VERSION 5.8 ;
BUSBITCHARS "[]" ;
DIVIDERCHAR "/" ;
UNITS
    DATABASE MICRONS 1000 ;
END UNITS

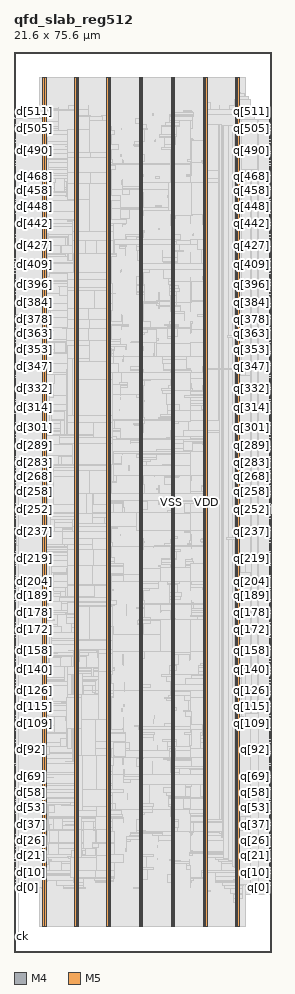
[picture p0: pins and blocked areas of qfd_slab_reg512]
MACRO qfd_slab_reg512
  FOREIGN qfd_slab_reg512 0 0 ;
  CLASS BLOCK ;
  SIZE 21.6 BY 75.6 ;
  PIN ck
    DIRECTION INPUT ;
    USE SIGNAL ;
    PORT
      LAYER M4 ;
        RECT  0.054 1.296 0.138 1.32 ;
    END
    PORT
      LAYER M4 ;
        RECT  0.108 1.296 0.371 1.32 ;
    END
  END ck
  PIN d[0]
    DIRECTION INPUT ;
    USE SIGNAL ;
    PORT
      LAYER M4 ;
        RECT  0.054 5.424 0.138 5.448 ;
    END
  END d[0]
  PIN d[100]
    DIRECTION INPUT ;
    USE SIGNAL ;
    PORT
      LAYER M4 ;
        RECT  0.054 18 0.138 18.024 ;
    END
  END d[100]
  PIN d[101]
    DIRECTION INPUT ;
    USE SIGNAL ;
    PORT
      LAYER M4 ;
        RECT  0.054 18.144 0.138 18.168 ;
    END
  END d[101]
  PIN d[102]
    DIRECTION INPUT ;
    USE SIGNAL ;
    PORT
      LAYER M4 ;
        RECT  0.054 18.288 0.138 18.312 ;
    END
  END d[102]
  PIN d[103]
    DIRECTION INPUT ;
    USE SIGNAL ;
    PORT
      LAYER M4 ;
        RECT  0.054 18.384 0.138 18.408 ;
    END
  END d[103]
  PIN d[104]
    DIRECTION INPUT ;
    USE SIGNAL ;
    PORT
      LAYER M4 ;
        RECT  0.054 18.528 0.138 18.552 ;
    END
  END d[104]
  PIN d[105]
    DIRECTION INPUT ;
    USE SIGNAL ;
    PORT
      LAYER M4 ;
        RECT  0.054 18.672 0.138 18.696 ;
    END
  END d[105]
  PIN d[106]
    DIRECTION INPUT ;
    USE SIGNAL ;
    PORT
      LAYER M4 ;
        RECT  0.054 18.768 0.138 18.792 ;
    END
  END d[106]
  PIN d[107]
    DIRECTION INPUT ;
    USE SIGNAL ;
    PORT
      LAYER M4 ;
        RECT  0.054 18.912 0.138 18.936 ;
    END
  END d[107]
  PIN d[108]
    DIRECTION INPUT ;
    USE SIGNAL ;
    PORT
      LAYER M4 ;
        RECT  0.054 19.008 0.138 19.032 ;
    END
  END d[108]
  PIN d[109]
    DIRECTION INPUT ;
    USE SIGNAL ;
    PORT
      LAYER M4 ;
        RECT  0.054 19.152 0.138 19.176 ;
    END
  END d[109]
  PIN d[10]
    DIRECTION INPUT ;
    USE SIGNAL ;
    PORT
      LAYER M4 ;
        RECT  0.054 6.672 0.138 6.696 ;
    END
  END d[10]
  PIN d[110]
    DIRECTION INPUT ;
    USE SIGNAL ;
    PORT
      LAYER M4 ;
        RECT  0.054 19.296 0.138 19.32 ;
    END
  END d[110]
  PIN d[111]
    DIRECTION INPUT ;
    USE SIGNAL ;
    PORT
      LAYER M4 ;
        RECT  0.054 19.392 0.138 19.416 ;
    END
  END d[111]
  PIN d[112]
    DIRECTION INPUT ;
    USE SIGNAL ;
    PORT
      LAYER M4 ;
        RECT  0.054 19.536 0.138 19.56 ;
    END
  END d[112]
  PIN d[113]
    DIRECTION INPUT ;
    USE SIGNAL ;
    PORT
      LAYER M4 ;
        RECT  0.054 19.68 0.138 19.704 ;
    END
  END d[113]
  PIN d[114]
    DIRECTION INPUT ;
    USE SIGNAL ;
    PORT
      LAYER M4 ;
        RECT  0.054 19.776 0.138 19.8 ;
    END
  END d[114]
  PIN d[115]
    DIRECTION INPUT ;
    USE SIGNAL ;
    PORT
      LAYER M4 ;
        RECT  0.054 19.92 0.138 19.944 ;
    END
  END d[115]
  PIN d[116]
    DIRECTION INPUT ;
    USE SIGNAL ;
    PORT
      LAYER M4 ;
        RECT  0.054 20.064 0.138 20.088 ;
    END
  END d[116]
  PIN d[117]
    DIRECTION INPUT ;
    USE SIGNAL ;
    PORT
      LAYER M4 ;
        RECT  0.054 20.16 0.138 20.184 ;
    END
  END d[117]
  PIN d[118]
    DIRECTION INPUT ;
    USE SIGNAL ;
    PORT
      LAYER M4 ;
        RECT  0.054 20.304 0.138 20.328 ;
    END
  END d[118]
  PIN d[119]
    DIRECTION INPUT ;
    USE SIGNAL ;
    PORT
      LAYER M4 ;
        RECT  0.054 20.4 0.138 20.424 ;
    END
  END d[119]
  PIN d[11]
    DIRECTION INPUT ;
    USE SIGNAL ;
    PORT
      LAYER M4 ;
        RECT  0.054 6.768 0.138 6.792 ;
    END
  END d[11]
  PIN d[120]
    DIRECTION INPUT ;
    USE SIGNAL ;
    PORT
      LAYER M4 ;
        RECT  0.054 20.544 0.138 20.568 ;
    END
  END d[120]
  PIN d[121]
    DIRECTION INPUT ;
    USE SIGNAL ;
    PORT
      LAYER M4 ;
        RECT  0.054 20.688 0.138 20.712 ;
    END
  END d[121]
  PIN d[122]
    DIRECTION INPUT ;
    USE SIGNAL ;
    PORT
      LAYER M4 ;
        RECT  0.054 20.784 0.138 20.808 ;
    END
  END d[122]
  PIN d[123]
    DIRECTION INPUT ;
    USE SIGNAL ;
    PORT
      LAYER M4 ;
        RECT  0.054 20.928 0.138 20.952 ;
    END
  END d[123]
  PIN d[124]
    DIRECTION INPUT ;
    USE SIGNAL ;
    PORT
      LAYER M4 ;
        RECT  0.054 21.072 0.138 21.096 ;
    END
  END d[124]
  PIN d[125]
    DIRECTION INPUT ;
    USE SIGNAL ;
    PORT
      LAYER M4 ;
        RECT  0.054 21.168 0.138 21.192 ;
    END
  END d[125]
  PIN d[126]
    DIRECTION INPUT ;
    USE SIGNAL ;
    PORT
      LAYER M4 ;
        RECT  0.054 21.312 0.138 21.336 ;
    END
  END d[126]
  PIN d[127]
    DIRECTION INPUT ;
    USE SIGNAL ;
    PORT
      LAYER M4 ;
        RECT  0.054 21.408 0.138 21.432 ;
    END
  END d[127]
  PIN d[128]
    DIRECTION INPUT ;
    USE SIGNAL ;
    PORT
      LAYER M4 ;
        RECT  0.054 21.552 0.138 21.576 ;
    END
  END d[128]
  PIN d[129]
    DIRECTION INPUT ;
    USE SIGNAL ;
    PORT
      LAYER M4 ;
        RECT  0.054 21.696 0.138 21.72 ;
    END
  END d[129]
  PIN d[12]
    DIRECTION INPUT ;
    USE SIGNAL ;
    PORT
      LAYER M4 ;
        RECT  0.054 6.912 0.138 6.936 ;
    END
  END d[12]
  PIN d[130]
    DIRECTION INPUT ;
    USE SIGNAL ;
    PORT
      LAYER M4 ;
        RECT  0.054 21.792 0.138 21.816 ;
    END
  END d[130]
  PIN d[131]
    DIRECTION INPUT ;
    USE SIGNAL ;
    PORT
      LAYER M4 ;
        RECT  0.054 21.936 0.138 21.96 ;
    END
  END d[131]
  PIN d[132]
    DIRECTION INPUT ;
    USE SIGNAL ;
    PORT
      LAYER M4 ;
        RECT  0.054 22.08 0.138 22.104 ;
    END
  END d[132]
  PIN d[133]
    DIRECTION INPUT ;
    USE SIGNAL ;
    PORT
      LAYER M4 ;
        RECT  0.054 22.176 0.138 22.2 ;
    END
  END d[133]
  PIN d[134]
    DIRECTION INPUT ;
    USE SIGNAL ;
    PORT
      LAYER M4 ;
        RECT  0.054 22.32 0.138 22.344 ;
    END
  END d[134]
  PIN d[135]
    DIRECTION INPUT ;
    USE SIGNAL ;
    PORT
      LAYER M4 ;
        RECT  0.054 22.464 0.138 22.488 ;
    END
  END d[135]
  PIN d[136]
    DIRECTION INPUT ;
    USE SIGNAL ;
    PORT
      LAYER M4 ;
        RECT  0.054 22.56 0.138 22.584 ;
    END
  END d[136]
  PIN d[137]
    DIRECTION INPUT ;
    USE SIGNAL ;
    PORT
      LAYER M4 ;
        RECT  0.054 22.704 0.138 22.728 ;
    END
  END d[137]
  PIN d[138]
    DIRECTION INPUT ;
    USE SIGNAL ;
    PORT
      LAYER M4 ;
        RECT  0.054 22.8 0.138 22.824 ;
    END
  END d[138]
  PIN d[139]
    DIRECTION INPUT ;
    USE SIGNAL ;
    PORT
      LAYER M4 ;
        RECT  0.054 22.944 0.138 22.968 ;
    END
  END d[139]
  PIN d[13]
    DIRECTION INPUT ;
    USE SIGNAL ;
    PORT
      LAYER M4 ;
        RECT  0.054 7.008 0.138 7.032 ;
    END
  END d[13]
  PIN d[140]
    DIRECTION INPUT ;
    USE SIGNAL ;
    PORT
      LAYER M4 ;
        RECT  0.054 23.088 0.138 23.112 ;
    END
  END d[140]
  PIN d[141]
    DIRECTION INPUT ;
    USE SIGNAL ;
    PORT
      LAYER M4 ;
        RECT  0.054 23.184 0.138 23.208 ;
    END
  END d[141]
  PIN d[142]
    DIRECTION INPUT ;
    USE SIGNAL ;
    PORT
      LAYER M4 ;
        RECT  0.054 23.328 0.138 23.352 ;
    END
  END d[142]
  PIN d[143]
    DIRECTION INPUT ;
    USE SIGNAL ;
    PORT
      LAYER M4 ;
        RECT  0.054 23.472 0.138 23.496 ;
    END
  END d[143]
  PIN d[144]
    DIRECTION INPUT ;
    USE SIGNAL ;
    PORT
      LAYER M4 ;
        RECT  0.054 23.568 0.138 23.592 ;
    END
  END d[144]
  PIN d[145]
    DIRECTION INPUT ;
    USE SIGNAL ;
    PORT
      LAYER M4 ;
        RECT  0.054 23.712 0.138 23.736 ;
    END
  END d[145]
  PIN d[146]
    DIRECTION INPUT ;
    USE SIGNAL ;
    PORT
      LAYER M4 ;
        RECT  0.054 23.808 0.138 23.832 ;
    END
  END d[146]
  PIN d[147]
    DIRECTION INPUT ;
    USE SIGNAL ;
    PORT
      LAYER M4 ;
        RECT  0.054 23.952 0.138 23.976 ;
    END
  END d[147]
  PIN d[148]
    DIRECTION INPUT ;
    USE SIGNAL ;
    PORT
      LAYER M4 ;
        RECT  0.054 24.096 0.138 24.12 ;
    END
  END d[148]
  PIN d[149]
    DIRECTION INPUT ;
    USE SIGNAL ;
    PORT
      LAYER M4 ;
        RECT  0.054 24.192 0.138 24.216 ;
    END
  END d[149]
  PIN d[14]
    DIRECTION INPUT ;
    USE SIGNAL ;
    PORT
      LAYER M4 ;
        RECT  0.054 7.152 0.138 7.176 ;
    END
  END d[14]
  PIN d[150]
    DIRECTION INPUT ;
    USE SIGNAL ;
    PORT
      LAYER M4 ;
        RECT  0.054 24.336 0.138 24.36 ;
    END
  END d[150]
  PIN d[151]
    DIRECTION INPUT ;
    USE SIGNAL ;
    PORT
      LAYER M4 ;
        RECT  0.054 24.48 0.138 24.504 ;
    END
  END d[151]
  PIN d[152]
    DIRECTION INPUT ;
    USE SIGNAL ;
    PORT
      LAYER M4 ;
        RECT  0.054 24.576 0.138 24.6 ;
    END
  END d[152]
  PIN d[153]
    DIRECTION INPUT ;
    USE SIGNAL ;
    PORT
      LAYER M4 ;
        RECT  0.054 24.72 0.138 24.744 ;
    END
  END d[153]
  PIN d[154]
    DIRECTION INPUT ;
    USE SIGNAL ;
    PORT
      LAYER M4 ;
        RECT  0.054 24.864 0.138 24.888 ;
    END
  END d[154]
  PIN d[155]
    DIRECTION INPUT ;
    USE SIGNAL ;
    PORT
      LAYER M4 ;
        RECT  0.054 24.96 0.138 24.984 ;
    END
  END d[155]
  PIN d[156]
    DIRECTION INPUT ;
    USE SIGNAL ;
    PORT
      LAYER M4 ;
        RECT  0.054 25.104 0.138 25.128 ;
    END
  END d[156]
  PIN d[157]
    DIRECTION INPUT ;
    USE SIGNAL ;
    PORT
      LAYER M4 ;
        RECT  0.054 25.2 0.138 25.224 ;
    END
  END d[157]
  PIN d[158]
    DIRECTION INPUT ;
    USE SIGNAL ;
    PORT
      LAYER M4 ;
        RECT  0.054 25.344 0.138 25.368 ;
    END
  END d[158]
  PIN d[159]
    DIRECTION INPUT ;
    USE SIGNAL ;
    PORT
      LAYER M4 ;
        RECT  0.054 25.488 0.138 25.512 ;
    END
  END d[159]
  PIN d[15]
    DIRECTION INPUT ;
    USE SIGNAL ;
    PORT
      LAYER M4 ;
        RECT  0.054 7.296 0.138 7.32 ;
    END
  END d[15]
  PIN d[160]
    DIRECTION INPUT ;
    USE SIGNAL ;
    PORT
      LAYER M4 ;
        RECT  0.054 25.584 0.138 25.608 ;
    END
  END d[160]
  PIN d[161]
    DIRECTION INPUT ;
    USE SIGNAL ;
    PORT
      LAYER M4 ;
        RECT  0.054 25.728 0.138 25.752 ;
    END
  END d[161]
  PIN d[162]
    DIRECTION INPUT ;
    USE SIGNAL ;
    PORT
      LAYER M4 ;
        RECT  0.054 25.872 0.138 25.896 ;
    END
  END d[162]
  PIN d[163]
    DIRECTION INPUT ;
    USE SIGNAL ;
    PORT
      LAYER M4 ;
        RECT  0.054 25.968 0.138 25.992 ;
    END
  END d[163]
  PIN d[164]
    DIRECTION INPUT ;
    USE SIGNAL ;
    PORT
      LAYER M4 ;
        RECT  0.054 26.112 0.138 26.136 ;
    END
  END d[164]
  PIN d[165]
    DIRECTION INPUT ;
    USE SIGNAL ;
    PORT
      LAYER M4 ;
        RECT  0.054 26.208 0.138 26.232 ;
    END
  END d[165]
  PIN d[166]
    DIRECTION INPUT ;
    USE SIGNAL ;
    PORT
      LAYER M4 ;
        RECT  0.054 26.352 0.138 26.376 ;
    END
  END d[166]
  PIN d[167]
    DIRECTION INPUT ;
    USE SIGNAL ;
    PORT
      LAYER M4 ;
        RECT  0.054 26.496 0.138 26.52 ;
    END
  END d[167]
  PIN d[168]
    DIRECTION INPUT ;
    USE SIGNAL ;
    PORT
      LAYER M4 ;
        RECT  0.054 26.592 0.138 26.616 ;
    END
    PORT
      LAYER M4 ;
        RECT  0.025 26.592 0.108 26.616 ;
    END
  END d[168]
  PIN d[169]
    DIRECTION INPUT ;
    USE SIGNAL ;
    PORT
      LAYER M4 ;
        RECT  0.054 26.736 0.138 26.76 ;
    END
  END d[169]
  PIN d[16]
    DIRECTION INPUT ;
    USE SIGNAL ;
    PORT
      LAYER M4 ;
        RECT  0.054 7.392 0.138 7.416 ;
    END
  END d[16]
  PIN d[170]
    DIRECTION INPUT ;
    USE SIGNAL ;
    PORT
      LAYER M4 ;
        RECT  0.054 26.88 0.138 26.904 ;
    END
  END d[170]
  PIN d[171]
    DIRECTION INPUT ;
    USE SIGNAL ;
    PORT
      LAYER M4 ;
        RECT  0.054 26.976 0.138 27 ;
    END
  END d[171]
  PIN d[172]
    DIRECTION INPUT ;
    USE SIGNAL ;
    PORT
      LAYER M4 ;
        RECT  0.054 27.12 0.138 27.144 ;
    END
  END d[172]
  PIN d[173]
    DIRECTION INPUT ;
    USE SIGNAL ;
    PORT
      LAYER M4 ;
        RECT  0.054 27.264 0.138 27.288 ;
    END
  END d[173]
  PIN d[174]
    DIRECTION INPUT ;
    USE SIGNAL ;
    PORT
      LAYER M4 ;
        RECT  0.054 27.36 0.138 27.384 ;
    END
  END d[174]
  PIN d[175]
    DIRECTION INPUT ;
    USE SIGNAL ;
    PORT
      LAYER M4 ;
        RECT  0.054 27.504 0.138 27.528 ;
    END
  END d[175]
  PIN d[176]
    DIRECTION INPUT ;
    USE SIGNAL ;
    PORT
      LAYER M4 ;
        RECT  0.054 27.6 0.138 27.624 ;
    END
  END d[176]
  PIN d[177]
    DIRECTION INPUT ;
    USE SIGNAL ;
    PORT
      LAYER M4 ;
        RECT  0.054 27.744 0.138 27.768 ;
    END
  END d[177]
  PIN d[178]
    DIRECTION INPUT ;
    USE SIGNAL ;
    PORT
      LAYER M4 ;
        RECT  0.054 27.888 0.138 27.912 ;
    END
  END d[178]
  PIN d[179]
    DIRECTION INPUT ;
    USE SIGNAL ;
    PORT
      LAYER M4 ;
        RECT  0.054 27.984 0.138 28.008 ;
    END
  END d[179]
  PIN d[17]
    DIRECTION INPUT ;
    USE SIGNAL ;
    PORT
      LAYER M4 ;
        RECT  0.054 7.536 0.138 7.56 ;
    END
  END d[17]
  PIN d[180]
    DIRECTION INPUT ;
    USE SIGNAL ;
    PORT
      LAYER M4 ;
        RECT  0.054 28.128 0.138 28.152 ;
    END
  END d[180]
  PIN d[181]
    DIRECTION INPUT ;
    USE SIGNAL ;
    PORT
      LAYER M4 ;
        RECT  0.054 28.272 0.138 28.296 ;
    END
  END d[181]
  PIN d[182]
    DIRECTION INPUT ;
    USE SIGNAL ;
    PORT
      LAYER M4 ;
        RECT  0.054 28.368 0.138 28.392 ;
    END
  END d[182]
  PIN d[183]
    DIRECTION INPUT ;
    USE SIGNAL ;
    PORT
      LAYER M4 ;
        RECT  0.054 28.512 0.138 28.536 ;
    END
  END d[183]
  PIN d[184]
    DIRECTION INPUT ;
    USE SIGNAL ;
    PORT
      LAYER M4 ;
        RECT  0.054 28.608 0.138 28.632 ;
    END
  END d[184]
  PIN d[185]
    DIRECTION INPUT ;
    USE SIGNAL ;
    PORT
      LAYER M4 ;
        RECT  0.054 28.752 0.138 28.776 ;
    END
  END d[185]
  PIN d[186]
    DIRECTION INPUT ;
    USE SIGNAL ;
    PORT
      LAYER M4 ;
        RECT  0.054 28.896 0.138 28.92 ;
    END
  END d[186]
  PIN d[187]
    DIRECTION INPUT ;
    USE SIGNAL ;
    PORT
      LAYER M4 ;
        RECT  0.054 28.992 0.138 29.016 ;
    END
  END d[187]
  PIN d[188]
    DIRECTION INPUT ;
    USE SIGNAL ;
    PORT
      LAYER M4 ;
        RECT  0.054 29.136 0.138 29.16 ;
    END
  END d[188]
  PIN d[189]
    DIRECTION INPUT ;
    USE SIGNAL ;
    PORT
      LAYER M4 ;
        RECT  0.054 29.28 0.138 29.304 ;
    END
  END d[189]
  PIN d[18]
    DIRECTION INPUT ;
    USE SIGNAL ;
    PORT
      LAYER M4 ;
        RECT  0.054 7.68 0.138 7.704 ;
    END
  END d[18]
  PIN d[190]
    DIRECTION INPUT ;
    USE SIGNAL ;
    PORT
      LAYER M4 ;
        RECT  0.054 29.376 0.138 29.4 ;
    END
  END d[190]
  PIN d[191]
    DIRECTION INPUT ;
    USE SIGNAL ;
    PORT
      LAYER M4 ;
        RECT  0.054 29.52 0.138 29.544 ;
    END
  END d[191]
  PIN d[192]
    DIRECTION INPUT ;
    USE SIGNAL ;
    PORT
      LAYER M4 ;
        RECT  0.054 29.664 0.138 29.688 ;
    END
  END d[192]
  PIN d[193]
    DIRECTION INPUT ;
    USE SIGNAL ;
    PORT
      LAYER M4 ;
        RECT  0.054 29.76 0.138 29.784 ;
    END
  END d[193]
  PIN d[194]
    DIRECTION INPUT ;
    USE SIGNAL ;
    PORT
      LAYER M4 ;
        RECT  0.054 29.904 0.138 29.928 ;
    END
  END d[194]
  PIN d[195]
    DIRECTION INPUT ;
    USE SIGNAL ;
    PORT
      LAYER M4 ;
        RECT  0.054 30 0.138 30.024 ;
    END
  END d[195]
  PIN d[196]
    DIRECTION INPUT ;
    USE SIGNAL ;
    PORT
      LAYER M4 ;
        RECT  0.054 30.144 0.138 30.168 ;
    END
  END d[196]
  PIN d[197]
    DIRECTION INPUT ;
    USE SIGNAL ;
    PORT
      LAYER M4 ;
        RECT  0.054 30.288 0.138 30.312 ;
    END
  END d[197]
  PIN d[198]
    DIRECTION INPUT ;
    USE SIGNAL ;
    PORT
      LAYER M4 ;
        RECT  0.054 30.384 0.138 30.408 ;
    END
  END d[198]
  PIN d[199]
    DIRECTION INPUT ;
    USE SIGNAL ;
    PORT
      LAYER M4 ;
        RECT  0.054 30.528 0.138 30.552 ;
    END
  END d[199]
  PIN d[19]
    DIRECTION INPUT ;
    USE SIGNAL ;
    PORT
      LAYER M4 ;
        RECT  0.054 7.776 0.138 7.8 ;
    END
  END d[19]
  PIN d[1]
    DIRECTION INPUT ;
    USE SIGNAL ;
    PORT
      LAYER M4 ;
        RECT  0.054 5.52 0.138 5.544 ;
    END
  END d[1]
  PIN d[200]
    DIRECTION INPUT ;
    USE SIGNAL ;
    PORT
      LAYER M4 ;
        RECT  0.054 30.672 0.138 30.696 ;
    END
  END d[200]
  PIN d[201]
    DIRECTION INPUT ;
    USE SIGNAL ;
    PORT
      LAYER M4 ;
        RECT  0.054 30.768 0.138 30.792 ;
    END
  END d[201]
  PIN d[202]
    DIRECTION INPUT ;
    USE SIGNAL ;
    PORT
      LAYER M4 ;
        RECT  0.054 30.912 0.138 30.936 ;
    END
  END d[202]
  PIN d[203]
    DIRECTION INPUT ;
    USE SIGNAL ;
    PORT
      LAYER M4 ;
        RECT  0.054 31.008 0.138 31.032 ;
    END
  END d[203]
  PIN d[204]
    DIRECTION INPUT ;
    USE SIGNAL ;
    PORT
      LAYER M4 ;
        RECT  0.054 31.152 0.138 31.176 ;
    END
  END d[204]
  PIN d[205]
    DIRECTION INPUT ;
    USE SIGNAL ;
    PORT
      LAYER M4 ;
        RECT  0.054 31.296 0.138 31.32 ;
    END
  END d[205]
  PIN d[206]
    DIRECTION INPUT ;
    USE SIGNAL ;
    PORT
      LAYER M4 ;
        RECT  0.054 31.392 0.138 31.416 ;
    END
  END d[206]
  PIN d[207]
    DIRECTION INPUT ;
    USE SIGNAL ;
    PORT
      LAYER M4 ;
        RECT  0.054 31.536 0.138 31.56 ;
    END
  END d[207]
  PIN d[208]
    DIRECTION INPUT ;
    USE SIGNAL ;
    PORT
      LAYER M4 ;
        RECT  0.054 31.68 0.138 31.704 ;
    END
  END d[208]
  PIN d[209]
    DIRECTION INPUT ;
    USE SIGNAL ;
    PORT
      LAYER M4 ;
        RECT  0.054 31.776 0.138 31.8 ;
    END
  END d[209]
  PIN d[20]
    DIRECTION INPUT ;
    USE SIGNAL ;
    PORT
      LAYER M4 ;
        RECT  0.054 7.92 0.138 7.944 ;
    END
  END d[20]
  PIN d[210]
    DIRECTION INPUT ;
    USE SIGNAL ;
    PORT
      LAYER M4 ;
        RECT  0.054 31.92 0.138 31.944 ;
    END
  END d[210]
  PIN d[211]
    DIRECTION INPUT ;
    USE SIGNAL ;
    PORT
      LAYER M4 ;
        RECT  0.054 32.064 0.138 32.088 ;
    END
  END d[211]
  PIN d[212]
    DIRECTION INPUT ;
    USE SIGNAL ;
    PORT
      LAYER M4 ;
        RECT  0.054 32.16 0.138 32.184 ;
    END
  END d[212]
  PIN d[213]
    DIRECTION INPUT ;
    USE SIGNAL ;
    PORT
      LAYER M4 ;
        RECT  0.054 32.304 0.138 32.328 ;
    END
  END d[213]
  PIN d[214]
    DIRECTION INPUT ;
    USE SIGNAL ;
    PORT
      LAYER M4 ;
        RECT  0.054 32.4 0.138 32.424 ;
    END
  END d[214]
  PIN d[215]
    DIRECTION INPUT ;
    USE SIGNAL ;
    PORT
      LAYER M4 ;
        RECT  0.054 32.544 0.138 32.568 ;
    END
  END d[215]
  PIN d[216]
    DIRECTION INPUT ;
    USE SIGNAL ;
    PORT
      LAYER M4 ;
        RECT  0.054 32.688 0.138 32.712 ;
    END
  END d[216]
  PIN d[217]
    DIRECTION INPUT ;
    USE SIGNAL ;
    PORT
      LAYER M4 ;
        RECT  0.054 32.784 0.138 32.808 ;
    END
  END d[217]
  PIN d[218]
    DIRECTION INPUT ;
    USE SIGNAL ;
    PORT
      LAYER M4 ;
        RECT  0.054 32.928 0.138 32.952 ;
    END
  END d[218]
  PIN d[219]
    DIRECTION INPUT ;
    USE SIGNAL ;
    PORT
      LAYER M4 ;
        RECT  0.054 33.072 0.138 33.096 ;
    END
  END d[219]
  PIN d[21]
    DIRECTION INPUT ;
    USE SIGNAL ;
    PORT
      LAYER M4 ;
        RECT  0.054 8.064 0.138 8.088 ;
    END
  END d[21]
  PIN d[220]
    DIRECTION INPUT ;
    USE SIGNAL ;
    PORT
      LAYER M4 ;
        RECT  0.054 33.168 0.138 33.192 ;
    END
  END d[220]
  PIN d[221]
    DIRECTION INPUT ;
    USE SIGNAL ;
    PORT
      LAYER M4 ;
        RECT  0.054 33.312 0.138 33.336 ;
    END
  END d[221]
  PIN d[222]
    DIRECTION INPUT ;
    USE SIGNAL ;
    PORT
      LAYER M4 ;
        RECT  0.054 33.408 0.138 33.432 ;
    END
  END d[222]
  PIN d[223]
    DIRECTION INPUT ;
    USE SIGNAL ;
    PORT
      LAYER M4 ;
        RECT  0.054 33.552 0.138 33.576 ;
    END
  END d[223]
  PIN d[224]
    DIRECTION INPUT ;
    USE SIGNAL ;
    PORT
      LAYER M4 ;
        RECT  0.054 33.696 0.138 33.72 ;
    END
  END d[224]
  PIN d[225]
    DIRECTION INPUT ;
    USE SIGNAL ;
    PORT
      LAYER M4 ;
        RECT  0.054 33.792 0.138 33.816 ;
    END
  END d[225]
  PIN d[226]
    DIRECTION INPUT ;
    USE SIGNAL ;
    PORT
      LAYER M4 ;
        RECT  0.054 33.936 0.138 33.96 ;
    END
  END d[226]
  PIN d[227]
    DIRECTION INPUT ;
    USE SIGNAL ;
    PORT
      LAYER M4 ;
        RECT  0.054 34.08 0.138 34.104 ;
    END
  END d[227]
  PIN d[228]
    DIRECTION INPUT ;
    USE SIGNAL ;
    PORT
      LAYER M4 ;
        RECT  0.054 34.176 0.138 34.2 ;
    END
  END d[228]
  PIN d[229]
    DIRECTION INPUT ;
    USE SIGNAL ;
    PORT
      LAYER M4 ;
        RECT  0.054 34.32 0.138 34.344 ;
    END
  END d[229]
  PIN d[22]
    DIRECTION INPUT ;
    USE SIGNAL ;
    PORT
      LAYER M4 ;
        RECT  0.054 8.16 0.138 8.184 ;
    END
  END d[22]
  PIN d[230]
    DIRECTION INPUT ;
    USE SIGNAL ;
    PORT
      LAYER M4 ;
        RECT  0.054 34.464 0.138 34.488 ;
    END
  END d[230]
  PIN d[231]
    DIRECTION INPUT ;
    USE SIGNAL ;
    PORT
      LAYER M4 ;
        RECT  0.054 34.56 0.138 34.584 ;
    END
  END d[231]
  PIN d[232]
    DIRECTION INPUT ;
    USE SIGNAL ;
    PORT
      LAYER M4 ;
        RECT  0.054 34.704 0.138 34.728 ;
    END
  END d[232]
  PIN d[233]
    DIRECTION INPUT ;
    USE SIGNAL ;
    PORT
      LAYER M4 ;
        RECT  0.054 34.8 0.138 34.824 ;
    END
  END d[233]
  PIN d[234]
    DIRECTION INPUT ;
    USE SIGNAL ;
    PORT
      LAYER M4 ;
        RECT  0.054 34.944 0.138 34.968 ;
    END
  END d[234]
  PIN d[235]
    DIRECTION INPUT ;
    USE SIGNAL ;
    PORT
      LAYER M4 ;
        RECT  0.054 35.088 0.138 35.112 ;
    END
  END d[235]
  PIN d[236]
    DIRECTION INPUT ;
    USE SIGNAL ;
    PORT
      LAYER M4 ;
        RECT  0.054 35.184 0.138 35.208 ;
    END
  END d[236]
  PIN d[237]
    DIRECTION INPUT ;
    USE SIGNAL ;
    PORT
      LAYER M4 ;
        RECT  0.054 35.328 0.138 35.352 ;
    END
  END d[237]
  PIN d[238]
    DIRECTION INPUT ;
    USE SIGNAL ;
    PORT
      LAYER M4 ;
        RECT  0.054 35.472 0.138 35.496 ;
    END
  END d[238]
  PIN d[239]
    DIRECTION INPUT ;
    USE SIGNAL ;
    PORT
      LAYER M4 ;
        RECT  0.054 35.568 0.138 35.592 ;
    END
  END d[239]
  PIN d[23]
    DIRECTION INPUT ;
    USE SIGNAL ;
    PORT
      LAYER M4 ;
        RECT  0.054 8.304 0.138 8.328 ;
    END
  END d[23]
  PIN d[240]
    DIRECTION INPUT ;
    USE SIGNAL ;
    PORT
      LAYER M4 ;
        RECT  0.054 35.712 0.138 35.736 ;
    END
  END d[240]
  PIN d[241]
    DIRECTION INPUT ;
    USE SIGNAL ;
    PORT
      LAYER M4 ;
        RECT  0.054 35.808 0.138 35.832 ;
    END
    PORT
      LAYER M4 ;
        RECT  0.025 35.808 0.108 35.832 ;
    END
  END d[241]
  PIN d[242]
    DIRECTION INPUT ;
    USE SIGNAL ;
    PORT
      LAYER M4 ;
        RECT  0.054 35.952 0.138 35.976 ;
    END
  END d[242]
  PIN d[243]
    DIRECTION INPUT ;
    USE SIGNAL ;
    PORT
      LAYER M4 ;
        RECT  0.054 36.096 0.138 36.12 ;
    END
  END d[243]
  PIN d[244]
    DIRECTION INPUT ;
    USE SIGNAL ;
    PORT
      LAYER M4 ;
        RECT  0.054 36.192 0.138 36.216 ;
    END
  END d[244]
  PIN d[245]
    DIRECTION INPUT ;
    USE SIGNAL ;
    PORT
      LAYER M4 ;
        RECT  0.054 36.336 0.138 36.36 ;
    END
  END d[245]
  PIN d[246]
    DIRECTION INPUT ;
    USE SIGNAL ;
    PORT
      LAYER M4 ;
        RECT  0.054 36.48 0.138 36.504 ;
    END
  END d[246]
  PIN d[247]
    DIRECTION INPUT ;
    USE SIGNAL ;
    PORT
      LAYER M4 ;
        RECT  0.054 36.576 0.138 36.6 ;
    END
  END d[247]
  PIN d[248]
    DIRECTION INPUT ;
    USE SIGNAL ;
    PORT
      LAYER M4 ;
        RECT  0.054 36.72 0.138 36.744 ;
    END
  END d[248]
  PIN d[249]
    DIRECTION INPUT ;
    USE SIGNAL ;
    PORT
      LAYER M4 ;
        RECT  0.054 36.864 0.138 36.888 ;
    END
  END d[249]
  PIN d[24]
    DIRECTION INPUT ;
    USE SIGNAL ;
    PORT
      LAYER M4 ;
        RECT  0.054 8.4 0.138 8.424 ;
    END
  END d[24]
  PIN d[250]
    DIRECTION INPUT ;
    USE SIGNAL ;
    PORT
      LAYER M4 ;
        RECT  0.054 36.96 0.138 36.984 ;
    END
  END d[250]
  PIN d[251]
    DIRECTION INPUT ;
    USE SIGNAL ;
    PORT
      LAYER M4 ;
        RECT  0.054 37.104 0.138 37.128 ;
    END
  END d[251]
  PIN d[252]
    DIRECTION INPUT ;
    USE SIGNAL ;
    PORT
      LAYER M4 ;
        RECT  0.054 37.2 0.138 37.224 ;
    END
  END d[252]
  PIN d[253]
    DIRECTION INPUT ;
    USE SIGNAL ;
    PORT
      LAYER M4 ;
        RECT  0.054 37.344 0.138 37.368 ;
    END
  END d[253]
  PIN d[254]
    DIRECTION INPUT ;
    USE SIGNAL ;
    PORT
      LAYER M4 ;
        RECT  0.054 37.488 0.138 37.512 ;
    END
  END d[254]
  PIN d[255]
    DIRECTION INPUT ;
    USE SIGNAL ;
    PORT
      LAYER M4 ;
        RECT  0.054 37.584 0.138 37.608 ;
    END
  END d[255]
  PIN d[256]
    DIRECTION INPUT ;
    USE SIGNAL ;
    PORT
      LAYER M4 ;
        RECT  0.054 37.728 0.138 37.752 ;
    END
  END d[256]
  PIN d[257]
    DIRECTION INPUT ;
    USE SIGNAL ;
    PORT
      LAYER M4 ;
        RECT  0.054 37.872 0.138 37.896 ;
    END
  END d[257]
  PIN d[258]
    DIRECTION INPUT ;
    USE SIGNAL ;
    PORT
      LAYER M4 ;
        RECT  0.054 37.968 0.138 37.992 ;
    END
  END d[258]
  PIN d[259]
    DIRECTION INPUT ;
    USE SIGNAL ;
    PORT
      LAYER M4 ;
        RECT  0.054 38.112 0.138 38.136 ;
    END
  END d[259]
  PIN d[25]
    DIRECTION INPUT ;
    USE SIGNAL ;
    PORT
      LAYER M4 ;
        RECT  0.054 8.544 0.138 8.568 ;
    END
  END d[25]
  PIN d[260]
    DIRECTION INPUT ;
    USE SIGNAL ;
    PORT
      LAYER M4 ;
        RECT  0.054 38.208 0.138 38.232 ;
    END
  END d[260]
  PIN d[261]
    DIRECTION INPUT ;
    USE SIGNAL ;
    PORT
      LAYER M4 ;
        RECT  0.054 38.352 0.138 38.376 ;
    END
  END d[261]
  PIN d[262]
    DIRECTION INPUT ;
    USE SIGNAL ;
    PORT
      LAYER M4 ;
        RECT  0.054 38.496 0.138 38.52 ;
    END
  END d[262]
  PIN d[263]
    DIRECTION INPUT ;
    USE SIGNAL ;
    PORT
      LAYER M4 ;
        RECT  0.054 38.592 0.138 38.616 ;
    END
  END d[263]
  PIN d[264]
    DIRECTION INPUT ;
    USE SIGNAL ;
    PORT
      LAYER M4 ;
        RECT  0.054 38.736 0.138 38.76 ;
    END
  END d[264]
  PIN d[265]
    DIRECTION INPUT ;
    USE SIGNAL ;
    PORT
      LAYER M4 ;
        RECT  0.054 38.88 0.138 38.904 ;
    END
    PORT
      LAYER M4 ;
        RECT  0.025 38.88 0.108 38.904 ;
    END
  END d[265]
  PIN d[266]
    DIRECTION INPUT ;
    USE SIGNAL ;
    PORT
      LAYER M4 ;
        RECT  0.054 38.976 0.138 39 ;
    END
  END d[266]
  PIN d[267]
    DIRECTION INPUT ;
    USE SIGNAL ;
    PORT
      LAYER M4 ;
        RECT  0.054 39.12 0.138 39.144 ;
    END
  END d[267]
  PIN d[268]
    DIRECTION INPUT ;
    USE SIGNAL ;
    PORT
      LAYER M4 ;
        RECT  0.054 39.264 0.138 39.288 ;
    END
  END d[268]
  PIN d[269]
    DIRECTION INPUT ;
    USE SIGNAL ;
    PORT
      LAYER M4 ;
        RECT  0.054 39.36 0.138 39.384 ;
    END
  END d[269]
  PIN d[26]
    DIRECTION INPUT ;
    USE SIGNAL ;
    PORT
      LAYER M4 ;
        RECT  0.054 8.688 0.138 8.712 ;
    END
  END d[26]
  PIN d[270]
    DIRECTION INPUT ;
    USE SIGNAL ;
    PORT
      LAYER M4 ;
        RECT  0.054 39.504 0.138 39.528 ;
    END
  END d[270]
  PIN d[271]
    DIRECTION INPUT ;
    USE SIGNAL ;
    PORT
      LAYER M4 ;
        RECT  0.054 39.6 0.138 39.624 ;
    END
  END d[271]
  PIN d[272]
    DIRECTION INPUT ;
    USE SIGNAL ;
    PORT
      LAYER M4 ;
        RECT  0.054 39.744 0.138 39.768 ;
    END
  END d[272]
  PIN d[273]
    DIRECTION INPUT ;
    USE SIGNAL ;
    PORT
      LAYER M4 ;
        RECT  0.054 39.888 0.138 39.912 ;
    END
  END d[273]
  PIN d[274]
    DIRECTION INPUT ;
    USE SIGNAL ;
    PORT
      LAYER M4 ;
        RECT  0.054 39.984 0.138 40.008 ;
    END
  END d[274]
  PIN d[275]
    DIRECTION INPUT ;
    USE SIGNAL ;
    PORT
      LAYER M4 ;
        RECT  0.054 40.128 0.138 40.152 ;
    END
  END d[275]
  PIN d[276]
    DIRECTION INPUT ;
    USE SIGNAL ;
    PORT
      LAYER M4 ;
        RECT  0.054 40.272 0.138 40.296 ;
    END
  END d[276]
  PIN d[277]
    DIRECTION INPUT ;
    USE SIGNAL ;
    PORT
      LAYER M4 ;
        RECT  0.054 40.368 0.138 40.392 ;
    END
  END d[277]
  PIN d[278]
    DIRECTION INPUT ;
    USE SIGNAL ;
    PORT
      LAYER M4 ;
        RECT  0.054 40.512 0.138 40.536 ;
    END
  END d[278]
  PIN d[279]
    DIRECTION INPUT ;
    USE SIGNAL ;
    PORT
      LAYER M4 ;
        RECT  0.054 40.608 0.138 40.632 ;
    END
  END d[279]
  PIN d[27]
    DIRECTION INPUT ;
    USE SIGNAL ;
    PORT
      LAYER M4 ;
        RECT  0.054 8.784 0.138 8.808 ;
    END
  END d[27]
  PIN d[280]
    DIRECTION INPUT ;
    USE SIGNAL ;
    PORT
      LAYER M4 ;
        RECT  0.054 40.752 0.138 40.776 ;
    END
  END d[280]
  PIN d[281]
    DIRECTION INPUT ;
    USE SIGNAL ;
    PORT
      LAYER M4 ;
        RECT  0.054 40.896 0.138 40.92 ;
    END
  END d[281]
  PIN d[282]
    DIRECTION INPUT ;
    USE SIGNAL ;
    PORT
      LAYER M4 ;
        RECT  0.054 40.992 0.138 41.016 ;
    END
  END d[282]
  PIN d[283]
    DIRECTION INPUT ;
    USE SIGNAL ;
    PORT
      LAYER M4 ;
        RECT  0.054 41.136 0.138 41.16 ;
    END
  END d[283]
  PIN d[284]
    DIRECTION INPUT ;
    USE SIGNAL ;
    PORT
      LAYER M4 ;
        RECT  0.054 41.28 0.138 41.304 ;
    END
  END d[284]
  PIN d[285]
    DIRECTION INPUT ;
    USE SIGNAL ;
    PORT
      LAYER M4 ;
        RECT  0.054 41.376 0.138 41.4 ;
    END
  END d[285]
  PIN d[286]
    DIRECTION INPUT ;
    USE SIGNAL ;
    PORT
      LAYER M4 ;
        RECT  0.054 41.52 0.138 41.544 ;
    END
  END d[286]
  PIN d[287]
    DIRECTION INPUT ;
    USE SIGNAL ;
    PORT
      LAYER M4 ;
        RECT  0.054 41.664 0.138 41.688 ;
    END
  END d[287]
  PIN d[288]
    DIRECTION INPUT ;
    USE SIGNAL ;
    PORT
      LAYER M4 ;
        RECT  0.054 41.76 0.138 41.784 ;
    END
  END d[288]
  PIN d[289]
    DIRECTION INPUT ;
    USE SIGNAL ;
    PORT
      LAYER M4 ;
        RECT  0.054 41.904 0.138 41.928 ;
    END
  END d[289]
  PIN d[28]
    DIRECTION INPUT ;
    USE SIGNAL ;
    PORT
      LAYER M4 ;
        RECT  0.054 8.928 0.138 8.952 ;
    END
  END d[28]
  PIN d[290]
    DIRECTION INPUT ;
    USE SIGNAL ;
    PORT
      LAYER M4 ;
        RECT  0.054 42 0.138 42.024 ;
    END
  END d[290]
  PIN d[291]
    DIRECTION INPUT ;
    USE SIGNAL ;
    PORT
      LAYER M4 ;
        RECT  0.054 42.144 0.138 42.168 ;
    END
  END d[291]
  PIN d[292]
    DIRECTION INPUT ;
    USE SIGNAL ;
    PORT
      LAYER M4 ;
        RECT  0.054 42.288 0.138 42.312 ;
    END
  END d[292]
  PIN d[293]
    DIRECTION INPUT ;
    USE SIGNAL ;
    PORT
      LAYER M4 ;
        RECT  0.054 42.384 0.138 42.408 ;
    END
  END d[293]
  PIN d[294]
    DIRECTION INPUT ;
    USE SIGNAL ;
    PORT
      LAYER M4 ;
        RECT  0.054 42.528 0.138 42.552 ;
    END
  END d[294]
  PIN d[295]
    DIRECTION INPUT ;
    USE SIGNAL ;
    PORT
      LAYER M4 ;
        RECT  0.054 42.672 0.138 42.696 ;
    END
  END d[295]
  PIN d[296]
    DIRECTION INPUT ;
    USE SIGNAL ;
    PORT
      LAYER M4 ;
        RECT  0.054 42.768 0.138 42.792 ;
    END
  END d[296]
  PIN d[297]
    DIRECTION INPUT ;
    USE SIGNAL ;
    PORT
      LAYER M4 ;
        RECT  0.054 42.912 0.138 42.936 ;
    END
  END d[297]
  PIN d[298]
    DIRECTION INPUT ;
    USE SIGNAL ;
    PORT
      LAYER M4 ;
        RECT  0.054 43.008 0.138 43.032 ;
    END
  END d[298]
  PIN d[299]
    DIRECTION INPUT ;
    USE SIGNAL ;
    PORT
      LAYER M4 ;
        RECT  0.054 43.152 0.138 43.176 ;
    END
  END d[299]
  PIN d[29]
    DIRECTION INPUT ;
    USE SIGNAL ;
    PORT
      LAYER M4 ;
        RECT  0.054 9.072 0.138 9.096 ;
    END
  END d[29]
  PIN d[2]
    DIRECTION INPUT ;
    USE SIGNAL ;
    PORT
      LAYER M4 ;
        RECT  0.054 5.664 0.138 5.688 ;
    END
  END d[2]
  PIN d[300]
    DIRECTION INPUT ;
    USE SIGNAL ;
    PORT
      LAYER M4 ;
        RECT  0.054 43.296 0.138 43.32 ;
    END
  END d[300]
  PIN d[301]
    DIRECTION INPUT ;
    USE SIGNAL ;
    PORT
      LAYER M4 ;
        RECT  0.054 43.392 0.138 43.416 ;
    END
  END d[301]
  PIN d[302]
    DIRECTION INPUT ;
    USE SIGNAL ;
    PORT
      LAYER M4 ;
        RECT  0.054 43.536 0.138 43.56 ;
    END
  END d[302]
  PIN d[303]
    DIRECTION INPUT ;
    USE SIGNAL ;
    PORT
      LAYER M4 ;
        RECT  0.054 43.68 0.138 43.704 ;
    END
  END d[303]
  PIN d[304]
    DIRECTION INPUT ;
    USE SIGNAL ;
    PORT
      LAYER M4 ;
        RECT  0.054 43.776 0.138 43.8 ;
    END
  END d[304]
  PIN d[305]
    DIRECTION INPUT ;
    USE SIGNAL ;
    PORT
      LAYER M4 ;
        RECT  0.054 43.92 0.138 43.944 ;
    END
  END d[305]
  PIN d[306]
    DIRECTION INPUT ;
    USE SIGNAL ;
    PORT
      LAYER M4 ;
        RECT  0.054 44.064 0.138 44.088 ;
    END
  END d[306]
  PIN d[307]
    DIRECTION INPUT ;
    USE SIGNAL ;
    PORT
      LAYER M4 ;
        RECT  0.054 44.16 0.138 44.184 ;
    END
  END d[307]
  PIN d[308]
    DIRECTION INPUT ;
    USE SIGNAL ;
    PORT
      LAYER M4 ;
        RECT  0.054 44.304 0.138 44.328 ;
    END
  END d[308]
  PIN d[309]
    DIRECTION INPUT ;
    USE SIGNAL ;
    PORT
      LAYER M4 ;
        RECT  0.054 44.4 0.138 44.424 ;
    END
  END d[309]
  PIN d[30]
    DIRECTION INPUT ;
    USE SIGNAL ;
    PORT
      LAYER M4 ;
        RECT  0.054 9.168 0.138 9.192 ;
    END
  END d[30]
  PIN d[310]
    DIRECTION INPUT ;
    USE SIGNAL ;
    PORT
      LAYER M4 ;
        RECT  0.054 44.544 0.138 44.568 ;
    END
  END d[310]
  PIN d[311]
    DIRECTION INPUT ;
    USE SIGNAL ;
    PORT
      LAYER M4 ;
        RECT  0.054 44.688 0.138 44.712 ;
    END
  END d[311]
  PIN d[312]
    DIRECTION INPUT ;
    USE SIGNAL ;
    PORT
      LAYER M4 ;
        RECT  0.054 44.784 0.138 44.808 ;
    END
  END d[312]
  PIN d[313]
    DIRECTION INPUT ;
    USE SIGNAL ;
    PORT
      LAYER M4 ;
        RECT  0.054 44.928 0.138 44.952 ;
    END
  END d[313]
  PIN d[314]
    DIRECTION INPUT ;
    USE SIGNAL ;
    PORT
      LAYER M4 ;
        RECT  0.054 45.072 0.138 45.096 ;
    END
  END d[314]
  PIN d[315]
    DIRECTION INPUT ;
    USE SIGNAL ;
    PORT
      LAYER M4 ;
        RECT  0.054 45.168 0.138 45.192 ;
    END
    PORT
      LAYER M4 ;
        RECT  0.025 45.168 0.108 45.192 ;
    END
  END d[315]
  PIN d[316]
    DIRECTION INPUT ;
    USE SIGNAL ;
    PORT
      LAYER M4 ;
        RECT  0.054 45.312 0.138 45.336 ;
    END
  END d[316]
  PIN d[317]
    DIRECTION INPUT ;
    USE SIGNAL ;
    PORT
      LAYER M4 ;
        RECT  0.054 45.408 0.138 45.432 ;
    END
  END d[317]
  PIN d[318]
    DIRECTION INPUT ;
    USE SIGNAL ;
    PORT
      LAYER M4 ;
        RECT  0.054 45.552 0.138 45.576 ;
    END
  END d[318]
  PIN d[319]
    DIRECTION INPUT ;
    USE SIGNAL ;
    PORT
      LAYER M4 ;
        RECT  0.054 45.696 0.138 45.72 ;
    END
  END d[319]
  PIN d[31]
    DIRECTION INPUT ;
    USE SIGNAL ;
    PORT
      LAYER M4 ;
        RECT  0.054 9.312 0.138 9.336 ;
    END
  END d[31]
  PIN d[320]
    DIRECTION INPUT ;
    USE SIGNAL ;
    PORT
      LAYER M4 ;
        RECT  0.054 45.792 0.138 45.816 ;
    END
  END d[320]
  PIN d[321]
    DIRECTION INPUT ;
    USE SIGNAL ;
    PORT
      LAYER M4 ;
        RECT  0.054 45.936 0.138 45.96 ;
    END
  END d[321]
  PIN d[322]
    DIRECTION INPUT ;
    USE SIGNAL ;
    PORT
      LAYER M4 ;
        RECT  0.054 46.08 0.138 46.104 ;
    END
  END d[322]
  PIN d[323]
    DIRECTION INPUT ;
    USE SIGNAL ;
    PORT
      LAYER M4 ;
        RECT  0.054 46.176 0.138 46.2 ;
    END
  END d[323]
  PIN d[324]
    DIRECTION INPUT ;
    USE SIGNAL ;
    PORT
      LAYER M4 ;
        RECT  0.054 46.32 0.138 46.344 ;
    END
  END d[324]
  PIN d[325]
    DIRECTION INPUT ;
    USE SIGNAL ;
    PORT
      LAYER M4 ;
        RECT  0.054 46.464 0.138 46.488 ;
    END
  END d[325]
  PIN d[326]
    DIRECTION INPUT ;
    USE SIGNAL ;
    PORT
      LAYER M4 ;
        RECT  0.054 46.56 0.138 46.584 ;
    END
    PORT
      LAYER M4 ;
        RECT  0.025 46.56 0.108 46.584 ;
    END
  END d[326]
  PIN d[327]
    DIRECTION INPUT ;
    USE SIGNAL ;
    PORT
      LAYER M4 ;
        RECT  0.054 46.704 0.138 46.728 ;
    END
  END d[327]
  PIN d[328]
    DIRECTION INPUT ;
    USE SIGNAL ;
    PORT
      LAYER M4 ;
        RECT  0.054 46.8 0.138 46.824 ;
    END
  END d[328]
  PIN d[329]
    DIRECTION INPUT ;
    USE SIGNAL ;
    PORT
      LAYER M4 ;
        RECT  0.054 46.944 0.138 46.968 ;
    END
  END d[329]
  PIN d[32]
    DIRECTION INPUT ;
    USE SIGNAL ;
    PORT
      LAYER M4 ;
        RECT  0.054 9.408 0.138 9.432 ;
    END
  END d[32]
  PIN d[330]
    DIRECTION INPUT ;
    USE SIGNAL ;
    PORT
      LAYER M4 ;
        RECT  0.054 47.088 0.138 47.112 ;
    END
  END d[330]
  PIN d[331]
    DIRECTION INPUT ;
    USE SIGNAL ;
    PORT
      LAYER M4 ;
        RECT  0.054 47.184 0.138 47.208 ;
    END
  END d[331]
  PIN d[332]
    DIRECTION INPUT ;
    USE SIGNAL ;
    PORT
      LAYER M4 ;
        RECT  0.054 47.328 0.138 47.352 ;
    END
  END d[332]
  PIN d[333]
    DIRECTION INPUT ;
    USE SIGNAL ;
    PORT
      LAYER M4 ;
        RECT  0.054 47.472 0.138 47.496 ;
    END
  END d[333]
  PIN d[334]
    DIRECTION INPUT ;
    USE SIGNAL ;
    PORT
      LAYER M4 ;
        RECT  0.054 47.568 0.138 47.592 ;
    END
  END d[334]
  PIN d[335]
    DIRECTION INPUT ;
    USE SIGNAL ;
    PORT
      LAYER M4 ;
        RECT  0.054 47.712 0.138 47.736 ;
    END
  END d[335]
  PIN d[336]
    DIRECTION INPUT ;
    USE SIGNAL ;
    PORT
      LAYER M4 ;
        RECT  0.054 47.808 0.138 47.832 ;
    END
  END d[336]
  PIN d[337]
    DIRECTION INPUT ;
    USE SIGNAL ;
    PORT
      LAYER M4 ;
        RECT  0.054 47.952 0.138 47.976 ;
    END
  END d[337]
  PIN d[338]
    DIRECTION INPUT ;
    USE SIGNAL ;
    PORT
      LAYER M4 ;
        RECT  0.054 48.096 0.138 48.12 ;
    END
  END d[338]
  PIN d[339]
    DIRECTION INPUT ;
    USE SIGNAL ;
    PORT
      LAYER M4 ;
        RECT  0.054 48.192 0.138 48.216 ;
    END
  END d[339]
  PIN d[33]
    DIRECTION INPUT ;
    USE SIGNAL ;
    PORT
      LAYER M4 ;
        RECT  0.054 9.552 0.138 9.576 ;
    END
  END d[33]
  PIN d[340]
    DIRECTION INPUT ;
    USE SIGNAL ;
    PORT
      LAYER M4 ;
        RECT  0.054 48.336 0.138 48.36 ;
    END
  END d[340]
  PIN d[341]
    DIRECTION INPUT ;
    USE SIGNAL ;
    PORT
      LAYER M4 ;
        RECT  0.054 48.48 0.138 48.504 ;
    END
  END d[341]
  PIN d[342]
    DIRECTION INPUT ;
    USE SIGNAL ;
    PORT
      LAYER M4 ;
        RECT  0.054 48.576 0.138 48.6 ;
    END
  END d[342]
  PIN d[343]
    DIRECTION INPUT ;
    USE SIGNAL ;
    PORT
      LAYER M4 ;
        RECT  0.054 48.72 0.138 48.744 ;
    END
  END d[343]
  PIN d[344]
    DIRECTION INPUT ;
    USE SIGNAL ;
    PORT
      LAYER M4 ;
        RECT  0.054 48.864 0.138 48.888 ;
    END
  END d[344]
  PIN d[345]
    DIRECTION INPUT ;
    USE SIGNAL ;
    PORT
      LAYER M4 ;
        RECT  0.054 48.96 0.138 48.984 ;
    END
  END d[345]
  PIN d[346]
    DIRECTION INPUT ;
    USE SIGNAL ;
    PORT
      LAYER M4 ;
        RECT  0.054 49.104 0.138 49.128 ;
    END
  END d[346]
  PIN d[347]
    DIRECTION INPUT ;
    USE SIGNAL ;
    PORT
      LAYER M4 ;
        RECT  0.054 49.2 0.138 49.224 ;
    END
  END d[347]
  PIN d[348]
    DIRECTION INPUT ;
    USE SIGNAL ;
    PORT
      LAYER M4 ;
        RECT  0.054 49.344 0.138 49.368 ;
    END
  END d[348]
  PIN d[349]
    DIRECTION INPUT ;
    USE SIGNAL ;
    PORT
      LAYER M4 ;
        RECT  0.054 49.488 0.138 49.512 ;
    END
  END d[349]
  PIN d[34]
    DIRECTION INPUT ;
    USE SIGNAL ;
    PORT
      LAYER M4 ;
        RECT  0.054 9.696 0.138 9.72 ;
    END
  END d[34]
  PIN d[350]
    DIRECTION INPUT ;
    USE SIGNAL ;
    PORT
      LAYER M4 ;
        RECT  0.054 49.584 0.138 49.608 ;
    END
  END d[350]
  PIN d[351]
    DIRECTION INPUT ;
    USE SIGNAL ;
    PORT
      LAYER M4 ;
        RECT  0.054 49.728 0.138 49.752 ;
    END
  END d[351]
  PIN d[352]
    DIRECTION INPUT ;
    USE SIGNAL ;
    PORT
      LAYER M4 ;
        RECT  0.054 49.872 0.138 49.896 ;
    END
  END d[352]
  PIN d[353]
    DIRECTION INPUT ;
    USE SIGNAL ;
    PORT
      LAYER M4 ;
        RECT  0.054 49.968 0.138 49.992 ;
    END
  END d[353]
  PIN d[354]
    DIRECTION INPUT ;
    USE SIGNAL ;
    PORT
      LAYER M4 ;
        RECT  0.054 50.112 0.138 50.136 ;
    END
  END d[354]
  PIN d[355]
    DIRECTION INPUT ;
    USE SIGNAL ;
    PORT
      LAYER M4 ;
        RECT  0.054 50.208 0.138 50.232 ;
    END
  END d[355]
  PIN d[356]
    DIRECTION INPUT ;
    USE SIGNAL ;
    PORT
      LAYER M4 ;
        RECT  0.054 50.352 0.138 50.376 ;
    END
  END d[356]
  PIN d[357]
    DIRECTION INPUT ;
    USE SIGNAL ;
    PORT
      LAYER M4 ;
        RECT  0.054 50.496 0.138 50.52 ;
    END
  END d[357]
  PIN d[358]
    DIRECTION INPUT ;
    USE SIGNAL ;
    PORT
      LAYER M4 ;
        RECT  0.054 50.592 0.138 50.616 ;
    END
  END d[358]
  PIN d[359]
    DIRECTION INPUT ;
    USE SIGNAL ;
    PORT
      LAYER M4 ;
        RECT  0.054 50.736 0.138 50.76 ;
    END
  END d[359]
  PIN d[35]
    DIRECTION INPUT ;
    USE SIGNAL ;
    PORT
      LAYER M4 ;
        RECT  0.054 9.792 0.138 9.816 ;
    END
  END d[35]
  PIN d[360]
    DIRECTION INPUT ;
    USE SIGNAL ;
    PORT
      LAYER M4 ;
        RECT  0.054 50.88 0.138 50.904 ;
    END
  END d[360]
  PIN d[361]
    DIRECTION INPUT ;
    USE SIGNAL ;
    PORT
      LAYER M4 ;
        RECT  0.054 50.976 0.138 51 ;
    END
  END d[361]
  PIN d[362]
    DIRECTION INPUT ;
    USE SIGNAL ;
    PORT
      LAYER M4 ;
        RECT  0.054 51.12 0.138 51.144 ;
    END
  END d[362]
  PIN d[363]
    DIRECTION INPUT ;
    USE SIGNAL ;
    PORT
      LAYER M4 ;
        RECT  0.054 51.264 0.138 51.288 ;
    END
  END d[363]
  PIN d[364]
    DIRECTION INPUT ;
    USE SIGNAL ;
    PORT
      LAYER M4 ;
        RECT  0.054 51.36 0.138 51.384 ;
    END
  END d[364]
  PIN d[365]
    DIRECTION INPUT ;
    USE SIGNAL ;
    PORT
      LAYER M4 ;
        RECT  0.054 51.504 0.138 51.528 ;
    END
  END d[365]
  PIN d[366]
    DIRECTION INPUT ;
    USE SIGNAL ;
    PORT
      LAYER M4 ;
        RECT  0.054 51.6 0.138 51.624 ;
    END
  END d[366]
  PIN d[367]
    DIRECTION INPUT ;
    USE SIGNAL ;
    PORT
      LAYER M4 ;
        RECT  0.054 51.744 0.138 51.768 ;
    END
  END d[367]
  PIN d[368]
    DIRECTION INPUT ;
    USE SIGNAL ;
    PORT
      LAYER M4 ;
        RECT  0.054 51.888 0.138 51.912 ;
    END
  END d[368]
  PIN d[369]
    DIRECTION INPUT ;
    USE SIGNAL ;
    PORT
      LAYER M4 ;
        RECT  0.054 51.984 0.138 52.008 ;
    END
    PORT
      LAYER M4 ;
        RECT  0.025 51.984 0.108 52.008 ;
    END
  END d[369]
  PIN d[36]
    DIRECTION INPUT ;
    USE SIGNAL ;
    PORT
      LAYER M4 ;
        RECT  0.054 9.936 0.138 9.96 ;
    END
  END d[36]
  PIN d[370]
    DIRECTION INPUT ;
    USE SIGNAL ;
    PORT
      LAYER M4 ;
        RECT  0.054 52.128 0.138 52.152 ;
    END
  END d[370]
  PIN d[371]
    DIRECTION INPUT ;
    USE SIGNAL ;
    PORT
      LAYER M4 ;
        RECT  0.054 52.272 0.138 52.296 ;
    END
  END d[371]
  PIN d[372]
    DIRECTION INPUT ;
    USE SIGNAL ;
    PORT
      LAYER M4 ;
        RECT  0.054 52.368 0.138 52.392 ;
    END
  END d[372]
  PIN d[373]
    DIRECTION INPUT ;
    USE SIGNAL ;
    PORT
      LAYER M4 ;
        RECT  0.054 52.512 0.138 52.536 ;
    END
  END d[373]
  PIN d[374]
    DIRECTION INPUT ;
    USE SIGNAL ;
    PORT
      LAYER M4 ;
        RECT  0.054 52.608 0.138 52.632 ;
    END
  END d[374]
  PIN d[375]
    DIRECTION INPUT ;
    USE SIGNAL ;
    PORT
      LAYER M4 ;
        RECT  0.054 52.752 0.138 52.776 ;
    END
  END d[375]
  PIN d[376]
    DIRECTION INPUT ;
    USE SIGNAL ;
    PORT
      LAYER M4 ;
        RECT  0.054 52.896 0.138 52.92 ;
    END
  END d[376]
  PIN d[377]
    DIRECTION INPUT ;
    USE SIGNAL ;
    PORT
      LAYER M4 ;
        RECT  0.054 52.992 0.138 53.016 ;
    END
  END d[377]
  PIN d[378]
    DIRECTION INPUT ;
    USE SIGNAL ;
    PORT
      LAYER M4 ;
        RECT  0.054 53.136 0.138 53.16 ;
    END
  END d[378]
  PIN d[379]
    DIRECTION INPUT ;
    USE SIGNAL ;
    PORT
      LAYER M4 ;
        RECT  0.054 53.28 0.138 53.304 ;
    END
    PORT
      LAYER M4 ;
        RECT  0.025 53.28 0.108 53.304 ;
    END
  END d[379]
  PIN d[37]
    DIRECTION INPUT ;
    USE SIGNAL ;
    PORT
      LAYER M4 ;
        RECT  0.054 10.08 0.138 10.104 ;
    END
  END d[37]
  PIN d[380]
    DIRECTION INPUT ;
    USE SIGNAL ;
    PORT
      LAYER M4 ;
        RECT  0.054 53.376 0.138 53.4 ;
    END
  END d[380]
  PIN d[381]
    DIRECTION INPUT ;
    USE SIGNAL ;
    PORT
      LAYER M4 ;
        RECT  0.054 53.52 0.138 53.544 ;
    END
  END d[381]
  PIN d[382]
    DIRECTION INPUT ;
    USE SIGNAL ;
    PORT
      LAYER M4 ;
        RECT  0.054 53.664 0.138 53.688 ;
    END
  END d[382]
  PIN d[383]
    DIRECTION INPUT ;
    USE SIGNAL ;
    PORT
      LAYER M4 ;
        RECT  0.054 53.76 0.138 53.784 ;
    END
  END d[383]
  PIN d[384]
    DIRECTION INPUT ;
    USE SIGNAL ;
    PORT
      LAYER M4 ;
        RECT  0.054 53.904 0.138 53.928 ;
    END
  END d[384]
  PIN d[385]
    DIRECTION INPUT ;
    USE SIGNAL ;
    PORT
      LAYER M4 ;
        RECT  0.054 54 0.138 54.024 ;
    END
  END d[385]
  PIN d[386]
    DIRECTION INPUT ;
    USE SIGNAL ;
    PORT
      LAYER M4 ;
        RECT  0.054 54.144 0.138 54.168 ;
    END
  END d[386]
  PIN d[387]
    DIRECTION INPUT ;
    USE SIGNAL ;
    PORT
      LAYER M4 ;
        RECT  0.054 54.288 0.138 54.312 ;
    END
  END d[387]
  PIN d[388]
    DIRECTION INPUT ;
    USE SIGNAL ;
    PORT
      LAYER M4 ;
        RECT  0.054 54.384 0.138 54.408 ;
    END
  END d[388]
  PIN d[389]
    DIRECTION INPUT ;
    USE SIGNAL ;
    PORT
      LAYER M4 ;
        RECT  0.054 54.528 0.138 54.552 ;
    END
  END d[389]
  PIN d[38]
    DIRECTION INPUT ;
    USE SIGNAL ;
    PORT
      LAYER M4 ;
        RECT  0.054 10.176 0.138 10.2 ;
    END
  END d[38]
  PIN d[390]
    DIRECTION INPUT ;
    USE SIGNAL ;
    PORT
      LAYER M4 ;
        RECT  0.054 54.672 0.138 54.696 ;
    END
  END d[390]
  PIN d[391]
    DIRECTION INPUT ;
    USE SIGNAL ;
    PORT
      LAYER M4 ;
        RECT  0.054 54.768 0.138 54.792 ;
    END
  END d[391]
  PIN d[392]
    DIRECTION INPUT ;
    USE SIGNAL ;
    PORT
      LAYER M4 ;
        RECT  0.054 54.912 0.138 54.936 ;
    END
  END d[392]
  PIN d[393]
    DIRECTION INPUT ;
    USE SIGNAL ;
    PORT
      LAYER M4 ;
        RECT  0.054 55.008 0.138 55.032 ;
    END
  END d[393]
  PIN d[394]
    DIRECTION INPUT ;
    USE SIGNAL ;
    PORT
      LAYER M4 ;
        RECT  0.054 55.152 0.138 55.176 ;
    END
  END d[394]
  PIN d[395]
    DIRECTION INPUT ;
    USE SIGNAL ;
    PORT
      LAYER M4 ;
        RECT  0.054 55.296 0.138 55.32 ;
    END
  END d[395]
  PIN d[396]
    DIRECTION INPUT ;
    USE SIGNAL ;
    PORT
      LAYER M4 ;
        RECT  0.054 55.392 0.138 55.416 ;
    END
  END d[396]
  PIN d[397]
    DIRECTION INPUT ;
    USE SIGNAL ;
    PORT
      LAYER M4 ;
        RECT  0.054 55.536 0.138 55.56 ;
    END
  END d[397]
  PIN d[398]
    DIRECTION INPUT ;
    USE SIGNAL ;
    PORT
      LAYER M4 ;
        RECT  0.054 55.68 0.138 55.704 ;
    END
  END d[398]
  PIN d[399]
    DIRECTION INPUT ;
    USE SIGNAL ;
    PORT
      LAYER M4 ;
        RECT  0.054 55.776 0.138 55.8 ;
    END
  END d[399]
  PIN d[39]
    DIRECTION INPUT ;
    USE SIGNAL ;
    PORT
      LAYER M4 ;
        RECT  0.054 10.32 0.138 10.344 ;
    END
  END d[39]
  PIN d[3]
    DIRECTION INPUT ;
    USE SIGNAL ;
    PORT
      LAYER M4 ;
        RECT  0.054 5.76 0.138 5.784 ;
    END
  END d[3]
  PIN d[400]
    DIRECTION INPUT ;
    USE SIGNAL ;
    PORT
      LAYER M4 ;
        RECT  0.054 55.92 0.138 55.944 ;
    END
  END d[400]
  PIN d[401]
    DIRECTION INPUT ;
    USE SIGNAL ;
    PORT
      LAYER M4 ;
        RECT  0.054 56.064 0.138 56.088 ;
    END
  END d[401]
  PIN d[402]
    DIRECTION INPUT ;
    USE SIGNAL ;
    PORT
      LAYER M4 ;
        RECT  0.054 56.16 0.138 56.184 ;
    END
  END d[402]
  PIN d[403]
    DIRECTION INPUT ;
    USE SIGNAL ;
    PORT
      LAYER M4 ;
        RECT  0.054 56.304 0.138 56.328 ;
    END
  END d[403]
  PIN d[404]
    DIRECTION INPUT ;
    USE SIGNAL ;
    PORT
      LAYER M4 ;
        RECT  0.054 56.4 0.138 56.424 ;
    END
  END d[404]
  PIN d[405]
    DIRECTION INPUT ;
    USE SIGNAL ;
    PORT
      LAYER M4 ;
        RECT  0.054 56.544 0.138 56.568 ;
    END
  END d[405]
  PIN d[406]
    DIRECTION INPUT ;
    USE SIGNAL ;
    PORT
      LAYER M4 ;
        RECT  0.054 56.688 0.138 56.712 ;
    END
  END d[406]
  PIN d[407]
    DIRECTION INPUT ;
    USE SIGNAL ;
    PORT
      LAYER M4 ;
        RECT  0.054 56.784 0.138 56.808 ;
    END
  END d[407]
  PIN d[408]
    DIRECTION INPUT ;
    USE SIGNAL ;
    PORT
      LAYER M4 ;
        RECT  0.054 56.928 0.138 56.952 ;
    END
  END d[408]
  PIN d[409]
    DIRECTION INPUT ;
    USE SIGNAL ;
    PORT
      LAYER M4 ;
        RECT  0.054 57.072 0.138 57.096 ;
    END
  END d[409]
  PIN d[40]
    DIRECTION INPUT ;
    USE SIGNAL ;
    PORT
      LAYER M4 ;
        RECT  0.054 10.464 0.138 10.488 ;
    END
  END d[40]
  PIN d[410]
    DIRECTION INPUT ;
    USE SIGNAL ;
    PORT
      LAYER M4 ;
        RECT  0.054 57.168 0.138 57.192 ;
    END
  END d[410]
  PIN d[411]
    DIRECTION INPUT ;
    USE SIGNAL ;
    PORT
      LAYER M4 ;
        RECT  0.054 57.312 0.138 57.336 ;
    END
  END d[411]
  PIN d[412]
    DIRECTION INPUT ;
    USE SIGNAL ;
    PORT
      LAYER M4 ;
        RECT  0.054 57.408 0.138 57.432 ;
    END
  END d[412]
  PIN d[413]
    DIRECTION INPUT ;
    USE SIGNAL ;
    PORT
      LAYER M4 ;
        RECT  0.054 57.552 0.138 57.576 ;
    END
  END d[413]
  PIN d[414]
    DIRECTION INPUT ;
    USE SIGNAL ;
    PORT
      LAYER M4 ;
        RECT  0.054 57.696 0.138 57.72 ;
    END
  END d[414]
  PIN d[415]
    DIRECTION INPUT ;
    USE SIGNAL ;
    PORT
      LAYER M4 ;
        RECT  0.054 57.792 0.138 57.816 ;
    END
  END d[415]
  PIN d[416]
    DIRECTION INPUT ;
    USE SIGNAL ;
    PORT
      LAYER M4 ;
        RECT  0.054 57.936 0.138 57.96 ;
    END
  END d[416]
  PIN d[417]
    DIRECTION INPUT ;
    USE SIGNAL ;
    PORT
      LAYER M4 ;
        RECT  0.054 58.08 0.138 58.104 ;
    END
  END d[417]
  PIN d[418]
    DIRECTION INPUT ;
    USE SIGNAL ;
    PORT
      LAYER M4 ;
        RECT  0.054 58.176 0.138 58.2 ;
    END
  END d[418]
  PIN d[419]
    DIRECTION INPUT ;
    USE SIGNAL ;
    PORT
      LAYER M4 ;
        RECT  0.054 58.32 0.138 58.344 ;
    END
  END d[419]
  PIN d[41]
    DIRECTION INPUT ;
    USE SIGNAL ;
    PORT
      LAYER M4 ;
        RECT  0.054 10.56 0.138 10.584 ;
    END
  END d[41]
  PIN d[420]
    DIRECTION INPUT ;
    USE SIGNAL ;
    PORT
      LAYER M4 ;
        RECT  0.054 58.464 0.138 58.488 ;
    END
  END d[420]
  PIN d[421]
    DIRECTION INPUT ;
    USE SIGNAL ;
    PORT
      LAYER M4 ;
        RECT  0.054 58.56 0.138 58.584 ;
    END
  END d[421]
  PIN d[422]
    DIRECTION INPUT ;
    USE SIGNAL ;
    PORT
      LAYER M4 ;
        RECT  0.054 58.704 0.138 58.728 ;
    END
  END d[422]
  PIN d[423]
    DIRECTION INPUT ;
    USE SIGNAL ;
    PORT
      LAYER M4 ;
        RECT  0.054 58.8 0.138 58.824 ;
    END
  END d[423]
  PIN d[424]
    DIRECTION INPUT ;
    USE SIGNAL ;
    PORT
      LAYER M4 ;
        RECT  0.054 58.944 0.138 58.968 ;
    END
  END d[424]
  PIN d[425]
    DIRECTION INPUT ;
    USE SIGNAL ;
    PORT
      LAYER M4 ;
        RECT  0.054 59.088 0.138 59.112 ;
    END
  END d[425]
  PIN d[426]
    DIRECTION INPUT ;
    USE SIGNAL ;
    PORT
      LAYER M4 ;
        RECT  0.054 59.184 0.138 59.208 ;
    END
  END d[426]
  PIN d[427]
    DIRECTION INPUT ;
    USE SIGNAL ;
    PORT
      LAYER M4 ;
        RECT  0.054 59.328 0.138 59.352 ;
    END
  END d[427]
  PIN d[428]
    DIRECTION INPUT ;
    USE SIGNAL ;
    PORT
      LAYER M4 ;
        RECT  0.054 59.472 0.138 59.496 ;
    END
  END d[428]
  PIN d[429]
    DIRECTION INPUT ;
    USE SIGNAL ;
    PORT
      LAYER M4 ;
        RECT  0.054 59.568 0.138 59.592 ;
    END
  END d[429]
  PIN d[42]
    DIRECTION INPUT ;
    USE SIGNAL ;
    PORT
      LAYER M4 ;
        RECT  0.054 10.704 0.138 10.728 ;
    END
  END d[42]
  PIN d[430]
    DIRECTION INPUT ;
    USE SIGNAL ;
    PORT
      LAYER M4 ;
        RECT  0.054 59.712 0.138 59.736 ;
    END
  END d[430]
  PIN d[431]
    DIRECTION INPUT ;
    USE SIGNAL ;
    PORT
      LAYER M4 ;
        RECT  0.054 59.808 0.138 59.832 ;
    END
  END d[431]
  PIN d[432]
    DIRECTION INPUT ;
    USE SIGNAL ;
    PORT
      LAYER M4 ;
        RECT  0.054 59.952 0.138 59.976 ;
    END
  END d[432]
  PIN d[433]
    DIRECTION INPUT ;
    USE SIGNAL ;
    PORT
      LAYER M4 ;
        RECT  0.054 60.096 0.138 60.12 ;
    END
  END d[433]
  PIN d[434]
    DIRECTION INPUT ;
    USE SIGNAL ;
    PORT
      LAYER M4 ;
        RECT  0.054 60.192 0.138 60.216 ;
    END
  END d[434]
  PIN d[435]
    DIRECTION INPUT ;
    USE SIGNAL ;
    PORT
      LAYER M4 ;
        RECT  0.054 60.336 0.138 60.36 ;
    END
  END d[435]
  PIN d[436]
    DIRECTION INPUT ;
    USE SIGNAL ;
    PORT
      LAYER M4 ;
        RECT  0.054 60.48 0.138 60.504 ;
    END
  END d[436]
  PIN d[437]
    DIRECTION INPUT ;
    USE SIGNAL ;
    PORT
      LAYER M4 ;
        RECT  0.054 60.576 0.138 60.6 ;
    END
  END d[437]
  PIN d[438]
    DIRECTION INPUT ;
    USE SIGNAL ;
    PORT
      LAYER M4 ;
        RECT  0.054 60.72 0.138 60.744 ;
    END
  END d[438]
  PIN d[439]
    DIRECTION INPUT ;
    USE SIGNAL ;
    PORT
      LAYER M4 ;
        RECT  0.054 60.864 0.138 60.888 ;
    END
  END d[439]
  PIN d[43]
    DIRECTION INPUT ;
    USE SIGNAL ;
    PORT
      LAYER M4 ;
        RECT  0.054 10.8 0.138 10.824 ;
    END
  END d[43]
  PIN d[440]
    DIRECTION INPUT ;
    USE SIGNAL ;
    PORT
      LAYER M4 ;
        RECT  0.054 60.96 0.138 60.984 ;
    END
  END d[440]
  PIN d[441]
    DIRECTION INPUT ;
    USE SIGNAL ;
    PORT
      LAYER M4 ;
        RECT  0.054 61.104 0.138 61.128 ;
    END
  END d[441]
  PIN d[442]
    DIRECTION INPUT ;
    USE SIGNAL ;
    PORT
      LAYER M4 ;
        RECT  0.054 61.2 0.138 61.224 ;
    END
  END d[442]
  PIN d[443]
    DIRECTION INPUT ;
    USE SIGNAL ;
    PORT
      LAYER M4 ;
        RECT  0.054 61.344 0.138 61.368 ;
    END
  END d[443]
  PIN d[444]
    DIRECTION INPUT ;
    USE SIGNAL ;
    PORT
      LAYER M4 ;
        RECT  0.054 61.488 0.138 61.512 ;
    END
  END d[444]
  PIN d[445]
    DIRECTION INPUT ;
    USE SIGNAL ;
    PORT
      LAYER M4 ;
        RECT  0.054 61.584 0.138 61.608 ;
    END
  END d[445]
  PIN d[446]
    DIRECTION INPUT ;
    USE SIGNAL ;
    PORT
      LAYER M4 ;
        RECT  0.054 61.728 0.138 61.752 ;
    END
  END d[446]
  PIN d[447]
    DIRECTION INPUT ;
    USE SIGNAL ;
    PORT
      LAYER M4 ;
        RECT  0.054 61.872 0.138 61.896 ;
    END
  END d[447]
  PIN d[448]
    DIRECTION INPUT ;
    USE SIGNAL ;
    PORT
      LAYER M4 ;
        RECT  0.054 61.968 0.138 61.992 ;
    END
  END d[448]
  PIN d[449]
    DIRECTION INPUT ;
    USE SIGNAL ;
    PORT
      LAYER M4 ;
        RECT  0.054 62.112 0.138 62.136 ;
    END
  END d[449]
  PIN d[44]
    DIRECTION INPUT ;
    USE SIGNAL ;
    PORT
      LAYER M4 ;
        RECT  0.054 10.944 0.138 10.968 ;
    END
  END d[44]
  PIN d[450]
    DIRECTION INPUT ;
    USE SIGNAL ;
    PORT
      LAYER M4 ;
        RECT  0.054 62.208 0.138 62.232 ;
    END
  END d[450]
  PIN d[451]
    DIRECTION INPUT ;
    USE SIGNAL ;
    PORT
      LAYER M4 ;
        RECT  0.054 62.352 0.138 62.376 ;
    END
  END d[451]
  PIN d[452]
    DIRECTION INPUT ;
    USE SIGNAL ;
    PORT
      LAYER M4 ;
        RECT  0.054 62.496 0.138 62.52 ;
    END
  END d[452]
  PIN d[453]
    DIRECTION INPUT ;
    USE SIGNAL ;
    PORT
      LAYER M4 ;
        RECT  0.054 62.592 0.138 62.616 ;
    END
  END d[453]
  PIN d[454]
    DIRECTION INPUT ;
    USE SIGNAL ;
    PORT
      LAYER M4 ;
        RECT  0.054 62.736 0.138 62.76 ;
    END
  END d[454]
  PIN d[455]
    DIRECTION INPUT ;
    USE SIGNAL ;
    PORT
      LAYER M4 ;
        RECT  0.054 62.88 0.138 62.904 ;
    END
  END d[455]
  PIN d[456]
    DIRECTION INPUT ;
    USE SIGNAL ;
    PORT
      LAYER M4 ;
        RECT  0.054 62.976 0.138 63 ;
    END
  END d[456]
  PIN d[457]
    DIRECTION INPUT ;
    USE SIGNAL ;
    PORT
      LAYER M4 ;
        RECT  0.054 63.12 0.138 63.144 ;
    END
  END d[457]
  PIN d[458]
    DIRECTION INPUT ;
    USE SIGNAL ;
    PORT
      LAYER M4 ;
        RECT  0.054 63.264 0.138 63.288 ;
    END
  END d[458]
  PIN d[459]
    DIRECTION INPUT ;
    USE SIGNAL ;
    PORT
      LAYER M4 ;
        RECT  0.054 63.36 0.138 63.384 ;
    END
  END d[459]
  PIN d[45]
    DIRECTION INPUT ;
    USE SIGNAL ;
    PORT
      LAYER M4 ;
        RECT  0.054 11.088 0.138 11.112 ;
    END
  END d[45]
  PIN d[460]
    DIRECTION INPUT ;
    USE SIGNAL ;
    PORT
      LAYER M4 ;
        RECT  0.054 63.504 0.138 63.528 ;
    END
  END d[460]
  PIN d[461]
    DIRECTION INPUT ;
    USE SIGNAL ;
    PORT
      LAYER M4 ;
        RECT  0.054 63.6 0.138 63.624 ;
    END
  END d[461]
  PIN d[462]
    DIRECTION INPUT ;
    USE SIGNAL ;
    PORT
      LAYER M4 ;
        RECT  0.054 63.744 0.138 63.768 ;
    END
  END d[462]
  PIN d[463]
    DIRECTION INPUT ;
    USE SIGNAL ;
    PORT
      LAYER M4 ;
        RECT  0.054 63.888 0.138 63.912 ;
    END
  END d[463]
  PIN d[464]
    DIRECTION INPUT ;
    USE SIGNAL ;
    PORT
      LAYER M4 ;
        RECT  0.054 63.984 0.138 64.008 ;
    END
  END d[464]
  PIN d[465]
    DIRECTION INPUT ;
    USE SIGNAL ;
    PORT
      LAYER M4 ;
        RECT  0.054 64.128 0.138 64.152 ;
    END
  END d[465]
  PIN d[466]
    DIRECTION INPUT ;
    USE SIGNAL ;
    PORT
      LAYER M4 ;
        RECT  0.054 64.272 0.138 64.296 ;
    END
  END d[466]
  PIN d[467]
    DIRECTION INPUT ;
    USE SIGNAL ;
    PORT
      LAYER M4 ;
        RECT  0.054 64.368 0.138 64.392 ;
    END
  END d[467]
  PIN d[468]
    DIRECTION INPUT ;
    USE SIGNAL ;
    PORT
      LAYER M4 ;
        RECT  0.054 64.512 0.138 64.536 ;
    END
  END d[468]
  PIN d[469]
    DIRECTION INPUT ;
    USE SIGNAL ;
    PORT
      LAYER M4 ;
        RECT  0.054 64.608 0.138 64.632 ;
    END
  END d[469]
  PIN d[46]
    DIRECTION INPUT ;
    USE SIGNAL ;
    PORT
      LAYER M4 ;
        RECT  0.054 11.184 0.138 11.208 ;
    END
  END d[46]
  PIN d[470]
    DIRECTION INPUT ;
    USE SIGNAL ;
    PORT
      LAYER M4 ;
        RECT  0.054 64.752 0.138 64.776 ;
    END
  END d[470]
  PIN d[471]
    DIRECTION INPUT ;
    USE SIGNAL ;
    PORT
      LAYER M4 ;
        RECT  0.054 64.896 0.138 64.92 ;
    END
  END d[471]
  PIN d[472]
    DIRECTION INPUT ;
    USE SIGNAL ;
    PORT
      LAYER M4 ;
        RECT  0.054 64.992 0.138 65.016 ;
    END
  END d[472]
  PIN d[473]
    DIRECTION INPUT ;
    USE SIGNAL ;
    PORT
      LAYER M4 ;
        RECT  0.054 65.136 0.138 65.16 ;
    END
  END d[473]
  PIN d[474]
    DIRECTION INPUT ;
    USE SIGNAL ;
    PORT
      LAYER M4 ;
        RECT  0.054 65.28 0.138 65.304 ;
    END
  END d[474]
  PIN d[475]
    DIRECTION INPUT ;
    USE SIGNAL ;
    PORT
      LAYER M4 ;
        RECT  0.054 65.376 0.138 65.4 ;
    END
  END d[475]
  PIN d[476]
    DIRECTION INPUT ;
    USE SIGNAL ;
    PORT
      LAYER M4 ;
        RECT  0.054 65.52 0.138 65.544 ;
    END
  END d[476]
  PIN d[477]
    DIRECTION INPUT ;
    USE SIGNAL ;
    PORT
      LAYER M4 ;
        RECT  0.054 65.664 0.138 65.688 ;
    END
  END d[477]
  PIN d[478]
    DIRECTION INPUT ;
    USE SIGNAL ;
    PORT
      LAYER M4 ;
        RECT  0.054 65.76 0.138 65.784 ;
    END
  END d[478]
  PIN d[479]
    DIRECTION INPUT ;
    USE SIGNAL ;
    PORT
      LAYER M4 ;
        RECT  0.054 65.904 0.138 65.928 ;
    END
  END d[479]
  PIN d[47]
    DIRECTION INPUT ;
    USE SIGNAL ;
    PORT
      LAYER M4 ;
        RECT  0.054 11.328 0.138 11.352 ;
    END
  END d[47]
  PIN d[480]
    DIRECTION INPUT ;
    USE SIGNAL ;
    PORT
      LAYER M4 ;
        RECT  0.054 66 0.138 66.024 ;
    END
  END d[480]
  PIN d[481]
    DIRECTION INPUT ;
    USE SIGNAL ;
    PORT
      LAYER M4 ;
        RECT  0.054 66.144 0.138 66.168 ;
    END
  END d[481]
  PIN d[482]
    DIRECTION INPUT ;
    USE SIGNAL ;
    PORT
      LAYER M4 ;
        RECT  0.054 66.288 0.138 66.312 ;
    END
  END d[482]
  PIN d[483]
    DIRECTION INPUT ;
    USE SIGNAL ;
    PORT
      LAYER M4 ;
        RECT  0.054 66.384 0.138 66.408 ;
    END
  END d[483]
  PIN d[484]
    DIRECTION INPUT ;
    USE SIGNAL ;
    PORT
      LAYER M4 ;
        RECT  0.054 66.528 0.138 66.552 ;
    END
  END d[484]
  PIN d[485]
    DIRECTION INPUT ;
    USE SIGNAL ;
    PORT
      LAYER M4 ;
        RECT  0.054 66.672 0.138 66.696 ;
    END
  END d[485]
  PIN d[486]
    DIRECTION INPUT ;
    USE SIGNAL ;
    PORT
      LAYER M4 ;
        RECT  0.054 66.768 0.138 66.792 ;
    END
  END d[486]
  PIN d[487]
    DIRECTION INPUT ;
    USE SIGNAL ;
    PORT
      LAYER M4 ;
        RECT  0.054 66.912 0.138 66.936 ;
    END
  END d[487]
  PIN d[488]
    DIRECTION INPUT ;
    USE SIGNAL ;
    PORT
      LAYER M4 ;
        RECT  0.054 67.008 0.138 67.032 ;
    END
  END d[488]
  PIN d[489]
    DIRECTION INPUT ;
    USE SIGNAL ;
    PORT
      LAYER M4 ;
        RECT  0.054 67.152 0.138 67.176 ;
    END
  END d[489]
  PIN d[48]
    DIRECTION INPUT ;
    USE SIGNAL ;
    PORT
      LAYER M4 ;
        RECT  0.054 11.472 0.138 11.496 ;
    END
  END d[48]
  PIN d[490]
    DIRECTION INPUT ;
    USE SIGNAL ;
    PORT
      LAYER M4 ;
        RECT  0.054 67.296 0.138 67.32 ;
    END
  END d[490]
  PIN d[491]
    DIRECTION INPUT ;
    USE SIGNAL ;
    PORT
      LAYER M4 ;
        RECT  0.054 67.392 0.138 67.416 ;
    END
  END d[491]
  PIN d[492]
    DIRECTION INPUT ;
    USE SIGNAL ;
    PORT
      LAYER M4 ;
        RECT  0.054 67.536 0.138 67.56 ;
    END
  END d[492]
  PIN d[493]
    DIRECTION INPUT ;
    USE SIGNAL ;
    PORT
      LAYER M4 ;
        RECT  0.054 67.68 0.138 67.704 ;
    END
  END d[493]
  PIN d[494]
    DIRECTION INPUT ;
    USE SIGNAL ;
    PORT
      LAYER M4 ;
        RECT  0.054 67.776 0.138 67.8 ;
    END
  END d[494]
  PIN d[495]
    DIRECTION INPUT ;
    USE SIGNAL ;
    PORT
      LAYER M4 ;
        RECT  0.054 67.92 0.138 67.944 ;
    END
  END d[495]
  PIN d[496]
    DIRECTION INPUT ;
    USE SIGNAL ;
    PORT
      LAYER M4 ;
        RECT  0.054 68.064 0.138 68.088 ;
    END
  END d[496]
  PIN d[497]
    DIRECTION INPUT ;
    USE SIGNAL ;
    PORT
      LAYER M4 ;
        RECT  0.054 68.16 0.138 68.184 ;
    END
  END d[497]
  PIN d[498]
    DIRECTION INPUT ;
    USE SIGNAL ;
    PORT
      LAYER M4 ;
        RECT  0.054 68.304 0.138 68.328 ;
    END
  END d[498]
  PIN d[499]
    DIRECTION INPUT ;
    USE SIGNAL ;
    PORT
      LAYER M4 ;
        RECT  0.054 68.4 0.138 68.424 ;
    END
  END d[499]
  PIN d[49]
    DIRECTION INPUT ;
    USE SIGNAL ;
    PORT
      LAYER M4 ;
        RECT  0.054 11.568 0.138 11.592 ;
    END
  END d[49]
  PIN d[4]
    DIRECTION INPUT ;
    USE SIGNAL ;
    PORT
      LAYER M4 ;
        RECT  0.054 5.904 0.138 5.928 ;
    END
  END d[4]
  PIN d[500]
    DIRECTION INPUT ;
    USE SIGNAL ;
    PORT
      LAYER M4 ;
        RECT  0.054 68.544 0.138 68.568 ;
    END
  END d[500]
  PIN d[501]
    DIRECTION INPUT ;
    USE SIGNAL ;
    PORT
      LAYER M4 ;
        RECT  0.054 68.688 0.138 68.712 ;
    END
  END d[501]
  PIN d[502]
    DIRECTION INPUT ;
    USE SIGNAL ;
    PORT
      LAYER M4 ;
        RECT  0.054 68.784 0.138 68.808 ;
    END
  END d[502]
  PIN d[503]
    DIRECTION INPUT ;
    USE SIGNAL ;
    PORT
      LAYER M4 ;
        RECT  0.054 68.928 0.138 68.952 ;
    END
  END d[503]
  PIN d[504]
    DIRECTION INPUT ;
    USE SIGNAL ;
    PORT
      LAYER M4 ;
        RECT  0.054 69.072 0.138 69.096 ;
    END
  END d[504]
  PIN d[505]
    DIRECTION INPUT ;
    USE SIGNAL ;
    PORT
      LAYER M4 ;
        RECT  0.054 69.168 0.138 69.192 ;
    END
  END d[505]
  PIN d[506]
    DIRECTION INPUT ;
    USE SIGNAL ;
    PORT
      LAYER M4 ;
        RECT  0.054 69.312 0.138 69.336 ;
    END
  END d[506]
  PIN d[507]
    DIRECTION INPUT ;
    USE SIGNAL ;
    PORT
      LAYER M4 ;
        RECT  0.054 69.408 0.138 69.432 ;
    END
  END d[507]
  PIN d[508]
    DIRECTION INPUT ;
    USE SIGNAL ;
    PORT
      LAYER M4 ;
        RECT  0.054 69.552 0.138 69.576 ;
    END
  END d[508]
  PIN d[509]
    DIRECTION INPUT ;
    USE SIGNAL ;
    PORT
      LAYER M4 ;
        RECT  0.054 69.696 0.138 69.72 ;
    END
  END d[509]
  PIN d[50]
    DIRECTION INPUT ;
    USE SIGNAL ;
    PORT
      LAYER M4 ;
        RECT  0.054 11.712 0.138 11.736 ;
    END
  END d[50]
  PIN d[510]
    DIRECTION INPUT ;
    USE SIGNAL ;
    PORT
      LAYER M4 ;
        RECT  0.054 69.792 0.138 69.816 ;
    END
  END d[510]
  PIN d[511]
    DIRECTION INPUT ;
    USE SIGNAL ;
    PORT
      LAYER M4 ;
        RECT  0.054 69.936 0.138 69.96 ;
    END
  END d[511]
  PIN d[51]
    DIRECTION INPUT ;
    USE SIGNAL ;
    PORT
      LAYER M4 ;
        RECT  0.054 11.808 0.138 11.832 ;
    END
  END d[51]
  PIN d[52]
    DIRECTION INPUT ;
    USE SIGNAL ;
    PORT
      LAYER M4 ;
        RECT  0.054 11.952 0.138 11.976 ;
    END
  END d[52]
  PIN d[53]
    DIRECTION INPUT ;
    USE SIGNAL ;
    PORT
      LAYER M4 ;
        RECT  0.054 12.096 0.138 12.12 ;
    END
  END d[53]
  PIN d[54]
    DIRECTION INPUT ;
    USE SIGNAL ;
    PORT
      LAYER M4 ;
        RECT  0.054 12.192 0.138 12.216 ;
    END
  END d[54]
  PIN d[55]
    DIRECTION INPUT ;
    USE SIGNAL ;
    PORT
      LAYER M4 ;
        RECT  0.054 12.336 0.138 12.36 ;
    END
  END d[55]
  PIN d[56]
    DIRECTION INPUT ;
    USE SIGNAL ;
    PORT
      LAYER M4 ;
        RECT  0.054 12.48 0.138 12.504 ;
    END
  END d[56]
  PIN d[57]
    DIRECTION INPUT ;
    USE SIGNAL ;
    PORT
      LAYER M4 ;
        RECT  0.054 12.576 0.138 12.6 ;
    END
  END d[57]
  PIN d[58]
    DIRECTION INPUT ;
    USE SIGNAL ;
    PORT
      LAYER M4 ;
        RECT  0.054 12.72 0.138 12.744 ;
    END
  END d[58]
  PIN d[59]
    DIRECTION INPUT ;
    USE SIGNAL ;
    PORT
      LAYER M4 ;
        RECT  0.054 12.864 0.138 12.888 ;
    END
  END d[59]
  PIN d[5]
    DIRECTION INPUT ;
    USE SIGNAL ;
    PORT
      LAYER M4 ;
        RECT  0.054 6 0.138 6.024 ;
    END
  END d[5]
  PIN d[60]
    DIRECTION INPUT ;
    USE SIGNAL ;
    PORT
      LAYER M4 ;
        RECT  0.054 12.96 0.138 12.984 ;
    END
  END d[60]
  PIN d[61]
    DIRECTION INPUT ;
    USE SIGNAL ;
    PORT
      LAYER M4 ;
        RECT  0.054 13.104 0.138 13.128 ;
    END
  END d[61]
  PIN d[62]
    DIRECTION INPUT ;
    USE SIGNAL ;
    PORT
      LAYER M4 ;
        RECT  0.054 13.2 0.138 13.224 ;
    END
  END d[62]
  PIN d[63]
    DIRECTION INPUT ;
    USE SIGNAL ;
    PORT
      LAYER M4 ;
        RECT  0.054 13.344 0.138 13.368 ;
    END
  END d[63]
  PIN d[64]
    DIRECTION INPUT ;
    USE SIGNAL ;
    PORT
      LAYER M4 ;
        RECT  0.054 13.488 0.138 13.512 ;
    END
  END d[64]
  PIN d[65]
    DIRECTION INPUT ;
    USE SIGNAL ;
    PORT
      LAYER M4 ;
        RECT  0.054 13.584 0.138 13.608 ;
    END
  END d[65]
  PIN d[66]
    DIRECTION INPUT ;
    USE SIGNAL ;
    PORT
      LAYER M4 ;
        RECT  0.054 13.728 0.138 13.752 ;
    END
  END d[66]
  PIN d[67]
    DIRECTION INPUT ;
    USE SIGNAL ;
    PORT
      LAYER M4 ;
        RECT  0.054 13.872 0.138 13.896 ;
    END
  END d[67]
  PIN d[68]
    DIRECTION INPUT ;
    USE SIGNAL ;
    PORT
      LAYER M4 ;
        RECT  0.054 13.968 0.138 13.992 ;
    END
  END d[68]
  PIN d[69]
    DIRECTION INPUT ;
    USE SIGNAL ;
    PORT
      LAYER M4 ;
        RECT  0.054 14.112 0.138 14.136 ;
    END
  END d[69]
  PIN d[6]
    DIRECTION INPUT ;
    USE SIGNAL ;
    PORT
      LAYER M4 ;
        RECT  0.054 6.144 0.138 6.168 ;
    END
  END d[6]
  PIN d[70]
    DIRECTION INPUT ;
    USE SIGNAL ;
    PORT
      LAYER M4 ;
        RECT  0.054 14.208 0.138 14.232 ;
    END
  END d[70]
  PIN d[71]
    DIRECTION INPUT ;
    USE SIGNAL ;
    PORT
      LAYER M4 ;
        RECT  0.054 14.352 0.138 14.376 ;
    END
  END d[71]
  PIN d[72]
    DIRECTION INPUT ;
    USE SIGNAL ;
    PORT
      LAYER M4 ;
        RECT  0.054 14.496 0.138 14.52 ;
    END
  END d[72]
  PIN d[73]
    DIRECTION INPUT ;
    USE SIGNAL ;
    PORT
      LAYER M4 ;
        RECT  0.054 14.592 0.138 14.616 ;
    END
  END d[73]
  PIN d[74]
    DIRECTION INPUT ;
    USE SIGNAL ;
    PORT
      LAYER M4 ;
        RECT  0.054 14.736 0.138 14.76 ;
    END
    PORT
      LAYER M4 ;
        RECT  0.025 14.736 0.108 14.76 ;
    END
  END d[74]
  PIN d[75]
    DIRECTION INPUT ;
    USE SIGNAL ;
    PORT
      LAYER M4 ;
        RECT  0.054 14.88 0.138 14.904 ;
    END
  END d[75]
  PIN d[76]
    DIRECTION INPUT ;
    USE SIGNAL ;
    PORT
      LAYER M4 ;
        RECT  0.054 14.976 0.138 15 ;
    END
  END d[76]
  PIN d[77]
    DIRECTION INPUT ;
    USE SIGNAL ;
    PORT
      LAYER M4 ;
        RECT  0.054 15.12 0.138 15.144 ;
    END
  END d[77]
  PIN d[78]
    DIRECTION INPUT ;
    USE SIGNAL ;
    PORT
      LAYER M4 ;
        RECT  0.054 15.264 0.138 15.288 ;
    END
  END d[78]
  PIN d[79]
    DIRECTION INPUT ;
    USE SIGNAL ;
    PORT
      LAYER M4 ;
        RECT  0.054 15.36 0.138 15.384 ;
    END
  END d[79]
  PIN d[7]
    DIRECTION INPUT ;
    USE SIGNAL ;
    PORT
      LAYER M4 ;
        RECT  0.054 6.288 0.138 6.312 ;
    END
  END d[7]
  PIN d[80]
    DIRECTION INPUT ;
    USE SIGNAL ;
    PORT
      LAYER M4 ;
        RECT  0.054 15.504 0.138 15.528 ;
    END
  END d[80]
  PIN d[81]
    DIRECTION INPUT ;
    USE SIGNAL ;
    PORT
      LAYER M4 ;
        RECT  0.054 15.6 0.138 15.624 ;
    END
  END d[81]
  PIN d[82]
    DIRECTION INPUT ;
    USE SIGNAL ;
    PORT
      LAYER M4 ;
        RECT  0.054 15.744 0.138 15.768 ;
    END
    PORT
      LAYER M4 ;
        RECT  0.025 15.744 0.108 15.768 ;
    END
  END d[82]
  PIN d[83]
    DIRECTION INPUT ;
    USE SIGNAL ;
    PORT
      LAYER M4 ;
        RECT  0.054 15.888 0.138 15.912 ;
    END
  END d[83]
  PIN d[84]
    DIRECTION INPUT ;
    USE SIGNAL ;
    PORT
      LAYER M4 ;
        RECT  0.054 15.984 0.138 16.008 ;
    END
  END d[84]
  PIN d[85]
    DIRECTION INPUT ;
    USE SIGNAL ;
    PORT
      LAYER M4 ;
        RECT  0.054 16.128 0.138 16.152 ;
    END
  END d[85]
  PIN d[86]
    DIRECTION INPUT ;
    USE SIGNAL ;
    PORT
      LAYER M4 ;
        RECT  0.054 16.272 0.138 16.296 ;
    END
  END d[86]
  PIN d[87]
    DIRECTION INPUT ;
    USE SIGNAL ;
    PORT
      LAYER M4 ;
        RECT  0.054 16.368 0.138 16.392 ;
    END
  END d[87]
  PIN d[88]
    DIRECTION INPUT ;
    USE SIGNAL ;
    PORT
      LAYER M4 ;
        RECT  0.054 16.512 0.138 16.536 ;
    END
  END d[88]
  PIN d[89]
    DIRECTION INPUT ;
    USE SIGNAL ;
    PORT
      LAYER M4 ;
        RECT  0.054 16.608 0.138 16.632 ;
    END
  END d[89]
  PIN d[8]
    DIRECTION INPUT ;
    USE SIGNAL ;
    PORT
      LAYER M4 ;
        RECT  0.054 6.384 0.138 6.408 ;
    END
  END d[8]
  PIN d[90]
    DIRECTION INPUT ;
    USE SIGNAL ;
    PORT
      LAYER M4 ;
        RECT  0.054 16.752 0.138 16.776 ;
    END
  END d[90]
  PIN d[91]
    DIRECTION INPUT ;
    USE SIGNAL ;
    PORT
      LAYER M4 ;
        RECT  0.054 16.896 0.138 16.92 ;
    END
  END d[91]
  PIN d[92]
    DIRECTION INPUT ;
    USE SIGNAL ;
    PORT
      LAYER M4 ;
        RECT  0.054 16.992 0.138 17.016 ;
    END
  END d[92]
  PIN d[93]
    DIRECTION INPUT ;
    USE SIGNAL ;
    PORT
      LAYER M4 ;
        RECT  0.054 17.136 0.138 17.16 ;
    END
  END d[93]
  PIN d[94]
    DIRECTION INPUT ;
    USE SIGNAL ;
    PORT
      LAYER M4 ;
        RECT  0.054 17.28 0.138 17.304 ;
    END
  END d[94]
  PIN d[95]
    DIRECTION INPUT ;
    USE SIGNAL ;
    PORT
      LAYER M4 ;
        RECT  0.054 17.376 0.138 17.4 ;
    END
  END d[95]
  PIN d[96]
    DIRECTION INPUT ;
    USE SIGNAL ;
    PORT
      LAYER M4 ;
        RECT  0.054 17.52 0.138 17.544 ;
    END
  END d[96]
  PIN d[97]
    DIRECTION INPUT ;
    USE SIGNAL ;
    PORT
      LAYER M4 ;
        RECT  0.054 17.664 0.138 17.688 ;
    END
  END d[97]
  PIN d[98]
    DIRECTION INPUT ;
    USE SIGNAL ;
    PORT
      LAYER M4 ;
        RECT  0.054 17.76 0.138 17.784 ;
    END
  END d[98]
  PIN d[99]
    DIRECTION INPUT ;
    USE SIGNAL ;
    PORT
      LAYER M4 ;
        RECT  0.054 17.904 0.138 17.928 ;
    END
  END d[99]
  PIN d[9]
    DIRECTION INPUT ;
    USE SIGNAL ;
    PORT
      LAYER M4 ;
        RECT  0.054 6.528 0.138 6.552 ;
    END
  END d[9]
  PIN q[0]
    DIRECTION OUTPUT ;
    USE SIGNAL ;
    PORT
      LAYER M4 ;
        RECT  21.462 5.424 21.546 5.448 ;
    END
  END q[0]
  PIN q[100]
    DIRECTION OUTPUT ;
    USE SIGNAL ;
    PORT
      LAYER M4 ;
        RECT  21.462 18 21.546 18.024 ;
    END
  END q[100]
  PIN q[101]
    DIRECTION OUTPUT ;
    USE SIGNAL ;
    PORT
      LAYER M4 ;
        RECT  21.462 18.144 21.546 18.168 ;
    END
  END q[101]
  PIN q[102]
    DIRECTION OUTPUT ;
    USE SIGNAL ;
    PORT
      LAYER M4 ;
        RECT  21.462 18.288 21.546 18.312 ;
    END
  END q[102]
  PIN q[103]
    DIRECTION OUTPUT ;
    USE SIGNAL ;
    PORT
      LAYER M4 ;
        RECT  21.462 18.384 21.546 18.408 ;
    END
  END q[103]
  PIN q[104]
    DIRECTION OUTPUT ;
    USE SIGNAL ;
    PORT
      LAYER M4 ;
        RECT  21.462 18.528 21.546 18.552 ;
    END
    PORT
      LAYER M4 ;
        RECT  21.516 18.528 21.593 18.552 ;
    END
  END q[104]
  PIN q[105]
    DIRECTION OUTPUT ;
    USE SIGNAL ;
    PORT
      LAYER M4 ;
        RECT  21.462 18.672 21.546 18.696 ;
    END
  END q[105]
  PIN q[106]
    DIRECTION OUTPUT ;
    USE SIGNAL ;
    PORT
      LAYER M4 ;
        RECT  21.462 18.768 21.546 18.792 ;
    END
  END q[106]
  PIN q[107]
    DIRECTION OUTPUT ;
    USE SIGNAL ;
    PORT
      LAYER M4 ;
        RECT  21.462 18.912 21.546 18.936 ;
    END
  END q[107]
  PIN q[108]
    DIRECTION OUTPUT ;
    USE SIGNAL ;
    PORT
      LAYER M4 ;
        RECT  21.462 19.008 21.546 19.032 ;
    END
  END q[108]
  PIN q[109]
    DIRECTION OUTPUT ;
    USE SIGNAL ;
    PORT
      LAYER M4 ;
        RECT  21.462 19.152 21.546 19.176 ;
    END
  END q[109]
  PIN q[10]
    DIRECTION OUTPUT ;
    USE SIGNAL ;
    PORT
      LAYER M4 ;
        RECT  21.462 6.672 21.546 6.696 ;
    END
  END q[10]
  PIN q[110]
    DIRECTION OUTPUT ;
    USE SIGNAL ;
    PORT
      LAYER M4 ;
        RECT  21.462 19.296 21.546 19.32 ;
    END
  END q[110]
  PIN q[111]
    DIRECTION OUTPUT ;
    USE SIGNAL ;
    PORT
      LAYER M4 ;
        RECT  21.462 19.392 21.546 19.416 ;
    END
  END q[111]
  PIN q[112]
    DIRECTION OUTPUT ;
    USE SIGNAL ;
    PORT
      LAYER M4 ;
        RECT  21.462 19.536 21.546 19.56 ;
    END
  END q[112]
  PIN q[113]
    DIRECTION OUTPUT ;
    USE SIGNAL ;
    PORT
      LAYER M4 ;
        RECT  21.462 19.68 21.546 19.704 ;
    END
  END q[113]
  PIN q[114]
    DIRECTION OUTPUT ;
    USE SIGNAL ;
    PORT
      LAYER M4 ;
        RECT  21.462 19.776 21.546 19.8 ;
    END
  END q[114]
  PIN q[115]
    DIRECTION OUTPUT ;
    USE SIGNAL ;
    PORT
      LAYER M4 ;
        RECT  21.462 19.92 21.546 19.944 ;
    END
  END q[115]
  PIN q[116]
    DIRECTION OUTPUT ;
    USE SIGNAL ;
    PORT
      LAYER M4 ;
        RECT  21.462 20.064 21.546 20.088 ;
    END
  END q[116]
  PIN q[117]
    DIRECTION OUTPUT ;
    USE SIGNAL ;
    PORT
      LAYER M4 ;
        RECT  21.462 20.16 21.546 20.184 ;
    END
  END q[117]
  PIN q[118]
    DIRECTION OUTPUT ;
    USE SIGNAL ;
    PORT
      LAYER M4 ;
        RECT  21.462 20.304 21.546 20.328 ;
    END
  END q[118]
  PIN q[119]
    DIRECTION OUTPUT ;
    USE SIGNAL ;
    PORT
      LAYER M4 ;
        RECT  21.462 20.4 21.546 20.424 ;
    END
  END q[119]
  PIN q[11]
    DIRECTION OUTPUT ;
    USE SIGNAL ;
    PORT
      LAYER M4 ;
        RECT  21.462 6.768 21.546 6.792 ;
    END
  END q[11]
  PIN q[120]
    DIRECTION OUTPUT ;
    USE SIGNAL ;
    PORT
      LAYER M4 ;
        RECT  21.462 20.544 21.546 20.568 ;
    END
  END q[120]
  PIN q[121]
    DIRECTION OUTPUT ;
    USE SIGNAL ;
    PORT
      LAYER M4 ;
        RECT  21.462 20.688 21.546 20.712 ;
    END
  END q[121]
  PIN q[122]
    DIRECTION OUTPUT ;
    USE SIGNAL ;
    PORT
      LAYER M4 ;
        RECT  21.462 20.784 21.546 20.808 ;
    END
  END q[122]
  PIN q[123]
    DIRECTION OUTPUT ;
    USE SIGNAL ;
    PORT
      LAYER M4 ;
        RECT  21.462 20.928 21.546 20.952 ;
    END
  END q[123]
  PIN q[124]
    DIRECTION OUTPUT ;
    USE SIGNAL ;
    PORT
      LAYER M4 ;
        RECT  21.462 21.072 21.546 21.096 ;
    END
  END q[124]
  PIN q[125]
    DIRECTION OUTPUT ;
    USE SIGNAL ;
    PORT
      LAYER M4 ;
        RECT  21.462 21.168 21.546 21.192 ;
    END
  END q[125]
  PIN q[126]
    DIRECTION OUTPUT ;
    USE SIGNAL ;
    PORT
      LAYER M4 ;
        RECT  21.462 21.312 21.546 21.336 ;
    END
  END q[126]
  PIN q[127]
    DIRECTION OUTPUT ;
    USE SIGNAL ;
    PORT
      LAYER M4 ;
        RECT  21.462 21.408 21.546 21.432 ;
    END
  END q[127]
  PIN q[128]
    DIRECTION OUTPUT ;
    USE SIGNAL ;
    PORT
      LAYER M4 ;
        RECT  21.462 21.552 21.546 21.576 ;
    END
  END q[128]
  PIN q[129]
    DIRECTION OUTPUT ;
    USE SIGNAL ;
    PORT
      LAYER M4 ;
        RECT  21.462 21.696 21.546 21.72 ;
    END
  END q[129]
  PIN q[12]
    DIRECTION OUTPUT ;
    USE SIGNAL ;
    PORT
      LAYER M4 ;
        RECT  21.462 6.912 21.546 6.936 ;
    END
  END q[12]
  PIN q[130]
    DIRECTION OUTPUT ;
    USE SIGNAL ;
    PORT
      LAYER M4 ;
        RECT  21.462 21.792 21.546 21.816 ;
    END
  END q[130]
  PIN q[131]
    DIRECTION OUTPUT ;
    USE SIGNAL ;
    PORT
      LAYER M4 ;
        RECT  21.462 21.936 21.546 21.96 ;
    END
  END q[131]
  PIN q[132]
    DIRECTION OUTPUT ;
    USE SIGNAL ;
    PORT
      LAYER M4 ;
        RECT  21.462 22.08 21.546 22.104 ;
    END
  END q[132]
  PIN q[133]
    DIRECTION OUTPUT ;
    USE SIGNAL ;
    PORT
      LAYER M4 ;
        RECT  21.462 22.176 21.546 22.2 ;
    END
  END q[133]
  PIN q[134]
    DIRECTION OUTPUT ;
    USE SIGNAL ;
    PORT
      LAYER M4 ;
        RECT  21.462 22.32 21.546 22.344 ;
    END
  END q[134]
  PIN q[135]
    DIRECTION OUTPUT ;
    USE SIGNAL ;
    PORT
      LAYER M4 ;
        RECT  21.462 22.464 21.546 22.488 ;
    END
  END q[135]
  PIN q[136]
    DIRECTION OUTPUT ;
    USE SIGNAL ;
    PORT
      LAYER M4 ;
        RECT  21.462 22.56 21.546 22.584 ;
    END
  END q[136]
  PIN q[137]
    DIRECTION OUTPUT ;
    USE SIGNAL ;
    PORT
      LAYER M4 ;
        RECT  21.462 22.704 21.546 22.728 ;
    END
  END q[137]
  PIN q[138]
    DIRECTION OUTPUT ;
    USE SIGNAL ;
    PORT
      LAYER M4 ;
        RECT  21.462 22.8 21.546 22.824 ;
    END
  END q[138]
  PIN q[139]
    DIRECTION OUTPUT ;
    USE SIGNAL ;
    PORT
      LAYER M4 ;
        RECT  21.462 22.944 21.546 22.968 ;
    END
  END q[139]
  PIN q[13]
    DIRECTION OUTPUT ;
    USE SIGNAL ;
    PORT
      LAYER M4 ;
        RECT  21.462 7.008 21.546 7.032 ;
    END
  END q[13]
  PIN q[140]
    DIRECTION OUTPUT ;
    USE SIGNAL ;
    PORT
      LAYER M4 ;
        RECT  21.462 23.088 21.546 23.112 ;
    END
  END q[140]
  PIN q[141]
    DIRECTION OUTPUT ;
    USE SIGNAL ;
    PORT
      LAYER M4 ;
        RECT  21.462 23.184 21.546 23.208 ;
    END
  END q[141]
  PIN q[142]
    DIRECTION OUTPUT ;
    USE SIGNAL ;
    PORT
      LAYER M4 ;
        RECT  21.462 23.328 21.546 23.352 ;
    END
  END q[142]
  PIN q[143]
    DIRECTION OUTPUT ;
    USE SIGNAL ;
    PORT
      LAYER M4 ;
        RECT  21.462 23.472 21.546 23.496 ;
    END
  END q[143]
  PIN q[144]
    DIRECTION OUTPUT ;
    USE SIGNAL ;
    PORT
      LAYER M4 ;
        RECT  21.462 23.568 21.546 23.592 ;
    END
  END q[144]
  PIN q[145]
    DIRECTION OUTPUT ;
    USE SIGNAL ;
    PORT
      LAYER M4 ;
        RECT  21.462 23.712 21.546 23.736 ;
    END
  END q[145]
  PIN q[146]
    DIRECTION OUTPUT ;
    USE SIGNAL ;
    PORT
      LAYER M4 ;
        RECT  21.462 23.808 21.546 23.832 ;
    END
  END q[146]
  PIN q[147]
    DIRECTION OUTPUT ;
    USE SIGNAL ;
    PORT
      LAYER M4 ;
        RECT  21.462 23.952 21.546 23.976 ;
    END
  END q[147]
  PIN q[148]
    DIRECTION OUTPUT ;
    USE SIGNAL ;
    PORT
      LAYER M4 ;
        RECT  21.462 24.096 21.546 24.12 ;
    END
  END q[148]
  PIN q[149]
    DIRECTION OUTPUT ;
    USE SIGNAL ;
    PORT
      LAYER M4 ;
        RECT  21.462 24.192 21.546 24.216 ;
    END
  END q[149]
  PIN q[14]
    DIRECTION OUTPUT ;
    USE SIGNAL ;
    PORT
      LAYER M4 ;
        RECT  21.462 7.152 21.546 7.176 ;
    END
  END q[14]
  PIN q[150]
    DIRECTION OUTPUT ;
    USE SIGNAL ;
    PORT
      LAYER M4 ;
        RECT  21.462 24.336 21.546 24.36 ;
    END
  END q[150]
  PIN q[151]
    DIRECTION OUTPUT ;
    USE SIGNAL ;
    PORT
      LAYER M4 ;
        RECT  21.462 24.48 21.546 24.504 ;
    END
  END q[151]
  PIN q[152]
    DIRECTION OUTPUT ;
    USE SIGNAL ;
    PORT
      LAYER M4 ;
        RECT  21.462 24.576 21.546 24.6 ;
    END
  END q[152]
  PIN q[153]
    DIRECTION OUTPUT ;
    USE SIGNAL ;
    PORT
      LAYER M4 ;
        RECT  21.462 24.72 21.546 24.744 ;
    END
  END q[153]
  PIN q[154]
    DIRECTION OUTPUT ;
    USE SIGNAL ;
    PORT
      LAYER M4 ;
        RECT  21.462 24.864 21.546 24.888 ;
    END
  END q[154]
  PIN q[155]
    DIRECTION OUTPUT ;
    USE SIGNAL ;
    PORT
      LAYER M4 ;
        RECT  21.462 24.96 21.546 24.984 ;
    END
  END q[155]
  PIN q[156]
    DIRECTION OUTPUT ;
    USE SIGNAL ;
    PORT
      LAYER M4 ;
        RECT  21.462 25.104 21.546 25.128 ;
    END
  END q[156]
  PIN q[157]
    DIRECTION OUTPUT ;
    USE SIGNAL ;
    PORT
      LAYER M4 ;
        RECT  21.462 25.2 21.546 25.224 ;
    END
  END q[157]
  PIN q[158]
    DIRECTION OUTPUT ;
    USE SIGNAL ;
    PORT
      LAYER M4 ;
        RECT  21.462 25.344 21.546 25.368 ;
    END
  END q[158]
  PIN q[159]
    DIRECTION OUTPUT ;
    USE SIGNAL ;
    PORT
      LAYER M4 ;
        RECT  21.462 25.488 21.546 25.512 ;
    END
  END q[159]
  PIN q[15]
    DIRECTION OUTPUT ;
    USE SIGNAL ;
    PORT
      LAYER M4 ;
        RECT  21.462 7.296 21.546 7.32 ;
    END
  END q[15]
  PIN q[160]
    DIRECTION OUTPUT ;
    USE SIGNAL ;
    PORT
      LAYER M4 ;
        RECT  21.462 25.584 21.546 25.608 ;
    END
  END q[160]
  PIN q[161]
    DIRECTION OUTPUT ;
    USE SIGNAL ;
    PORT
      LAYER M4 ;
        RECT  21.462 25.728 21.546 25.752 ;
    END
  END q[161]
  PIN q[162]
    DIRECTION OUTPUT ;
    USE SIGNAL ;
    PORT
      LAYER M4 ;
        RECT  21.462 25.872 21.546 25.896 ;
    END
  END q[162]
  PIN q[163]
    DIRECTION OUTPUT ;
    USE SIGNAL ;
    PORT
      LAYER M4 ;
        RECT  21.462 25.968 21.546 25.992 ;
    END
  END q[163]
  PIN q[164]
    DIRECTION OUTPUT ;
    USE SIGNAL ;
    PORT
      LAYER M4 ;
        RECT  21.462 26.112 21.546 26.136 ;
    END
  END q[164]
  PIN q[165]
    DIRECTION OUTPUT ;
    USE SIGNAL ;
    PORT
      LAYER M4 ;
        RECT  21.462 26.208 21.546 26.232 ;
    END
  END q[165]
  PIN q[166]
    DIRECTION OUTPUT ;
    USE SIGNAL ;
    PORT
      LAYER M4 ;
        RECT  21.462 26.352 21.546 26.376 ;
    END
  END q[166]
  PIN q[167]
    DIRECTION OUTPUT ;
    USE SIGNAL ;
    PORT
      LAYER M4 ;
        RECT  21.462 26.496 21.546 26.52 ;
    END
    PORT
      LAYER M4 ;
        RECT  21.516 26.496 21.593 26.52 ;
    END
  END q[167]
  PIN q[168]
    DIRECTION OUTPUT ;
    USE SIGNAL ;
    PORT
      LAYER M4 ;
        RECT  21.462 26.592 21.546 26.616 ;
    END
  END q[168]
  PIN q[169]
    DIRECTION OUTPUT ;
    USE SIGNAL ;
    PORT
      LAYER M4 ;
        RECT  21.462 26.736 21.546 26.76 ;
    END
  END q[169]
  PIN q[16]
    DIRECTION OUTPUT ;
    USE SIGNAL ;
    PORT
      LAYER M4 ;
        RECT  21.462 7.392 21.546 7.416 ;
    END
  END q[16]
  PIN q[170]
    DIRECTION OUTPUT ;
    USE SIGNAL ;
    PORT
      LAYER M4 ;
        RECT  21.462 26.88 21.546 26.904 ;
    END
  END q[170]
  PIN q[171]
    DIRECTION OUTPUT ;
    USE SIGNAL ;
    PORT
      LAYER M4 ;
        RECT  21.462 26.976 21.546 27 ;
    END
  END q[171]
  PIN q[172]
    DIRECTION OUTPUT ;
    USE SIGNAL ;
    PORT
      LAYER M4 ;
        RECT  21.462 27.12 21.546 27.144 ;
    END
  END q[172]
  PIN q[173]
    DIRECTION OUTPUT ;
    USE SIGNAL ;
    PORT
      LAYER M4 ;
        RECT  21.462 27.264 21.546 27.288 ;
    END
  END q[173]
  PIN q[174]
    DIRECTION OUTPUT ;
    USE SIGNAL ;
    PORT
      LAYER M4 ;
        RECT  21.462 27.36 21.546 27.384 ;
    END
  END q[174]
  PIN q[175]
    DIRECTION OUTPUT ;
    USE SIGNAL ;
    PORT
      LAYER M4 ;
        RECT  21.462 27.504 21.546 27.528 ;
    END
  END q[175]
  PIN q[176]
    DIRECTION OUTPUT ;
    USE SIGNAL ;
    PORT
      LAYER M4 ;
        RECT  21.462 27.6 21.546 27.624 ;
    END
  END q[176]
  PIN q[177]
    DIRECTION OUTPUT ;
    USE SIGNAL ;
    PORT
      LAYER M4 ;
        RECT  21.462 27.744 21.546 27.768 ;
    END
  END q[177]
  PIN q[178]
    DIRECTION OUTPUT ;
    USE SIGNAL ;
    PORT
      LAYER M4 ;
        RECT  21.462 27.888 21.546 27.912 ;
    END
  END q[178]
  PIN q[179]
    DIRECTION OUTPUT ;
    USE SIGNAL ;
    PORT
      LAYER M4 ;
        RECT  21.462 27.984 21.546 28.008 ;
    END
  END q[179]
  PIN q[17]
    DIRECTION OUTPUT ;
    USE SIGNAL ;
    PORT
      LAYER M4 ;
        RECT  21.462 7.536 21.546 7.56 ;
    END
  END q[17]
  PIN q[180]
    DIRECTION OUTPUT ;
    USE SIGNAL ;
    PORT
      LAYER M4 ;
        RECT  21.462 28.128 21.546 28.152 ;
    END
  END q[180]
  PIN q[181]
    DIRECTION OUTPUT ;
    USE SIGNAL ;
    PORT
      LAYER M4 ;
        RECT  21.462 28.272 21.546 28.296 ;
    END
  END q[181]
  PIN q[182]
    DIRECTION OUTPUT ;
    USE SIGNAL ;
    PORT
      LAYER M4 ;
        RECT  21.462 28.368 21.546 28.392 ;
    END
  END q[182]
  PIN q[183]
    DIRECTION OUTPUT ;
    USE SIGNAL ;
    PORT
      LAYER M4 ;
        RECT  21.462 28.512 21.546 28.536 ;
    END
  END q[183]
  PIN q[184]
    DIRECTION OUTPUT ;
    USE SIGNAL ;
    PORT
      LAYER M4 ;
        RECT  21.462 28.608 21.546 28.632 ;
    END
  END q[184]
  PIN q[185]
    DIRECTION OUTPUT ;
    USE SIGNAL ;
    PORT
      LAYER M4 ;
        RECT  21.462 28.752 21.546 28.776 ;
    END
  END q[185]
  PIN q[186]
    DIRECTION OUTPUT ;
    USE SIGNAL ;
    PORT
      LAYER M4 ;
        RECT  21.462 28.896 21.546 28.92 ;
    END
  END q[186]
  PIN q[187]
    DIRECTION OUTPUT ;
    USE SIGNAL ;
    PORT
      LAYER M4 ;
        RECT  21.462 28.992 21.546 29.016 ;
    END
  END q[187]
  PIN q[188]
    DIRECTION OUTPUT ;
    USE SIGNAL ;
    PORT
      LAYER M4 ;
        RECT  21.462 29.136 21.546 29.16 ;
    END
  END q[188]
  PIN q[189]
    DIRECTION OUTPUT ;
    USE SIGNAL ;
    PORT
      LAYER M4 ;
        RECT  21.462 29.28 21.546 29.304 ;
    END
  END q[189]
  PIN q[18]
    DIRECTION OUTPUT ;
    USE SIGNAL ;
    PORT
      LAYER M4 ;
        RECT  21.462 7.68 21.546 7.704 ;
    END
  END q[18]
  PIN q[190]
    DIRECTION OUTPUT ;
    USE SIGNAL ;
    PORT
      LAYER M4 ;
        RECT  21.462 29.376 21.546 29.4 ;
    END
  END q[190]
  PIN q[191]
    DIRECTION OUTPUT ;
    USE SIGNAL ;
    PORT
      LAYER M4 ;
        RECT  21.462 29.52 21.546 29.544 ;
    END
  END q[191]
  PIN q[192]
    DIRECTION OUTPUT ;
    USE SIGNAL ;
    PORT
      LAYER M4 ;
        RECT  21.462 29.664 21.546 29.688 ;
    END
  END q[192]
  PIN q[193]
    DIRECTION OUTPUT ;
    USE SIGNAL ;
    PORT
      LAYER M4 ;
        RECT  21.462 29.76 21.546 29.784 ;
    END
  END q[193]
  PIN q[194]
    DIRECTION OUTPUT ;
    USE SIGNAL ;
    PORT
      LAYER M4 ;
        RECT  21.462 29.904 21.546 29.928 ;
    END
  END q[194]
  PIN q[195]
    DIRECTION OUTPUT ;
    USE SIGNAL ;
    PORT
      LAYER M4 ;
        RECT  21.462 30 21.546 30.024 ;
    END
  END q[195]
  PIN q[196]
    DIRECTION OUTPUT ;
    USE SIGNAL ;
    PORT
      LAYER M4 ;
        RECT  21.462 30.144 21.546 30.168 ;
    END
  END q[196]
  PIN q[197]
    DIRECTION OUTPUT ;
    USE SIGNAL ;
    PORT
      LAYER M4 ;
        RECT  21.462 30.288 21.546 30.312 ;
    END
  END q[197]
  PIN q[198]
    DIRECTION OUTPUT ;
    USE SIGNAL ;
    PORT
      LAYER M4 ;
        RECT  21.462 30.384 21.546 30.408 ;
    END
  END q[198]
  PIN q[199]
    DIRECTION OUTPUT ;
    USE SIGNAL ;
    PORT
      LAYER M4 ;
        RECT  21.462 30.528 21.546 30.552 ;
    END
  END q[199]
  PIN q[19]
    DIRECTION OUTPUT ;
    USE SIGNAL ;
    PORT
      LAYER M4 ;
        RECT  21.462 7.776 21.546 7.8 ;
    END
  END q[19]
  PIN q[1]
    DIRECTION OUTPUT ;
    USE SIGNAL ;
    PORT
      LAYER M4 ;
        RECT  21.462 5.52 21.546 5.544 ;
    END
  END q[1]
  PIN q[200]
    DIRECTION OUTPUT ;
    USE SIGNAL ;
    PORT
      LAYER M4 ;
        RECT  21.462 30.672 21.546 30.696 ;
    END
  END q[200]
  PIN q[201]
    DIRECTION OUTPUT ;
    USE SIGNAL ;
    PORT
      LAYER M4 ;
        RECT  21.462 30.768 21.546 30.792 ;
    END
  END q[201]
  PIN q[202]
    DIRECTION OUTPUT ;
    USE SIGNAL ;
    PORT
      LAYER M4 ;
        RECT  21.462 30.912 21.546 30.936 ;
    END
  END q[202]
  PIN q[203]
    DIRECTION OUTPUT ;
    USE SIGNAL ;
    PORT
      LAYER M4 ;
        RECT  21.462 31.008 21.546 31.032 ;
    END
  END q[203]
  PIN q[204]
    DIRECTION OUTPUT ;
    USE SIGNAL ;
    PORT
      LAYER M4 ;
        RECT  21.462 31.152 21.546 31.176 ;
    END
  END q[204]
  PIN q[205]
    DIRECTION OUTPUT ;
    USE SIGNAL ;
    PORT
      LAYER M4 ;
        RECT  21.462 31.296 21.546 31.32 ;
    END
  END q[205]
  PIN q[206]
    DIRECTION OUTPUT ;
    USE SIGNAL ;
    PORT
      LAYER M4 ;
        RECT  21.462 31.392 21.546 31.416 ;
    END
  END q[206]
  PIN q[207]
    DIRECTION OUTPUT ;
    USE SIGNAL ;
    PORT
      LAYER M4 ;
        RECT  21.462 31.536 21.546 31.56 ;
    END
  END q[207]
  PIN q[208]
    DIRECTION OUTPUT ;
    USE SIGNAL ;
    PORT
      LAYER M4 ;
        RECT  21.462 31.68 21.546 31.704 ;
    END
  END q[208]
  PIN q[209]
    DIRECTION OUTPUT ;
    USE SIGNAL ;
    PORT
      LAYER M4 ;
        RECT  21.462 31.776 21.546 31.8 ;
    END
  END q[209]
  PIN q[20]
    DIRECTION OUTPUT ;
    USE SIGNAL ;
    PORT
      LAYER M4 ;
        RECT  21.462 7.92 21.546 7.944 ;
    END
  END q[20]
  PIN q[210]
    DIRECTION OUTPUT ;
    USE SIGNAL ;
    PORT
      LAYER M4 ;
        RECT  21.462 31.92 21.546 31.944 ;
    END
  END q[210]
  PIN q[211]
    DIRECTION OUTPUT ;
    USE SIGNAL ;
    PORT
      LAYER M4 ;
        RECT  21.462 32.064 21.546 32.088 ;
    END
  END q[211]
  PIN q[212]
    DIRECTION OUTPUT ;
    USE SIGNAL ;
    PORT
      LAYER M4 ;
        RECT  21.462 32.16 21.546 32.184 ;
    END
  END q[212]
  PIN q[213]
    DIRECTION OUTPUT ;
    USE SIGNAL ;
    PORT
      LAYER M4 ;
        RECT  21.462 32.304 21.546 32.328 ;
    END
  END q[213]
  PIN q[214]
    DIRECTION OUTPUT ;
    USE SIGNAL ;
    PORT
      LAYER M4 ;
        RECT  21.462 32.4 21.546 32.424 ;
    END
  END q[214]
  PIN q[215]
    DIRECTION OUTPUT ;
    USE SIGNAL ;
    PORT
      LAYER M4 ;
        RECT  21.462 32.544 21.546 32.568 ;
    END
  END q[215]
  PIN q[216]
    DIRECTION OUTPUT ;
    USE SIGNAL ;
    PORT
      LAYER M4 ;
        RECT  21.462 32.688 21.546 32.712 ;
    END
  END q[216]
  PIN q[217]
    DIRECTION OUTPUT ;
    USE SIGNAL ;
    PORT
      LAYER M4 ;
        RECT  21.462 32.784 21.546 32.808 ;
    END
  END q[217]
  PIN q[218]
    DIRECTION OUTPUT ;
    USE SIGNAL ;
    PORT
      LAYER M4 ;
        RECT  21.462 32.928 21.546 32.952 ;
    END
  END q[218]
  PIN q[219]
    DIRECTION OUTPUT ;
    USE SIGNAL ;
    PORT
      LAYER M4 ;
        RECT  21.462 33.072 21.546 33.096 ;
    END
  END q[219]
  PIN q[21]
    DIRECTION OUTPUT ;
    USE SIGNAL ;
    PORT
      LAYER M4 ;
        RECT  21.462 8.064 21.546 8.088 ;
    END
  END q[21]
  PIN q[220]
    DIRECTION OUTPUT ;
    USE SIGNAL ;
    PORT
      LAYER M4 ;
        RECT  21.462 33.168 21.546 33.192 ;
    END
  END q[220]
  PIN q[221]
    DIRECTION OUTPUT ;
    USE SIGNAL ;
    PORT
      LAYER M4 ;
        RECT  21.462 33.312 21.546 33.336 ;
    END
  END q[221]
  PIN q[222]
    DIRECTION OUTPUT ;
    USE SIGNAL ;
    PORT
      LAYER M4 ;
        RECT  21.462 33.408 21.546 33.432 ;
    END
  END q[222]
  PIN q[223]
    DIRECTION OUTPUT ;
    USE SIGNAL ;
    PORT
      LAYER M4 ;
        RECT  21.462 33.552 21.546 33.576 ;
    END
  END q[223]
  PIN q[224]
    DIRECTION OUTPUT ;
    USE SIGNAL ;
    PORT
      LAYER M4 ;
        RECT  21.462 33.696 21.546 33.72 ;
    END
  END q[224]
  PIN q[225]
    DIRECTION OUTPUT ;
    USE SIGNAL ;
    PORT
      LAYER M4 ;
        RECT  21.462 33.792 21.546 33.816 ;
    END
  END q[225]
  PIN q[226]
    DIRECTION OUTPUT ;
    USE SIGNAL ;
    PORT
      LAYER M4 ;
        RECT  21.462 33.936 21.546 33.96 ;
    END
  END q[226]
  PIN q[227]
    DIRECTION OUTPUT ;
    USE SIGNAL ;
    PORT
      LAYER M4 ;
        RECT  21.462 34.08 21.546 34.104 ;
    END
  END q[227]
  PIN q[228]
    DIRECTION OUTPUT ;
    USE SIGNAL ;
    PORT
      LAYER M4 ;
        RECT  21.462 34.176 21.546 34.2 ;
    END
  END q[228]
  PIN q[229]
    DIRECTION OUTPUT ;
    USE SIGNAL ;
    PORT
      LAYER M4 ;
        RECT  21.462 34.32 21.546 34.344 ;
    END
  END q[229]
  PIN q[22]
    DIRECTION OUTPUT ;
    USE SIGNAL ;
    PORT
      LAYER M4 ;
        RECT  21.462 8.16 21.546 8.184 ;
    END
  END q[22]
  PIN q[230]
    DIRECTION OUTPUT ;
    USE SIGNAL ;
    PORT
      LAYER M4 ;
        RECT  21.462 34.464 21.546 34.488 ;
    END
  END q[230]
  PIN q[231]
    DIRECTION OUTPUT ;
    USE SIGNAL ;
    PORT
      LAYER M4 ;
        RECT  21.462 34.56 21.546 34.584 ;
    END
  END q[231]
  PIN q[232]
    DIRECTION OUTPUT ;
    USE SIGNAL ;
    PORT
      LAYER M4 ;
        RECT  21.462 34.704 21.546 34.728 ;
    END
  END q[232]
  PIN q[233]
    DIRECTION OUTPUT ;
    USE SIGNAL ;
    PORT
      LAYER M4 ;
        RECT  21.462 34.8 21.546 34.824 ;
    END
  END q[233]
  PIN q[234]
    DIRECTION OUTPUT ;
    USE SIGNAL ;
    PORT
      LAYER M4 ;
        RECT  21.462 34.944 21.546 34.968 ;
    END
  END q[234]
  PIN q[235]
    DIRECTION OUTPUT ;
    USE SIGNAL ;
    PORT
      LAYER M4 ;
        RECT  21.462 35.088 21.546 35.112 ;
    END
  END q[235]
  PIN q[236]
    DIRECTION OUTPUT ;
    USE SIGNAL ;
    PORT
      LAYER M4 ;
        RECT  21.462 35.184 21.546 35.208 ;
    END
  END q[236]
  PIN q[237]
    DIRECTION OUTPUT ;
    USE SIGNAL ;
    PORT
      LAYER M4 ;
        RECT  21.462 35.328 21.546 35.352 ;
    END
  END q[237]
  PIN q[238]
    DIRECTION OUTPUT ;
    USE SIGNAL ;
    PORT
      LAYER M4 ;
        RECT  21.462 35.472 21.546 35.496 ;
    END
  END q[238]
  PIN q[239]
    DIRECTION OUTPUT ;
    USE SIGNAL ;
    PORT
      LAYER M4 ;
        RECT  21.462 35.568 21.546 35.592 ;
    END
  END q[239]
  PIN q[23]
    DIRECTION OUTPUT ;
    USE SIGNAL ;
    PORT
      LAYER M4 ;
        RECT  21.462 8.304 21.546 8.328 ;
    END
  END q[23]
  PIN q[240]
    DIRECTION OUTPUT ;
    USE SIGNAL ;
    PORT
      LAYER M4 ;
        RECT  21.462 35.712 21.546 35.736 ;
    END
  END q[240]
  PIN q[241]
    DIRECTION OUTPUT ;
    USE SIGNAL ;
    PORT
      LAYER M4 ;
        RECT  21.462 35.808 21.546 35.832 ;
    END
  END q[241]
  PIN q[242]
    DIRECTION OUTPUT ;
    USE SIGNAL ;
    PORT
      LAYER M4 ;
        RECT  21.462 35.952 21.546 35.976 ;
    END
  END q[242]
  PIN q[243]
    DIRECTION OUTPUT ;
    USE SIGNAL ;
    PORT
      LAYER M4 ;
        RECT  21.462 36.096 21.546 36.12 ;
    END
  END q[243]
  PIN q[244]
    DIRECTION OUTPUT ;
    USE SIGNAL ;
    PORT
      LAYER M4 ;
        RECT  21.462 36.192 21.546 36.216 ;
    END
  END q[244]
  PIN q[245]
    DIRECTION OUTPUT ;
    USE SIGNAL ;
    PORT
      LAYER M4 ;
        RECT  21.462 36.336 21.546 36.36 ;
    END
  END q[245]
  PIN q[246]
    DIRECTION OUTPUT ;
    USE SIGNAL ;
    PORT
      LAYER M4 ;
        RECT  21.462 36.48 21.546 36.504 ;
    END
  END q[246]
  PIN q[247]
    DIRECTION OUTPUT ;
    USE SIGNAL ;
    PORT
      LAYER M4 ;
        RECT  21.462 36.576 21.546 36.6 ;
    END
  END q[247]
  PIN q[248]
    DIRECTION OUTPUT ;
    USE SIGNAL ;
    PORT
      LAYER M4 ;
        RECT  21.462 36.72 21.546 36.744 ;
    END
  END q[248]
  PIN q[249]
    DIRECTION OUTPUT ;
    USE SIGNAL ;
    PORT
      LAYER M4 ;
        RECT  21.462 36.864 21.546 36.888 ;
    END
  END q[249]
  PIN q[24]
    DIRECTION OUTPUT ;
    USE SIGNAL ;
    PORT
      LAYER M4 ;
        RECT  21.462 8.4 21.546 8.424 ;
    END
  END q[24]
  PIN q[250]
    DIRECTION OUTPUT ;
    USE SIGNAL ;
    PORT
      LAYER M4 ;
        RECT  21.462 36.96 21.546 36.984 ;
    END
  END q[250]
  PIN q[251]
    DIRECTION OUTPUT ;
    USE SIGNAL ;
    PORT
      LAYER M4 ;
        RECT  21.462 37.104 21.546 37.128 ;
    END
  END q[251]
  PIN q[252]
    DIRECTION OUTPUT ;
    USE SIGNAL ;
    PORT
      LAYER M4 ;
        RECT  21.462 37.2 21.546 37.224 ;
    END
  END q[252]
  PIN q[253]
    DIRECTION OUTPUT ;
    USE SIGNAL ;
    PORT
      LAYER M4 ;
        RECT  21.462 37.344 21.546 37.368 ;
    END
  END q[253]
  PIN q[254]
    DIRECTION OUTPUT ;
    USE SIGNAL ;
    PORT
      LAYER M4 ;
        RECT  21.462 37.488 21.546 37.512 ;
    END
  END q[254]
  PIN q[255]
    DIRECTION OUTPUT ;
    USE SIGNAL ;
    PORT
      LAYER M4 ;
        RECT  21.462 37.584 21.546 37.608 ;
    END
  END q[255]
  PIN q[256]
    DIRECTION OUTPUT ;
    USE SIGNAL ;
    PORT
      LAYER M4 ;
        RECT  21.462 37.728 21.546 37.752 ;
    END
  END q[256]
  PIN q[257]
    DIRECTION OUTPUT ;
    USE SIGNAL ;
    PORT
      LAYER M4 ;
        RECT  21.462 37.872 21.546 37.896 ;
    END
  END q[257]
  PIN q[258]
    DIRECTION OUTPUT ;
    USE SIGNAL ;
    PORT
      LAYER M4 ;
        RECT  21.462 37.968 21.546 37.992 ;
    END
  END q[258]
  PIN q[259]
    DIRECTION OUTPUT ;
    USE SIGNAL ;
    PORT
      LAYER M4 ;
        RECT  21.462 38.112 21.546 38.136 ;
    END
  END q[259]
  PIN q[25]
    DIRECTION OUTPUT ;
    USE SIGNAL ;
    PORT
      LAYER M4 ;
        RECT  21.462 8.544 21.546 8.568 ;
    END
  END q[25]
  PIN q[260]
    DIRECTION OUTPUT ;
    USE SIGNAL ;
    PORT
      LAYER M4 ;
        RECT  21.462 38.208 21.546 38.232 ;
    END
  END q[260]
  PIN q[261]
    DIRECTION OUTPUT ;
    USE SIGNAL ;
    PORT
      LAYER M4 ;
        RECT  21.462 38.352 21.546 38.376 ;
    END
  END q[261]
  PIN q[262]
    DIRECTION OUTPUT ;
    USE SIGNAL ;
    PORT
      LAYER M4 ;
        RECT  21.462 38.496 21.546 38.52 ;
    END
  END q[262]
  PIN q[263]
    DIRECTION OUTPUT ;
    USE SIGNAL ;
    PORT
      LAYER M4 ;
        RECT  21.462 38.592 21.546 38.616 ;
    END
  END q[263]
  PIN q[264]
    DIRECTION OUTPUT ;
    USE SIGNAL ;
    PORT
      LAYER M4 ;
        RECT  21.462 38.736 21.546 38.76 ;
    END
  END q[264]
  PIN q[265]
    DIRECTION OUTPUT ;
    USE SIGNAL ;
    PORT
      LAYER M4 ;
        RECT  21.462 38.88 21.546 38.904 ;
    END
  END q[265]
  PIN q[266]
    DIRECTION OUTPUT ;
    USE SIGNAL ;
    PORT
      LAYER M4 ;
        RECT  21.462 38.976 21.546 39 ;
    END
  END q[266]
  PIN q[267]
    DIRECTION OUTPUT ;
    USE SIGNAL ;
    PORT
      LAYER M4 ;
        RECT  21.462 39.12 21.546 39.144 ;
    END
  END q[267]
  PIN q[268]
    DIRECTION OUTPUT ;
    USE SIGNAL ;
    PORT
      LAYER M4 ;
        RECT  21.462 39.264 21.546 39.288 ;
    END
  END q[268]
  PIN q[269]
    DIRECTION OUTPUT ;
    USE SIGNAL ;
    PORT
      LAYER M4 ;
        RECT  21.462 39.36 21.546 39.384 ;
    END
  END q[269]
  PIN q[26]
    DIRECTION OUTPUT ;
    USE SIGNAL ;
    PORT
      LAYER M4 ;
        RECT  21.462 8.688 21.546 8.712 ;
    END
  END q[26]
  PIN q[270]
    DIRECTION OUTPUT ;
    USE SIGNAL ;
    PORT
      LAYER M4 ;
        RECT  21.462 39.504 21.546 39.528 ;
    END
  END q[270]
  PIN q[271]
    DIRECTION OUTPUT ;
    USE SIGNAL ;
    PORT
      LAYER M4 ;
        RECT  21.462 39.6 21.546 39.624 ;
    END
  END q[271]
  PIN q[272]
    DIRECTION OUTPUT ;
    USE SIGNAL ;
    PORT
      LAYER M4 ;
        RECT  21.462 39.744 21.546 39.768 ;
    END
  END q[272]
  PIN q[273]
    DIRECTION OUTPUT ;
    USE SIGNAL ;
    PORT
      LAYER M4 ;
        RECT  21.462 39.888 21.546 39.912 ;
    END
  END q[273]
  PIN q[274]
    DIRECTION OUTPUT ;
    USE SIGNAL ;
    PORT
      LAYER M4 ;
        RECT  21.462 39.984 21.546 40.008 ;
    END
  END q[274]
  PIN q[275]
    DIRECTION OUTPUT ;
    USE SIGNAL ;
    PORT
      LAYER M4 ;
        RECT  21.462 40.128 21.546 40.152 ;
    END
  END q[275]
  PIN q[276]
    DIRECTION OUTPUT ;
    USE SIGNAL ;
    PORT
      LAYER M4 ;
        RECT  21.462 40.272 21.546 40.296 ;
    END
  END q[276]
  PIN q[277]
    DIRECTION OUTPUT ;
    USE SIGNAL ;
    PORT
      LAYER M4 ;
        RECT  21.462 40.368 21.546 40.392 ;
    END
  END q[277]
  PIN q[278]
    DIRECTION OUTPUT ;
    USE SIGNAL ;
    PORT
      LAYER M4 ;
        RECT  21.462 40.512 21.546 40.536 ;
    END
  END q[278]
  PIN q[279]
    DIRECTION OUTPUT ;
    USE SIGNAL ;
    PORT
      LAYER M4 ;
        RECT  21.462 40.608 21.546 40.632 ;
    END
  END q[279]
  PIN q[27]
    DIRECTION OUTPUT ;
    USE SIGNAL ;
    PORT
      LAYER M4 ;
        RECT  21.462 8.784 21.546 8.808 ;
    END
  END q[27]
  PIN q[280]
    DIRECTION OUTPUT ;
    USE SIGNAL ;
    PORT
      LAYER M4 ;
        RECT  21.462 40.752 21.546 40.776 ;
    END
  END q[280]
  PIN q[281]
    DIRECTION OUTPUT ;
    USE SIGNAL ;
    PORT
      LAYER M4 ;
        RECT  21.462 40.896 21.546 40.92 ;
    END
  END q[281]
  PIN q[282]
    DIRECTION OUTPUT ;
    USE SIGNAL ;
    PORT
      LAYER M4 ;
        RECT  21.462 40.992 21.546 41.016 ;
    END
  END q[282]
  PIN q[283]
    DIRECTION OUTPUT ;
    USE SIGNAL ;
    PORT
      LAYER M4 ;
        RECT  21.462 41.136 21.546 41.16 ;
    END
  END q[283]
  PIN q[284]
    DIRECTION OUTPUT ;
    USE SIGNAL ;
    PORT
      LAYER M4 ;
        RECT  21.462 41.28 21.546 41.304 ;
    END
  END q[284]
  PIN q[285]
    DIRECTION OUTPUT ;
    USE SIGNAL ;
    PORT
      LAYER M4 ;
        RECT  21.462 41.376 21.546 41.4 ;
    END
  END q[285]
  PIN q[286]
    DIRECTION OUTPUT ;
    USE SIGNAL ;
    PORT
      LAYER M4 ;
        RECT  21.462 41.52 21.546 41.544 ;
    END
  END q[286]
  PIN q[287]
    DIRECTION OUTPUT ;
    USE SIGNAL ;
    PORT
      LAYER M4 ;
        RECT  21.462 41.664 21.546 41.688 ;
    END
  END q[287]
  PIN q[288]
    DIRECTION OUTPUT ;
    USE SIGNAL ;
    PORT
      LAYER M4 ;
        RECT  21.462 41.76 21.546 41.784 ;
    END
  END q[288]
  PIN q[289]
    DIRECTION OUTPUT ;
    USE SIGNAL ;
    PORT
      LAYER M4 ;
        RECT  21.462 41.904 21.546 41.928 ;
    END
  END q[289]
  PIN q[28]
    DIRECTION OUTPUT ;
    USE SIGNAL ;
    PORT
      LAYER M4 ;
        RECT  21.462 8.928 21.546 8.952 ;
    END
  END q[28]
  PIN q[290]
    DIRECTION OUTPUT ;
    USE SIGNAL ;
    PORT
      LAYER M4 ;
        RECT  21.462 42 21.546 42.024 ;
    END
  END q[290]
  PIN q[291]
    DIRECTION OUTPUT ;
    USE SIGNAL ;
    PORT
      LAYER M4 ;
        RECT  21.462 42.144 21.546 42.168 ;
    END
  END q[291]
  PIN q[292]
    DIRECTION OUTPUT ;
    USE SIGNAL ;
    PORT
      LAYER M4 ;
        RECT  21.462 42.288 21.546 42.312 ;
    END
  END q[292]
  PIN q[293]
    DIRECTION OUTPUT ;
    USE SIGNAL ;
    PORT
      LAYER M4 ;
        RECT  21.462 42.384 21.546 42.408 ;
    END
  END q[293]
  PIN q[294]
    DIRECTION OUTPUT ;
    USE SIGNAL ;
    PORT
      LAYER M4 ;
        RECT  21.462 42.528 21.546 42.552 ;
    END
  END q[294]
  PIN q[295]
    DIRECTION OUTPUT ;
    USE SIGNAL ;
    PORT
      LAYER M4 ;
        RECT  21.462 42.672 21.546 42.696 ;
    END
  END q[295]
  PIN q[296]
    DIRECTION OUTPUT ;
    USE SIGNAL ;
    PORT
      LAYER M4 ;
        RECT  21.462 42.768 21.546 42.792 ;
    END
  END q[296]
  PIN q[297]
    DIRECTION OUTPUT ;
    USE SIGNAL ;
    PORT
      LAYER M4 ;
        RECT  21.462 42.912 21.546 42.936 ;
    END
  END q[297]
  PIN q[298]
    DIRECTION OUTPUT ;
    USE SIGNAL ;
    PORT
      LAYER M4 ;
        RECT  21.462 43.008 21.546 43.032 ;
    END
  END q[298]
  PIN q[299]
    DIRECTION OUTPUT ;
    USE SIGNAL ;
    PORT
      LAYER M4 ;
        RECT  21.462 43.152 21.546 43.176 ;
    END
  END q[299]
  PIN q[29]
    DIRECTION OUTPUT ;
    USE SIGNAL ;
    PORT
      LAYER M4 ;
        RECT  21.462 9.072 21.546 9.096 ;
    END
  END q[29]
  PIN q[2]
    DIRECTION OUTPUT ;
    USE SIGNAL ;
    PORT
      LAYER M4 ;
        RECT  21.462 5.664 21.546 5.688 ;
    END
  END q[2]
  PIN q[300]
    DIRECTION OUTPUT ;
    USE SIGNAL ;
    PORT
      LAYER M4 ;
        RECT  21.462 43.296 21.546 43.32 ;
    END
  END q[300]
  PIN q[301]
    DIRECTION OUTPUT ;
    USE SIGNAL ;
    PORT
      LAYER M4 ;
        RECT  21.462 43.392 21.546 43.416 ;
    END
  END q[301]
  PIN q[302]
    DIRECTION OUTPUT ;
    USE SIGNAL ;
    PORT
      LAYER M4 ;
        RECT  21.462 43.536 21.546 43.56 ;
    END
  END q[302]
  PIN q[303]
    DIRECTION OUTPUT ;
    USE SIGNAL ;
    PORT
      LAYER M4 ;
        RECT  21.462 43.68 21.546 43.704 ;
    END
  END q[303]
  PIN q[304]
    DIRECTION OUTPUT ;
    USE SIGNAL ;
    PORT
      LAYER M4 ;
        RECT  21.462 43.776 21.546 43.8 ;
    END
  END q[304]
  PIN q[305]
    DIRECTION OUTPUT ;
    USE SIGNAL ;
    PORT
      LAYER M4 ;
        RECT  21.462 43.92 21.546 43.944 ;
    END
  END q[305]
  PIN q[306]
    DIRECTION OUTPUT ;
    USE SIGNAL ;
    PORT
      LAYER M4 ;
        RECT  21.462 44.064 21.546 44.088 ;
    END
  END q[306]
  PIN q[307]
    DIRECTION OUTPUT ;
    USE SIGNAL ;
    PORT
      LAYER M4 ;
        RECT  21.462 44.16 21.546 44.184 ;
    END
  END q[307]
  PIN q[308]
    DIRECTION OUTPUT ;
    USE SIGNAL ;
    PORT
      LAYER M4 ;
        RECT  21.462 44.304 21.546 44.328 ;
    END
  END q[308]
  PIN q[309]
    DIRECTION OUTPUT ;
    USE SIGNAL ;
    PORT
      LAYER M4 ;
        RECT  21.462 44.4 21.546 44.424 ;
    END
  END q[309]
  PIN q[30]
    DIRECTION OUTPUT ;
    USE SIGNAL ;
    PORT
      LAYER M4 ;
        RECT  21.462 9.168 21.546 9.192 ;
    END
  END q[30]
  PIN q[310]
    DIRECTION OUTPUT ;
    USE SIGNAL ;
    PORT
      LAYER M4 ;
        RECT  21.462 44.544 21.546 44.568 ;
    END
  END q[310]
  PIN q[311]
    DIRECTION OUTPUT ;
    USE SIGNAL ;
    PORT
      LAYER M4 ;
        RECT  21.462 44.688 21.546 44.712 ;
    END
  END q[311]
  PIN q[312]
    DIRECTION OUTPUT ;
    USE SIGNAL ;
    PORT
      LAYER M4 ;
        RECT  21.462 44.784 21.546 44.808 ;
    END
  END q[312]
  PIN q[313]
    DIRECTION OUTPUT ;
    USE SIGNAL ;
    PORT
      LAYER M4 ;
        RECT  21.462 44.928 21.546 44.952 ;
    END
  END q[313]
  PIN q[314]
    DIRECTION OUTPUT ;
    USE SIGNAL ;
    PORT
      LAYER M4 ;
        RECT  21.462 45.072 21.546 45.096 ;
    END
  END q[314]
  PIN q[315]
    DIRECTION OUTPUT ;
    USE SIGNAL ;
    PORT
      LAYER M4 ;
        RECT  21.462 45.168 21.546 45.192 ;
    END
  END q[315]
  PIN q[316]
    DIRECTION OUTPUT ;
    USE SIGNAL ;
    PORT
      LAYER M4 ;
        RECT  21.462 45.312 21.546 45.336 ;
    END
  END q[316]
  PIN q[317]
    DIRECTION OUTPUT ;
    USE SIGNAL ;
    PORT
      LAYER M4 ;
        RECT  21.462 45.408 21.546 45.432 ;
    END
  END q[317]
  PIN q[318]
    DIRECTION OUTPUT ;
    USE SIGNAL ;
    PORT
      LAYER M4 ;
        RECT  21.462 45.552 21.546 45.576 ;
    END
  END q[318]
  PIN q[319]
    DIRECTION OUTPUT ;
    USE SIGNAL ;
    PORT
      LAYER M4 ;
        RECT  21.462 45.696 21.546 45.72 ;
    END
  END q[319]
  PIN q[31]
    DIRECTION OUTPUT ;
    USE SIGNAL ;
    PORT
      LAYER M4 ;
        RECT  21.462 9.312 21.546 9.336 ;
    END
  END q[31]
  PIN q[320]
    DIRECTION OUTPUT ;
    USE SIGNAL ;
    PORT
      LAYER M4 ;
        RECT  21.462 45.792 21.546 45.816 ;
    END
    PORT
      LAYER M4 ;
        RECT  21.516 45.792 21.593 45.816 ;
    END
  END q[320]
  PIN q[321]
    DIRECTION OUTPUT ;
    USE SIGNAL ;
    PORT
      LAYER M4 ;
        RECT  21.462 45.936 21.546 45.96 ;
    END
  END q[321]
  PIN q[322]
    DIRECTION OUTPUT ;
    USE SIGNAL ;
    PORT
      LAYER M4 ;
        RECT  21.462 46.08 21.546 46.104 ;
    END
  END q[322]
  PIN q[323]
    DIRECTION OUTPUT ;
    USE SIGNAL ;
    PORT
      LAYER M4 ;
        RECT  21.462 46.176 21.546 46.2 ;
    END
  END q[323]
  PIN q[324]
    DIRECTION OUTPUT ;
    USE SIGNAL ;
    PORT
      LAYER M4 ;
        RECT  21.462 46.32 21.546 46.344 ;
    END
  END q[324]
  PIN q[325]
    DIRECTION OUTPUT ;
    USE SIGNAL ;
    PORT
      LAYER M4 ;
        RECT  21.462 46.464 21.546 46.488 ;
    END
  END q[325]
  PIN q[326]
    DIRECTION OUTPUT ;
    USE SIGNAL ;
    PORT
      LAYER M4 ;
        RECT  21.462 46.56 21.546 46.584 ;
    END
  END q[326]
  PIN q[327]
    DIRECTION OUTPUT ;
    USE SIGNAL ;
    PORT
      LAYER M4 ;
        RECT  21.462 46.704 21.546 46.728 ;
    END
  END q[327]
  PIN q[328]
    DIRECTION OUTPUT ;
    USE SIGNAL ;
    PORT
      LAYER M4 ;
        RECT  21.462 46.8 21.546 46.824 ;
    END
  END q[328]
  PIN q[329]
    DIRECTION OUTPUT ;
    USE SIGNAL ;
    PORT
      LAYER M4 ;
        RECT  21.462 46.944 21.546 46.968 ;
    END
  END q[329]
  PIN q[32]
    DIRECTION OUTPUT ;
    USE SIGNAL ;
    PORT
      LAYER M4 ;
        RECT  21.462 9.408 21.546 9.432 ;
    END
  END q[32]
  PIN q[330]
    DIRECTION OUTPUT ;
    USE SIGNAL ;
    PORT
      LAYER M4 ;
        RECT  21.462 47.088 21.546 47.112 ;
    END
  END q[330]
  PIN q[331]
    DIRECTION OUTPUT ;
    USE SIGNAL ;
    PORT
      LAYER M4 ;
        RECT  21.462 47.184 21.546 47.208 ;
    END
  END q[331]
  PIN q[332]
    DIRECTION OUTPUT ;
    USE SIGNAL ;
    PORT
      LAYER M4 ;
        RECT  21.462 47.328 21.546 47.352 ;
    END
  END q[332]
  PIN q[333]
    DIRECTION OUTPUT ;
    USE SIGNAL ;
    PORT
      LAYER M4 ;
        RECT  21.462 47.472 21.546 47.496 ;
    END
  END q[333]
  PIN q[334]
    DIRECTION OUTPUT ;
    USE SIGNAL ;
    PORT
      LAYER M4 ;
        RECT  21.462 47.568 21.546 47.592 ;
    END
  END q[334]
  PIN q[335]
    DIRECTION OUTPUT ;
    USE SIGNAL ;
    PORT
      LAYER M4 ;
        RECT  21.462 47.712 21.546 47.736 ;
    END
  END q[335]
  PIN q[336]
    DIRECTION OUTPUT ;
    USE SIGNAL ;
    PORT
      LAYER M4 ;
        RECT  21.462 47.808 21.546 47.832 ;
    END
  END q[336]
  PIN q[337]
    DIRECTION OUTPUT ;
    USE SIGNAL ;
    PORT
      LAYER M4 ;
        RECT  21.462 47.952 21.546 47.976 ;
    END
  END q[337]
  PIN q[338]
    DIRECTION OUTPUT ;
    USE SIGNAL ;
    PORT
      LAYER M4 ;
        RECT  21.462 48.096 21.546 48.12 ;
    END
  END q[338]
  PIN q[339]
    DIRECTION OUTPUT ;
    USE SIGNAL ;
    PORT
      LAYER M4 ;
        RECT  21.462 48.192 21.546 48.216 ;
    END
  END q[339]
  PIN q[33]
    DIRECTION OUTPUT ;
    USE SIGNAL ;
    PORT
      LAYER M4 ;
        RECT  21.462 9.552 21.546 9.576 ;
    END
  END q[33]
  PIN q[340]
    DIRECTION OUTPUT ;
    USE SIGNAL ;
    PORT
      LAYER M4 ;
        RECT  21.462 48.336 21.546 48.36 ;
    END
  END q[340]
  PIN q[341]
    DIRECTION OUTPUT ;
    USE SIGNAL ;
    PORT
      LAYER M4 ;
        RECT  21.462 48.48 21.546 48.504 ;
    END
  END q[341]
  PIN q[342]
    DIRECTION OUTPUT ;
    USE SIGNAL ;
    PORT
      LAYER M4 ;
        RECT  21.462 48.576 21.546 48.6 ;
    END
  END q[342]
  PIN q[343]
    DIRECTION OUTPUT ;
    USE SIGNAL ;
    PORT
      LAYER M4 ;
        RECT  21.462 48.72 21.546 48.744 ;
    END
  END q[343]
  PIN q[344]
    DIRECTION OUTPUT ;
    USE SIGNAL ;
    PORT
      LAYER M4 ;
        RECT  21.462 48.864 21.546 48.888 ;
    END
  END q[344]
  PIN q[345]
    DIRECTION OUTPUT ;
    USE SIGNAL ;
    PORT
      LAYER M4 ;
        RECT  21.462 48.96 21.546 48.984 ;
    END
  END q[345]
  PIN q[346]
    DIRECTION OUTPUT ;
    USE SIGNAL ;
    PORT
      LAYER M4 ;
        RECT  21.462 49.104 21.546 49.128 ;
    END
  END q[346]
  PIN q[347]
    DIRECTION OUTPUT ;
    USE SIGNAL ;
    PORT
      LAYER M4 ;
        RECT  21.462 49.2 21.546 49.224 ;
    END
  END q[347]
  PIN q[348]
    DIRECTION OUTPUT ;
    USE SIGNAL ;
    PORT
      LAYER M4 ;
        RECT  21.462 49.344 21.546 49.368 ;
    END
  END q[348]
  PIN q[349]
    DIRECTION OUTPUT ;
    USE SIGNAL ;
    PORT
      LAYER M4 ;
        RECT  21.462 49.488 21.546 49.512 ;
    END
    PORT
      LAYER M4 ;
        RECT  21.516 49.488 21.593 49.512 ;
    END
  END q[349]
  PIN q[34]
    DIRECTION OUTPUT ;
    USE SIGNAL ;
    PORT
      LAYER M4 ;
        RECT  21.462 9.696 21.546 9.72 ;
    END
  END q[34]
  PIN q[350]
    DIRECTION OUTPUT ;
    USE SIGNAL ;
    PORT
      LAYER M4 ;
        RECT  21.462 49.584 21.546 49.608 ;
    END
  END q[350]
  PIN q[351]
    DIRECTION OUTPUT ;
    USE SIGNAL ;
    PORT
      LAYER M4 ;
        RECT  21.462 49.728 21.546 49.752 ;
    END
  END q[351]
  PIN q[352]
    DIRECTION OUTPUT ;
    USE SIGNAL ;
    PORT
      LAYER M4 ;
        RECT  21.462 49.872 21.546 49.896 ;
    END
  END q[352]
  PIN q[353]
    DIRECTION OUTPUT ;
    USE SIGNAL ;
    PORT
      LAYER M4 ;
        RECT  21.462 49.968 21.546 49.992 ;
    END
  END q[353]
  PIN q[354]
    DIRECTION OUTPUT ;
    USE SIGNAL ;
    PORT
      LAYER M4 ;
        RECT  21.462 50.112 21.546 50.136 ;
    END
  END q[354]
  PIN q[355]
    DIRECTION OUTPUT ;
    USE SIGNAL ;
    PORT
      LAYER M4 ;
        RECT  21.462 50.208 21.546 50.232 ;
    END
  END q[355]
  PIN q[356]
    DIRECTION OUTPUT ;
    USE SIGNAL ;
    PORT
      LAYER M4 ;
        RECT  21.462 50.352 21.546 50.376 ;
    END
  END q[356]
  PIN q[357]
    DIRECTION OUTPUT ;
    USE SIGNAL ;
    PORT
      LAYER M4 ;
        RECT  21.462 50.496 21.546 50.52 ;
    END
  END q[357]
  PIN q[358]
    DIRECTION OUTPUT ;
    USE SIGNAL ;
    PORT
      LAYER M4 ;
        RECT  21.462 50.592 21.546 50.616 ;
    END
  END q[358]
  PIN q[359]
    DIRECTION OUTPUT ;
    USE SIGNAL ;
    PORT
      LAYER M4 ;
        RECT  21.462 50.736 21.546 50.76 ;
    END
  END q[359]
  PIN q[35]
    DIRECTION OUTPUT ;
    USE SIGNAL ;
    PORT
      LAYER M4 ;
        RECT  21.462 9.792 21.546 9.816 ;
    END
  END q[35]
  PIN q[360]
    DIRECTION OUTPUT ;
    USE SIGNAL ;
    PORT
      LAYER M4 ;
        RECT  21.462 50.88 21.546 50.904 ;
    END
  END q[360]
  PIN q[361]
    DIRECTION OUTPUT ;
    USE SIGNAL ;
    PORT
      LAYER M4 ;
        RECT  21.462 50.976 21.546 51 ;
    END
  END q[361]
  PIN q[362]
    DIRECTION OUTPUT ;
    USE SIGNAL ;
    PORT
      LAYER M4 ;
        RECT  21.462 51.12 21.546 51.144 ;
    END
  END q[362]
  PIN q[363]
    DIRECTION OUTPUT ;
    USE SIGNAL ;
    PORT
      LAYER M4 ;
        RECT  21.462 51.264 21.546 51.288 ;
    END
  END q[363]
  PIN q[364]
    DIRECTION OUTPUT ;
    USE SIGNAL ;
    PORT
      LAYER M4 ;
        RECT  21.462 51.36 21.546 51.384 ;
    END
  END q[364]
  PIN q[365]
    DIRECTION OUTPUT ;
    USE SIGNAL ;
    PORT
      LAYER M4 ;
        RECT  21.462 51.504 21.546 51.528 ;
    END
  END q[365]
  PIN q[366]
    DIRECTION OUTPUT ;
    USE SIGNAL ;
    PORT
      LAYER M4 ;
        RECT  21.462 51.6 21.546 51.624 ;
    END
  END q[366]
  PIN q[367]
    DIRECTION OUTPUT ;
    USE SIGNAL ;
    PORT
      LAYER M4 ;
        RECT  21.462 51.744 21.546 51.768 ;
    END
    PORT
      LAYER M4 ;
        RECT  21.516 51.696 21.521 51.768 ;
    END
    PORT
      LAYER M4 ;
        RECT  21.521 51.744 21.593 51.768 ;
    END
  END q[367]
  PIN q[368]
    DIRECTION OUTPUT ;
    USE SIGNAL ;
    PORT
      LAYER M4 ;
        RECT  21.462 51.888 21.546 51.912 ;
    END
  END q[368]
  PIN q[369]
    DIRECTION OUTPUT ;
    USE SIGNAL ;
    PORT
      LAYER M4 ;
        RECT  21.462 51.984 21.546 52.008 ;
    END
  END q[369]
  PIN q[36]
    DIRECTION OUTPUT ;
    USE SIGNAL ;
    PORT
      LAYER M4 ;
        RECT  21.462 9.936 21.546 9.96 ;
    END
  END q[36]
  PIN q[370]
    DIRECTION OUTPUT ;
    USE SIGNAL ;
    PORT
      LAYER M4 ;
        RECT  21.462 52.128 21.546 52.152 ;
    END
  END q[370]
  PIN q[371]
    DIRECTION OUTPUT ;
    USE SIGNAL ;
    PORT
      LAYER M4 ;
        RECT  21.462 52.272 21.546 52.296 ;
    END
  END q[371]
  PIN q[372]
    DIRECTION OUTPUT ;
    USE SIGNAL ;
    PORT
      LAYER M4 ;
        RECT  21.462 52.368 21.546 52.392 ;
    END
  END q[372]
  PIN q[373]
    DIRECTION OUTPUT ;
    USE SIGNAL ;
    PORT
      LAYER M4 ;
        RECT  21.462 52.512 21.546 52.536 ;
    END
  END q[373]
  PIN q[374]
    DIRECTION OUTPUT ;
    USE SIGNAL ;
    PORT
      LAYER M4 ;
        RECT  21.462 52.608 21.546 52.632 ;
    END
  END q[374]
  PIN q[375]
    DIRECTION OUTPUT ;
    USE SIGNAL ;
    PORT
      LAYER M4 ;
        RECT  21.462 52.752 21.546 52.776 ;
    END
  END q[375]
  PIN q[376]
    DIRECTION OUTPUT ;
    USE SIGNAL ;
    PORT
      LAYER M4 ;
        RECT  21.462 52.896 21.546 52.92 ;
    END
  END q[376]
  PIN q[377]
    DIRECTION OUTPUT ;
    USE SIGNAL ;
    PORT
      LAYER M4 ;
        RECT  21.462 52.992 21.546 53.016 ;
    END
  END q[377]
  PIN q[378]
    DIRECTION OUTPUT ;
    USE SIGNAL ;
    PORT
      LAYER M4 ;
        RECT  21.462 53.136 21.546 53.16 ;
    END
  END q[378]
  PIN q[379]
    DIRECTION OUTPUT ;
    USE SIGNAL ;
    PORT
      LAYER M4 ;
        RECT  21.462 53.28 21.546 53.304 ;
    END
  END q[379]
  PIN q[37]
    DIRECTION OUTPUT ;
    USE SIGNAL ;
    PORT
      LAYER M4 ;
        RECT  21.462 10.08 21.546 10.104 ;
    END
  END q[37]
  PIN q[380]
    DIRECTION OUTPUT ;
    USE SIGNAL ;
    PORT
      LAYER M4 ;
        RECT  21.462 53.376 21.546 53.4 ;
    END
  END q[380]
  PIN q[381]
    DIRECTION OUTPUT ;
    USE SIGNAL ;
    PORT
      LAYER M4 ;
        RECT  21.462 53.52 21.546 53.544 ;
    END
  END q[381]
  PIN q[382]
    DIRECTION OUTPUT ;
    USE SIGNAL ;
    PORT
      LAYER M4 ;
        RECT  21.462 53.664 21.546 53.688 ;
    END
  END q[382]
  PIN q[383]
    DIRECTION OUTPUT ;
    USE SIGNAL ;
    PORT
      LAYER M4 ;
        RECT  21.462 53.76 21.546 53.784 ;
    END
  END q[383]
  PIN q[384]
    DIRECTION OUTPUT ;
    USE SIGNAL ;
    PORT
      LAYER M4 ;
        RECT  21.462 53.904 21.546 53.928 ;
    END
  END q[384]
  PIN q[385]
    DIRECTION OUTPUT ;
    USE SIGNAL ;
    PORT
      LAYER M4 ;
        RECT  21.462 54 21.546 54.024 ;
    END
  END q[385]
  PIN q[386]
    DIRECTION OUTPUT ;
    USE SIGNAL ;
    PORT
      LAYER M4 ;
        RECT  21.462 54.144 21.546 54.168 ;
    END
  END q[386]
  PIN q[387]
    DIRECTION OUTPUT ;
    USE SIGNAL ;
    PORT
      LAYER M4 ;
        RECT  21.462 54.288 21.546 54.312 ;
    END
  END q[387]
  PIN q[388]
    DIRECTION OUTPUT ;
    USE SIGNAL ;
    PORT
      LAYER M4 ;
        RECT  21.462 54.384 21.546 54.408 ;
    END
  END q[388]
  PIN q[389]
    DIRECTION OUTPUT ;
    USE SIGNAL ;
    PORT
      LAYER M4 ;
        RECT  21.462 54.528 21.546 54.552 ;
    END
  END q[389]
  PIN q[38]
    DIRECTION OUTPUT ;
    USE SIGNAL ;
    PORT
      LAYER M4 ;
        RECT  21.462 10.176 21.546 10.2 ;
    END
  END q[38]
  PIN q[390]
    DIRECTION OUTPUT ;
    USE SIGNAL ;
    PORT
      LAYER M4 ;
        RECT  21.462 54.672 21.546 54.696 ;
    END
  END q[390]
  PIN q[391]
    DIRECTION OUTPUT ;
    USE SIGNAL ;
    PORT
      LAYER M4 ;
        RECT  21.462 54.768 21.546 54.792 ;
    END
  END q[391]
  PIN q[392]
    DIRECTION OUTPUT ;
    USE SIGNAL ;
    PORT
      LAYER M4 ;
        RECT  21.462 54.912 21.546 54.936 ;
    END
  END q[392]
  PIN q[393]
    DIRECTION OUTPUT ;
    USE SIGNAL ;
    PORT
      LAYER M4 ;
        RECT  21.462 55.008 21.546 55.032 ;
    END
  END q[393]
  PIN q[394]
    DIRECTION OUTPUT ;
    USE SIGNAL ;
    PORT
      LAYER M4 ;
        RECT  21.462 55.152 21.546 55.176 ;
    END
  END q[394]
  PIN q[395]
    DIRECTION OUTPUT ;
    USE SIGNAL ;
    PORT
      LAYER M4 ;
        RECT  21.462 55.296 21.546 55.32 ;
    END
  END q[395]
  PIN q[396]
    DIRECTION OUTPUT ;
    USE SIGNAL ;
    PORT
      LAYER M4 ;
        RECT  21.462 55.392 21.546 55.416 ;
    END
  END q[396]
  PIN q[397]
    DIRECTION OUTPUT ;
    USE SIGNAL ;
    PORT
      LAYER M4 ;
        RECT  21.462 55.536 21.546 55.56 ;
    END
  END q[397]
  PIN q[398]
    DIRECTION OUTPUT ;
    USE SIGNAL ;
    PORT
      LAYER M4 ;
        RECT  21.462 55.68 21.546 55.704 ;
    END
  END q[398]
  PIN q[399]
    DIRECTION OUTPUT ;
    USE SIGNAL ;
    PORT
      LAYER M4 ;
        RECT  21.462 55.776 21.546 55.8 ;
    END
  END q[399]
  PIN q[39]
    DIRECTION OUTPUT ;
    USE SIGNAL ;
    PORT
      LAYER M4 ;
        RECT  21.462 10.32 21.546 10.344 ;
    END
  END q[39]
  PIN q[3]
    DIRECTION OUTPUT ;
    USE SIGNAL ;
    PORT
      LAYER M4 ;
        RECT  21.462 5.76 21.546 5.784 ;
    END
  END q[3]
  PIN q[400]
    DIRECTION OUTPUT ;
    USE SIGNAL ;
    PORT
      LAYER M4 ;
        RECT  21.462 55.92 21.546 55.944 ;
    END
  END q[400]
  PIN q[401]
    DIRECTION OUTPUT ;
    USE SIGNAL ;
    PORT
      LAYER M4 ;
        RECT  21.462 56.064 21.546 56.088 ;
    END
  END q[401]
  PIN q[402]
    DIRECTION OUTPUT ;
    USE SIGNAL ;
    PORT
      LAYER M4 ;
        RECT  21.462 56.16 21.546 56.184 ;
    END
  END q[402]
  PIN q[403]
    DIRECTION OUTPUT ;
    USE SIGNAL ;
    PORT
      LAYER M4 ;
        RECT  21.462 56.304 21.546 56.328 ;
    END
  END q[403]
  PIN q[404]
    DIRECTION OUTPUT ;
    USE SIGNAL ;
    PORT
      LAYER M4 ;
        RECT  21.462 56.4 21.546 56.424 ;
    END
  END q[404]
  PIN q[405]
    DIRECTION OUTPUT ;
    USE SIGNAL ;
    PORT
      LAYER M4 ;
        RECT  21.462 56.544 21.546 56.568 ;
    END
  END q[405]
  PIN q[406]
    DIRECTION OUTPUT ;
    USE SIGNAL ;
    PORT
      LAYER M4 ;
        RECT  21.462 56.688 21.546 56.712 ;
    END
  END q[406]
  PIN q[407]
    DIRECTION OUTPUT ;
    USE SIGNAL ;
    PORT
      LAYER M4 ;
        RECT  21.462 56.784 21.546 56.808 ;
    END
  END q[407]
  PIN q[408]
    DIRECTION OUTPUT ;
    USE SIGNAL ;
    PORT
      LAYER M4 ;
        RECT  21.462 56.928 21.546 56.952 ;
    END
  END q[408]
  PIN q[409]
    DIRECTION OUTPUT ;
    USE SIGNAL ;
    PORT
      LAYER M4 ;
        RECT  21.462 57.072 21.546 57.096 ;
    END
  END q[409]
  PIN q[40]
    DIRECTION OUTPUT ;
    USE SIGNAL ;
    PORT
      LAYER M4 ;
        RECT  21.462 10.464 21.546 10.488 ;
    END
  END q[40]
  PIN q[410]
    DIRECTION OUTPUT ;
    USE SIGNAL ;
    PORT
      LAYER M4 ;
        RECT  21.462 57.168 21.546 57.192 ;
    END
  END q[410]
  PIN q[411]
    DIRECTION OUTPUT ;
    USE SIGNAL ;
    PORT
      LAYER M4 ;
        RECT  21.462 57.312 21.546 57.336 ;
    END
  END q[411]
  PIN q[412]
    DIRECTION OUTPUT ;
    USE SIGNAL ;
    PORT
      LAYER M4 ;
        RECT  21.462 57.408 21.546 57.432 ;
    END
  END q[412]
  PIN q[413]
    DIRECTION OUTPUT ;
    USE SIGNAL ;
    PORT
      LAYER M4 ;
        RECT  21.462 57.552 21.546 57.576 ;
    END
  END q[413]
  PIN q[414]
    DIRECTION OUTPUT ;
    USE SIGNAL ;
    PORT
      LAYER M4 ;
        RECT  21.462 57.696 21.546 57.72 ;
    END
  END q[414]
  PIN q[415]
    DIRECTION OUTPUT ;
    USE SIGNAL ;
    PORT
      LAYER M4 ;
        RECT  21.462 57.792 21.546 57.816 ;
    END
  END q[415]
  PIN q[416]
    DIRECTION OUTPUT ;
    USE SIGNAL ;
    PORT
      LAYER M4 ;
        RECT  21.462 57.936 21.546 57.96 ;
    END
  END q[416]
  PIN q[417]
    DIRECTION OUTPUT ;
    USE SIGNAL ;
    PORT
      LAYER M4 ;
        RECT  21.462 58.08 21.546 58.104 ;
    END
  END q[417]
  PIN q[418]
    DIRECTION OUTPUT ;
    USE SIGNAL ;
    PORT
      LAYER M4 ;
        RECT  21.462 58.176 21.546 58.2 ;
    END
  END q[418]
  PIN q[419]
    DIRECTION OUTPUT ;
    USE SIGNAL ;
    PORT
      LAYER M4 ;
        RECT  21.462 58.32 21.546 58.344 ;
    END
  END q[419]
  PIN q[41]
    DIRECTION OUTPUT ;
    USE SIGNAL ;
    PORT
      LAYER M4 ;
        RECT  21.462 10.56 21.546 10.584 ;
    END
  END q[41]
  PIN q[420]
    DIRECTION OUTPUT ;
    USE SIGNAL ;
    PORT
      LAYER M4 ;
        RECT  21.462 58.464 21.546 58.488 ;
    END
  END q[420]
  PIN q[421]
    DIRECTION OUTPUT ;
    USE SIGNAL ;
    PORT
      LAYER M4 ;
        RECT  21.462 58.56 21.546 58.584 ;
    END
  END q[421]
  PIN q[422]
    DIRECTION OUTPUT ;
    USE SIGNAL ;
    PORT
      LAYER M4 ;
        RECT  21.462 58.704 21.546 58.728 ;
    END
  END q[422]
  PIN q[423]
    DIRECTION OUTPUT ;
    USE SIGNAL ;
    PORT
      LAYER M4 ;
        RECT  21.462 58.8 21.546 58.824 ;
    END
  END q[423]
  PIN q[424]
    DIRECTION OUTPUT ;
    USE SIGNAL ;
    PORT
      LAYER M4 ;
        RECT  21.462 58.944 21.546 58.968 ;
    END
  END q[424]
  PIN q[425]
    DIRECTION OUTPUT ;
    USE SIGNAL ;
    PORT
      LAYER M4 ;
        RECT  21.462 59.088 21.546 59.112 ;
    END
  END q[425]
  PIN q[426]
    DIRECTION OUTPUT ;
    USE SIGNAL ;
    PORT
      LAYER M4 ;
        RECT  21.462 59.184 21.546 59.208 ;
    END
  END q[426]
  PIN q[427]
    DIRECTION OUTPUT ;
    USE SIGNAL ;
    PORT
      LAYER M4 ;
        RECT  21.462 59.328 21.546 59.352 ;
    END
  END q[427]
  PIN q[428]
    DIRECTION OUTPUT ;
    USE SIGNAL ;
    PORT
      LAYER M4 ;
        RECT  21.462 59.472 21.546 59.496 ;
    END
  END q[428]
  PIN q[429]
    DIRECTION OUTPUT ;
    USE SIGNAL ;
    PORT
      LAYER M4 ;
        RECT  21.462 59.568 21.546 59.592 ;
    END
  END q[429]
  PIN q[42]
    DIRECTION OUTPUT ;
    USE SIGNAL ;
    PORT
      LAYER M4 ;
        RECT  21.462 10.704 21.546 10.728 ;
    END
  END q[42]
  PIN q[430]
    DIRECTION OUTPUT ;
    USE SIGNAL ;
    PORT
      LAYER M4 ;
        RECT  21.462 59.712 21.546 59.736 ;
    END
  END q[430]
  PIN q[431]
    DIRECTION OUTPUT ;
    USE SIGNAL ;
    PORT
      LAYER M4 ;
        RECT  21.462 59.808 21.546 59.832 ;
    END
  END q[431]
  PIN q[432]
    DIRECTION OUTPUT ;
    USE SIGNAL ;
    PORT
      LAYER M4 ;
        RECT  21.462 59.952 21.546 59.976 ;
    END
  END q[432]
  PIN q[433]
    DIRECTION OUTPUT ;
    USE SIGNAL ;
    PORT
      LAYER M4 ;
        RECT  21.462 60.096 21.546 60.12 ;
    END
  END q[433]
  PIN q[434]
    DIRECTION OUTPUT ;
    USE SIGNAL ;
    PORT
      LAYER M4 ;
        RECT  21.462 60.192 21.546 60.216 ;
    END
  END q[434]
  PIN q[435]
    DIRECTION OUTPUT ;
    USE SIGNAL ;
    PORT
      LAYER M4 ;
        RECT  21.462 60.336 21.546 60.36 ;
    END
  END q[435]
  PIN q[436]
    DIRECTION OUTPUT ;
    USE SIGNAL ;
    PORT
      LAYER M4 ;
        RECT  21.462 60.48 21.546 60.504 ;
    END
  END q[436]
  PIN q[437]
    DIRECTION OUTPUT ;
    USE SIGNAL ;
    PORT
      LAYER M4 ;
        RECT  21.462 60.576 21.546 60.6 ;
    END
  END q[437]
  PIN q[438]
    DIRECTION OUTPUT ;
    USE SIGNAL ;
    PORT
      LAYER M4 ;
        RECT  21.462 60.72 21.546 60.744 ;
    END
  END q[438]
  PIN q[439]
    DIRECTION OUTPUT ;
    USE SIGNAL ;
    PORT
      LAYER M4 ;
        RECT  21.462 60.864 21.546 60.888 ;
    END
  END q[439]
  PIN q[43]
    DIRECTION OUTPUT ;
    USE SIGNAL ;
    PORT
      LAYER M4 ;
        RECT  21.462 10.8 21.546 10.824 ;
    END
  END q[43]
  PIN q[440]
    DIRECTION OUTPUT ;
    USE SIGNAL ;
    PORT
      LAYER M4 ;
        RECT  21.462 60.96 21.546 60.984 ;
    END
  END q[440]
  PIN q[441]
    DIRECTION OUTPUT ;
    USE SIGNAL ;
    PORT
      LAYER M4 ;
        RECT  21.462 61.104 21.546 61.128 ;
    END
  END q[441]
  PIN q[442]
    DIRECTION OUTPUT ;
    USE SIGNAL ;
    PORT
      LAYER M4 ;
        RECT  21.462 61.2 21.546 61.224 ;
    END
  END q[442]
  PIN q[443]
    DIRECTION OUTPUT ;
    USE SIGNAL ;
    PORT
      LAYER M4 ;
        RECT  21.462 61.344 21.546 61.368 ;
    END
  END q[443]
  PIN q[444]
    DIRECTION OUTPUT ;
    USE SIGNAL ;
    PORT
      LAYER M4 ;
        RECT  21.462 61.488 21.546 61.512 ;
    END
  END q[444]
  PIN q[445]
    DIRECTION OUTPUT ;
    USE SIGNAL ;
    PORT
      LAYER M4 ;
        RECT  21.462 61.584 21.546 61.608 ;
    END
  END q[445]
  PIN q[446]
    DIRECTION OUTPUT ;
    USE SIGNAL ;
    PORT
      LAYER M4 ;
        RECT  21.462 61.728 21.546 61.752 ;
    END
  END q[446]
  PIN q[447]
    DIRECTION OUTPUT ;
    USE SIGNAL ;
    PORT
      LAYER M4 ;
        RECT  21.462 61.872 21.546 61.896 ;
    END
  END q[447]
  PIN q[448]
    DIRECTION OUTPUT ;
    USE SIGNAL ;
    PORT
      LAYER M4 ;
        RECT  21.462 61.968 21.546 61.992 ;
    END
  END q[448]
  PIN q[449]
    DIRECTION OUTPUT ;
    USE SIGNAL ;
    PORT
      LAYER M4 ;
        RECT  21.462 62.112 21.546 62.136 ;
    END
  END q[449]
  PIN q[44]
    DIRECTION OUTPUT ;
    USE SIGNAL ;
    PORT
      LAYER M4 ;
        RECT  21.462 10.944 21.546 10.968 ;
    END
  END q[44]
  PIN q[450]
    DIRECTION OUTPUT ;
    USE SIGNAL ;
    PORT
      LAYER M4 ;
        RECT  21.462 62.208 21.546 62.232 ;
    END
  END q[450]
  PIN q[451]
    DIRECTION OUTPUT ;
    USE SIGNAL ;
    PORT
      LAYER M4 ;
        RECT  21.462 62.352 21.546 62.376 ;
    END
  END q[451]
  PIN q[452]
    DIRECTION OUTPUT ;
    USE SIGNAL ;
    PORT
      LAYER M4 ;
        RECT  21.462 62.496 21.546 62.52 ;
    END
  END q[452]
  PIN q[453]
    DIRECTION OUTPUT ;
    USE SIGNAL ;
    PORT
      LAYER M4 ;
        RECT  21.462 62.592 21.546 62.616 ;
    END
  END q[453]
  PIN q[454]
    DIRECTION OUTPUT ;
    USE SIGNAL ;
    PORT
      LAYER M4 ;
        RECT  21.462 62.736 21.546 62.76 ;
    END
  END q[454]
  PIN q[455]
    DIRECTION OUTPUT ;
    USE SIGNAL ;
    PORT
      LAYER M4 ;
        RECT  21.462 62.88 21.546 62.904 ;
    END
  END q[455]
  PIN q[456]
    DIRECTION OUTPUT ;
    USE SIGNAL ;
    PORT
      LAYER M4 ;
        RECT  21.462 62.976 21.546 63 ;
    END
  END q[456]
  PIN q[457]
    DIRECTION OUTPUT ;
    USE SIGNAL ;
    PORT
      LAYER M4 ;
        RECT  21.462 63.12 21.546 63.144 ;
    END
  END q[457]
  PIN q[458]
    DIRECTION OUTPUT ;
    USE SIGNAL ;
    PORT
      LAYER M4 ;
        RECT  21.462 63.264 21.546 63.288 ;
    END
  END q[458]
  PIN q[459]
    DIRECTION OUTPUT ;
    USE SIGNAL ;
    PORT
      LAYER M4 ;
        RECT  21.462 63.36 21.546 63.384 ;
    END
  END q[459]
  PIN q[45]
    DIRECTION OUTPUT ;
    USE SIGNAL ;
    PORT
      LAYER M4 ;
        RECT  21.462 11.088 21.546 11.112 ;
    END
  END q[45]
  PIN q[460]
    DIRECTION OUTPUT ;
    USE SIGNAL ;
    PORT
      LAYER M4 ;
        RECT  21.462 63.504 21.546 63.528 ;
    END
  END q[460]
  PIN q[461]
    DIRECTION OUTPUT ;
    USE SIGNAL ;
    PORT
      LAYER M4 ;
        RECT  21.462 63.6 21.546 63.624 ;
    END
  END q[461]
  PIN q[462]
    DIRECTION OUTPUT ;
    USE SIGNAL ;
    PORT
      LAYER M4 ;
        RECT  21.462 63.744 21.546 63.768 ;
    END
  END q[462]
  PIN q[463]
    DIRECTION OUTPUT ;
    USE SIGNAL ;
    PORT
      LAYER M4 ;
        RECT  21.462 63.888 21.546 63.912 ;
    END
  END q[463]
  PIN q[464]
    DIRECTION OUTPUT ;
    USE SIGNAL ;
    PORT
      LAYER M4 ;
        RECT  21.462 63.984 21.546 64.008 ;
    END
  END q[464]
  PIN q[465]
    DIRECTION OUTPUT ;
    USE SIGNAL ;
    PORT
      LAYER M4 ;
        RECT  21.462 64.128 21.546 64.152 ;
    END
  END q[465]
  PIN q[466]
    DIRECTION OUTPUT ;
    USE SIGNAL ;
    PORT
      LAYER M4 ;
        RECT  21.462 64.272 21.546 64.296 ;
    END
  END q[466]
  PIN q[467]
    DIRECTION OUTPUT ;
    USE SIGNAL ;
    PORT
      LAYER M4 ;
        RECT  21.462 64.368 21.546 64.392 ;
    END
  END q[467]
  PIN q[468]
    DIRECTION OUTPUT ;
    USE SIGNAL ;
    PORT
      LAYER M4 ;
        RECT  21.462 64.512 21.546 64.536 ;
    END
  END q[468]
  PIN q[469]
    DIRECTION OUTPUT ;
    USE SIGNAL ;
    PORT
      LAYER M4 ;
        RECT  21.462 64.608 21.546 64.632 ;
    END
  END q[469]
  PIN q[46]
    DIRECTION OUTPUT ;
    USE SIGNAL ;
    PORT
      LAYER M4 ;
        RECT  21.462 11.184 21.546 11.208 ;
    END
  END q[46]
  PIN q[470]
    DIRECTION OUTPUT ;
    USE SIGNAL ;
    PORT
      LAYER M4 ;
        RECT  21.462 64.752 21.546 64.776 ;
    END
  END q[470]
  PIN q[471]
    DIRECTION OUTPUT ;
    USE SIGNAL ;
    PORT
      LAYER M4 ;
        RECT  21.462 64.896 21.546 64.92 ;
    END
  END q[471]
  PIN q[472]
    DIRECTION OUTPUT ;
    USE SIGNAL ;
    PORT
      LAYER M4 ;
        RECT  21.462 64.992 21.546 65.016 ;
    END
  END q[472]
  PIN q[473]
    DIRECTION OUTPUT ;
    USE SIGNAL ;
    PORT
      LAYER M4 ;
        RECT  21.462 65.136 21.546 65.16 ;
    END
  END q[473]
  PIN q[474]
    DIRECTION OUTPUT ;
    USE SIGNAL ;
    PORT
      LAYER M4 ;
        RECT  21.462 65.28 21.546 65.304 ;
    END
  END q[474]
  PIN q[475]
    DIRECTION OUTPUT ;
    USE SIGNAL ;
    PORT
      LAYER M4 ;
        RECT  21.462 65.376 21.546 65.4 ;
    END
  END q[475]
  PIN q[476]
    DIRECTION OUTPUT ;
    USE SIGNAL ;
    PORT
      LAYER M4 ;
        RECT  21.462 65.52 21.546 65.544 ;
    END
  END q[476]
  PIN q[477]
    DIRECTION OUTPUT ;
    USE SIGNAL ;
    PORT
      LAYER M4 ;
        RECT  21.462 65.664 21.546 65.688 ;
    END
  END q[477]
  PIN q[478]
    DIRECTION OUTPUT ;
    USE SIGNAL ;
    PORT
      LAYER M4 ;
        RECT  21.462 65.76 21.546 65.784 ;
    END
  END q[478]
  PIN q[479]
    DIRECTION OUTPUT ;
    USE SIGNAL ;
    PORT
      LAYER M4 ;
        RECT  21.462 65.904 21.546 65.928 ;
    END
  END q[479]
  PIN q[47]
    DIRECTION OUTPUT ;
    USE SIGNAL ;
    PORT
      LAYER M4 ;
        RECT  21.462 11.328 21.546 11.352 ;
    END
  END q[47]
  PIN q[480]
    DIRECTION OUTPUT ;
    USE SIGNAL ;
    PORT
      LAYER M4 ;
        RECT  21.462 66 21.546 66.024 ;
    END
  END q[480]
  PIN q[481]
    DIRECTION OUTPUT ;
    USE SIGNAL ;
    PORT
      LAYER M4 ;
        RECT  21.462 66.144 21.546 66.168 ;
    END
  END q[481]
  PIN q[482]
    DIRECTION OUTPUT ;
    USE SIGNAL ;
    PORT
      LAYER M4 ;
        RECT  21.462 66.288 21.546 66.312 ;
    END
  END q[482]
  PIN q[483]
    DIRECTION OUTPUT ;
    USE SIGNAL ;
    PORT
      LAYER M4 ;
        RECT  21.462 66.384 21.546 66.408 ;
    END
  END q[483]
  PIN q[484]
    DIRECTION OUTPUT ;
    USE SIGNAL ;
    PORT
      LAYER M4 ;
        RECT  21.462 66.528 21.546 66.552 ;
    END
  END q[484]
  PIN q[485]
    DIRECTION OUTPUT ;
    USE SIGNAL ;
    PORT
      LAYER M4 ;
        RECT  21.462 66.672 21.546 66.696 ;
    END
  END q[485]
  PIN q[486]
    DIRECTION OUTPUT ;
    USE SIGNAL ;
    PORT
      LAYER M4 ;
        RECT  21.462 66.768 21.546 66.792 ;
    END
  END q[486]
  PIN q[487]
    DIRECTION OUTPUT ;
    USE SIGNAL ;
    PORT
      LAYER M4 ;
        RECT  21.462 66.912 21.546 66.936 ;
    END
  END q[487]
  PIN q[488]
    DIRECTION OUTPUT ;
    USE SIGNAL ;
    PORT
      LAYER M4 ;
        RECT  21.462 67.008 21.546 67.032 ;
    END
  END q[488]
  PIN q[489]
    DIRECTION OUTPUT ;
    USE SIGNAL ;
    PORT
      LAYER M4 ;
        RECT  21.462 67.152 21.546 67.176 ;
    END
  END q[489]
  PIN q[48]
    DIRECTION OUTPUT ;
    USE SIGNAL ;
    PORT
      LAYER M4 ;
        RECT  21.462 11.472 21.546 11.496 ;
    END
  END q[48]
  PIN q[490]
    DIRECTION OUTPUT ;
    USE SIGNAL ;
    PORT
      LAYER M4 ;
        RECT  21.462 67.296 21.546 67.32 ;
    END
  END q[490]
  PIN q[491]
    DIRECTION OUTPUT ;
    USE SIGNAL ;
    PORT
      LAYER M4 ;
        RECT  21.462 67.392 21.546 67.416 ;
    END
  END q[491]
  PIN q[492]
    DIRECTION OUTPUT ;
    USE SIGNAL ;
    PORT
      LAYER M4 ;
        RECT  21.462 67.536 21.546 67.56 ;
    END
  END q[492]
  PIN q[493]
    DIRECTION OUTPUT ;
    USE SIGNAL ;
    PORT
      LAYER M4 ;
        RECT  21.462 67.68 21.546 67.704 ;
    END
  END q[493]
  PIN q[494]
    DIRECTION OUTPUT ;
    USE SIGNAL ;
    PORT
      LAYER M4 ;
        RECT  21.462 67.776 21.546 67.8 ;
    END
  END q[494]
  PIN q[495]
    DIRECTION OUTPUT ;
    USE SIGNAL ;
    PORT
      LAYER M4 ;
        RECT  21.462 67.92 21.546 67.944 ;
    END
  END q[495]
  PIN q[496]
    DIRECTION OUTPUT ;
    USE SIGNAL ;
    PORT
      LAYER M4 ;
        RECT  21.462 68.064 21.546 68.088 ;
    END
  END q[496]
  PIN q[497]
    DIRECTION OUTPUT ;
    USE SIGNAL ;
    PORT
      LAYER M4 ;
        RECT  21.462 68.16 21.546 68.184 ;
    END
  END q[497]
  PIN q[498]
    DIRECTION OUTPUT ;
    USE SIGNAL ;
    PORT
      LAYER M4 ;
        RECT  21.462 68.304 21.546 68.328 ;
    END
  END q[498]
  PIN q[499]
    DIRECTION OUTPUT ;
    USE SIGNAL ;
    PORT
      LAYER M4 ;
        RECT  21.462 68.4 21.546 68.424 ;
    END
  END q[499]
  PIN q[49]
    DIRECTION OUTPUT ;
    USE SIGNAL ;
    PORT
      LAYER M4 ;
        RECT  21.462 11.568 21.546 11.592 ;
    END
  END q[49]
  PIN q[4]
    DIRECTION OUTPUT ;
    USE SIGNAL ;
    PORT
      LAYER M4 ;
        RECT  21.462 5.904 21.546 5.928 ;
    END
  END q[4]
  PIN q[500]
    DIRECTION OUTPUT ;
    USE SIGNAL ;
    PORT
      LAYER M4 ;
        RECT  21.462 68.544 21.546 68.568 ;
    END
  END q[500]
  PIN q[501]
    DIRECTION OUTPUT ;
    USE SIGNAL ;
    PORT
      LAYER M4 ;
        RECT  21.462 68.688 21.546 68.712 ;
    END
  END q[501]
  PIN q[502]
    DIRECTION OUTPUT ;
    USE SIGNAL ;
    PORT
      LAYER M4 ;
        RECT  21.462 68.784 21.546 68.808 ;
    END
  END q[502]
  PIN q[503]
    DIRECTION OUTPUT ;
    USE SIGNAL ;
    PORT
      LAYER M4 ;
        RECT  21.462 68.928 21.546 68.952 ;
    END
  END q[503]
  PIN q[504]
    DIRECTION OUTPUT ;
    USE SIGNAL ;
    PORT
      LAYER M4 ;
        RECT  21.462 69.072 21.546 69.096 ;
    END
  END q[504]
  PIN q[505]
    DIRECTION OUTPUT ;
    USE SIGNAL ;
    PORT
      LAYER M4 ;
        RECT  21.462 69.168 21.546 69.192 ;
    END
  END q[505]
  PIN q[506]
    DIRECTION OUTPUT ;
    USE SIGNAL ;
    PORT
      LAYER M4 ;
        RECT  21.462 69.312 21.546 69.336 ;
    END
  END q[506]
  PIN q[507]
    DIRECTION OUTPUT ;
    USE SIGNAL ;
    PORT
      LAYER M4 ;
        RECT  21.462 69.408 21.546 69.432 ;
    END
  END q[507]
  PIN q[508]
    DIRECTION OUTPUT ;
    USE SIGNAL ;
    PORT
      LAYER M4 ;
        RECT  21.462 69.552 21.546 69.576 ;
    END
  END q[508]
  PIN q[509]
    DIRECTION OUTPUT ;
    USE SIGNAL ;
    PORT
      LAYER M4 ;
        RECT  21.462 69.696 21.546 69.72 ;
    END
  END q[509]
  PIN q[50]
    DIRECTION OUTPUT ;
    USE SIGNAL ;
    PORT
      LAYER M4 ;
        RECT  21.462 11.712 21.546 11.736 ;
    END
  END q[50]
  PIN q[510]
    DIRECTION OUTPUT ;
    USE SIGNAL ;
    PORT
      LAYER M4 ;
        RECT  21.462 69.792 21.546 69.816 ;
    END
  END q[510]
  PIN q[511]
    DIRECTION OUTPUT ;
    USE SIGNAL ;
    PORT
      LAYER M4 ;
        RECT  21.462 69.936 21.546 69.96 ;
    END
  END q[511]
  PIN q[51]
    DIRECTION OUTPUT ;
    USE SIGNAL ;
    PORT
      LAYER M4 ;
        RECT  21.462 11.808 21.546 11.832 ;
    END
  END q[51]
  PIN q[52]
    DIRECTION OUTPUT ;
    USE SIGNAL ;
    PORT
      LAYER M4 ;
        RECT  21.462 11.952 21.546 11.976 ;
    END
  END q[52]
  PIN q[53]
    DIRECTION OUTPUT ;
    USE SIGNAL ;
    PORT
      LAYER M4 ;
        RECT  21.462 12.096 21.546 12.12 ;
    END
  END q[53]
  PIN q[54]
    DIRECTION OUTPUT ;
    USE SIGNAL ;
    PORT
      LAYER M4 ;
        RECT  21.462 12.192 21.546 12.216 ;
    END
  END q[54]
  PIN q[55]
    DIRECTION OUTPUT ;
    USE SIGNAL ;
    PORT
      LAYER M4 ;
        RECT  21.462 12.336 21.546 12.36 ;
    END
  END q[55]
  PIN q[56]
    DIRECTION OUTPUT ;
    USE SIGNAL ;
    PORT
      LAYER M4 ;
        RECT  21.462 12.48 21.546 12.504 ;
    END
  END q[56]
  PIN q[57]
    DIRECTION OUTPUT ;
    USE SIGNAL ;
    PORT
      LAYER M4 ;
        RECT  21.462 12.576 21.546 12.6 ;
    END
  END q[57]
  PIN q[58]
    DIRECTION OUTPUT ;
    USE SIGNAL ;
    PORT
      LAYER M4 ;
        RECT  21.462 12.72 21.546 12.744 ;
    END
  END q[58]
  PIN q[59]
    DIRECTION OUTPUT ;
    USE SIGNAL ;
    PORT
      LAYER M4 ;
        RECT  21.462 12.864 21.546 12.888 ;
    END
  END q[59]
  PIN q[5]
    DIRECTION OUTPUT ;
    USE SIGNAL ;
    PORT
      LAYER M4 ;
        RECT  21.462 6 21.546 6.024 ;
    END
  END q[5]
  PIN q[60]
    DIRECTION OUTPUT ;
    USE SIGNAL ;
    PORT
      LAYER M4 ;
        RECT  21.462 12.96 21.546 12.984 ;
    END
  END q[60]
  PIN q[61]
    DIRECTION OUTPUT ;
    USE SIGNAL ;
    PORT
      LAYER M4 ;
        RECT  21.462 13.104 21.546 13.128 ;
    END
  END q[61]
  PIN q[62]
    DIRECTION OUTPUT ;
    USE SIGNAL ;
    PORT
      LAYER M4 ;
        RECT  21.462 13.2 21.546 13.224 ;
    END
  END q[62]
  PIN q[63]
    DIRECTION OUTPUT ;
    USE SIGNAL ;
    PORT
      LAYER M4 ;
        RECT  21.462 13.344 21.546 13.368 ;
    END
  END q[63]
  PIN q[64]
    DIRECTION OUTPUT ;
    USE SIGNAL ;
    PORT
      LAYER M4 ;
        RECT  21.462 13.488 21.546 13.512 ;
    END
  END q[64]
  PIN q[65]
    DIRECTION OUTPUT ;
    USE SIGNAL ;
    PORT
      LAYER M4 ;
        RECT  21.462 13.584 21.546 13.608 ;
    END
  END q[65]
  PIN q[66]
    DIRECTION OUTPUT ;
    USE SIGNAL ;
    PORT
      LAYER M4 ;
        RECT  21.462 13.728 21.546 13.752 ;
    END
  END q[66]
  PIN q[67]
    DIRECTION OUTPUT ;
    USE SIGNAL ;
    PORT
      LAYER M4 ;
        RECT  21.462 13.872 21.546 13.896 ;
    END
  END q[67]
  PIN q[68]
    DIRECTION OUTPUT ;
    USE SIGNAL ;
    PORT
      LAYER M4 ;
        RECT  21.462 13.968 21.546 13.992 ;
    END
  END q[68]
  PIN q[69]
    DIRECTION OUTPUT ;
    USE SIGNAL ;
    PORT
      LAYER M4 ;
        RECT  21.462 14.112 21.546 14.136 ;
    END
  END q[69]
  PIN q[6]
    DIRECTION OUTPUT ;
    USE SIGNAL ;
    PORT
      LAYER M4 ;
        RECT  21.462 6.144 21.546 6.168 ;
    END
  END q[6]
  PIN q[70]
    DIRECTION OUTPUT ;
    USE SIGNAL ;
    PORT
      LAYER M4 ;
        RECT  21.462 14.208 21.546 14.232 ;
    END
  END q[70]
  PIN q[71]
    DIRECTION OUTPUT ;
    USE SIGNAL ;
    PORT
      LAYER M4 ;
        RECT  21.462 14.352 21.546 14.376 ;
    END
  END q[71]
  PIN q[72]
    DIRECTION OUTPUT ;
    USE SIGNAL ;
    PORT
      LAYER M4 ;
        RECT  21.462 14.496 21.546 14.52 ;
    END
  END q[72]
  PIN q[73]
    DIRECTION OUTPUT ;
    USE SIGNAL ;
    PORT
      LAYER M4 ;
        RECT  21.462 14.592 21.546 14.616 ;
    END
  END q[73]
  PIN q[74]
    DIRECTION OUTPUT ;
    USE SIGNAL ;
    PORT
      LAYER M4 ;
        RECT  21.462 14.736 21.546 14.76 ;
    END
  END q[74]
  PIN q[75]
    DIRECTION OUTPUT ;
    USE SIGNAL ;
    PORT
      LAYER M4 ;
        RECT  21.462 14.88 21.546 14.904 ;
    END
  END q[75]
  PIN q[76]
    DIRECTION OUTPUT ;
    USE SIGNAL ;
    PORT
      LAYER M4 ;
        RECT  21.462 14.976 21.546 15 ;
    END
  END q[76]
  PIN q[77]
    DIRECTION OUTPUT ;
    USE SIGNAL ;
    PORT
      LAYER M4 ;
        RECT  21.462 15.12 21.546 15.144 ;
    END
  END q[77]
  PIN q[78]
    DIRECTION OUTPUT ;
    USE SIGNAL ;
    PORT
      LAYER M4 ;
        RECT  21.462 15.264 21.546 15.288 ;
    END
  END q[78]
  PIN q[79]
    DIRECTION OUTPUT ;
    USE SIGNAL ;
    PORT
      LAYER M4 ;
        RECT  21.462 15.36 21.546 15.384 ;
    END
  END q[79]
  PIN q[7]
    DIRECTION OUTPUT ;
    USE SIGNAL ;
    PORT
      LAYER M4 ;
        RECT  21.462 6.288 21.546 6.312 ;
    END
  END q[7]
  PIN q[80]
    DIRECTION OUTPUT ;
    USE SIGNAL ;
    PORT
      LAYER M4 ;
        RECT  21.462 15.504 21.546 15.528 ;
    END
  END q[80]
  PIN q[81]
    DIRECTION OUTPUT ;
    USE SIGNAL ;
    PORT
      LAYER M4 ;
        RECT  21.462 15.6 21.546 15.624 ;
    END
  END q[81]
  PIN q[82]
    DIRECTION OUTPUT ;
    USE SIGNAL ;
    PORT
      LAYER M4 ;
        RECT  21.462 15.744 21.546 15.768 ;
    END
  END q[82]
  PIN q[83]
    DIRECTION OUTPUT ;
    USE SIGNAL ;
    PORT
      LAYER M4 ;
        RECT  21.462 15.888 21.546 15.912 ;
    END
  END q[83]
  PIN q[84]
    DIRECTION OUTPUT ;
    USE SIGNAL ;
    PORT
      LAYER M4 ;
        RECT  21.462 15.984 21.546 16.008 ;
    END
  END q[84]
  PIN q[85]
    DIRECTION OUTPUT ;
    USE SIGNAL ;
    PORT
      LAYER M4 ;
        RECT  21.462 16.128 21.546 16.152 ;
    END
  END q[85]
  PIN q[86]
    DIRECTION OUTPUT ;
    USE SIGNAL ;
    PORT
      LAYER M4 ;
        RECT  21.462 16.272 21.546 16.296 ;
    END
  END q[86]
  PIN q[87]
    DIRECTION OUTPUT ;
    USE SIGNAL ;
    PORT
      LAYER M4 ;
        RECT  21.462 16.368 21.546 16.392 ;
    END
  END q[87]
  PIN q[88]
    DIRECTION OUTPUT ;
    USE SIGNAL ;
    PORT
      LAYER M4 ;
        RECT  21.462 16.512 21.546 16.536 ;
    END
  END q[88]
  PIN q[89]
    DIRECTION OUTPUT ;
    USE SIGNAL ;
    PORT
      LAYER M4 ;
        RECT  21.462 16.608 21.546 16.632 ;
    END
  END q[89]
  PIN q[8]
    DIRECTION OUTPUT ;
    USE SIGNAL ;
    PORT
      LAYER M4 ;
        RECT  21.462 6.384 21.546 6.408 ;
    END
  END q[8]
  PIN q[90]
    DIRECTION OUTPUT ;
    USE SIGNAL ;
    PORT
      LAYER M4 ;
        RECT  21.462 16.752 21.546 16.776 ;
    END
  END q[90]
  PIN q[91]
    DIRECTION OUTPUT ;
    USE SIGNAL ;
    PORT
      LAYER M4 ;
        RECT  21.462 16.896 21.546 16.92 ;
    END
  END q[91]
  PIN q[92]
    DIRECTION OUTPUT ;
    USE SIGNAL ;
    PORT
      LAYER M4 ;
        RECT  21.462 16.992 21.546 17.016 ;
    END
  END q[92]
  PIN q[93]
    DIRECTION OUTPUT ;
    USE SIGNAL ;
    PORT
      LAYER M4 ;
        RECT  21.462 17.136 21.546 17.16 ;
    END
  END q[93]
  PIN q[94]
    DIRECTION OUTPUT ;
    USE SIGNAL ;
    PORT
      LAYER M4 ;
        RECT  21.462 17.28 21.546 17.304 ;
    END
  END q[94]
  PIN q[95]
    DIRECTION OUTPUT ;
    USE SIGNAL ;
    PORT
      LAYER M4 ;
        RECT  21.462 17.376 21.546 17.4 ;
    END
  END q[95]
  PIN q[96]
    DIRECTION OUTPUT ;
    USE SIGNAL ;
    PORT
      LAYER M4 ;
        RECT  21.462 17.52 21.546 17.544 ;
    END
  END q[96]
  PIN q[97]
    DIRECTION OUTPUT ;
    USE SIGNAL ;
    PORT
      LAYER M4 ;
        RECT  21.462 17.664 21.546 17.688 ;
    END
  END q[97]
  PIN q[98]
    DIRECTION OUTPUT ;
    USE SIGNAL ;
    PORT
      LAYER M4 ;
        RECT  21.462 17.76 21.546 17.784 ;
    END
  END q[98]
  PIN q[99]
    DIRECTION OUTPUT ;
    USE SIGNAL ;
    PORT
      LAYER M4 ;
        RECT  21.462 17.904 21.546 17.928 ;
    END
  END q[99]
  PIN q[9]
    DIRECTION OUTPUT ;
    USE SIGNAL ;
    PORT
      LAYER M4 ;
        RECT  21.462 6.528 21.546 6.552 ;
    END
  END q[9]
  PIN VDD
    DIRECTION INOUT ;
    USE POWER ;
    PORT
      LAYER M5 ;
        RECT  18.792 2.151 18.912 73.449 ;
        RECT  16.092 2.151 16.212 73.449 ;
        RECT  13.392 2.151 13.512 73.449 ;
        RECT  10.692 2.151 10.812 73.449 ;
        RECT  7.992 2.151 8.112 73.449 ;
        RECT  5.292 2.151 5.412 73.449 ;
        RECT  2.592 2.151 2.712 73.449 ;
    END
  END VDD
  PIN VSS
    DIRECTION INOUT ;
    USE GROUND ;
    PORT
      LAYER M5 ;
        RECT  18.6 2.137 18.72 73.463 ;
        RECT  15.9 2.137 16.02 73.463 ;
        RECT  13.2 2.137 13.32 73.463 ;
        RECT  10.5 2.137 10.62 73.463 ;
        RECT  7.8 2.137 7.92 73.463 ;
        RECT  5.1 2.137 5.22 73.463 ;
        RECT  2.4 2.137 2.52 73.463 ;
    END
  END VSS
  # OT_OBS_CLOSED layer=M5 d_um=1.536 added=45
  OBS
    LAYER RVTN ;
     RECT  2.16 2.16 19.44 2.295 ;
     RECT  2.16 2.565 19.44 2.835 ;
     RECT  2.16 3.105 19.44 3.375 ;
     RECT  2.16 3.645 19.44 3.915 ;
     RECT  2.16 4.185 19.44 4.455 ;
     RECT  2.16 4.725 19.44 4.995 ;
     RECT  2.16 5.265 19.44 5.535 ;
     RECT  2.16 5.805 19.44 6.075 ;
     RECT  2.16 6.345 19.44 6.615 ;
     RECT  2.16 6.885 19.44 7.155 ;
     RECT  2.16 7.425 19.44 7.695 ;
     RECT  2.16 7.965 19.44 8.235 ;
     RECT  2.16 8.505 19.44 8.775 ;
     RECT  2.16 9.045 19.44 9.315 ;
     RECT  2.16 9.585 19.44 9.855 ;
     RECT  2.16 10.125 19.44 10.395 ;
     RECT  2.16 10.665 19.44 10.935 ;
     RECT  2.16 11.205 19.44 11.475 ;
     RECT  2.16 11.745 19.44 12.015 ;
     RECT  2.16 12.285 19.44 12.555 ;
     RECT  2.16 12.825 19.44 13.095 ;
     RECT  2.16 13.365 19.44 13.635 ;
     RECT  2.16 13.905 19.44 14.175 ;
     RECT  2.16 14.445 19.44 14.715 ;
     RECT  2.16 14.985 19.44 15.255 ;
     RECT  2.16 15.525 19.44 15.795 ;
     RECT  2.16 16.065 19.44 16.335 ;
     RECT  2.16 16.605 19.44 16.875 ;
     RECT  2.16 17.145 19.44 17.415 ;
     RECT  2.16 17.685 19.44 17.955 ;
     RECT  2.16 18.225 19.44 18.495 ;
     RECT  2.16 18.765 19.44 19.035 ;
     RECT  2.16 19.305 19.44 19.575 ;
     RECT  2.16 19.845 19.44 20.115 ;
     RECT  2.16 20.385 19.44 20.655 ;
     RECT  2.16 20.925 19.44 21.195 ;
     RECT  2.16 21.465 19.44 21.735 ;
     RECT  2.16 22.005 19.44 22.275 ;
     RECT  2.16 22.545 19.44 22.815 ;
     RECT  2.16 23.085 19.44 23.355 ;
     RECT  2.16 23.625 19.44 23.895 ;
     RECT  2.16 24.165 19.44 24.435 ;
     RECT  2.16 24.705 19.44 24.975 ;
     RECT  2.16 25.245 19.44 25.515 ;
     RECT  2.16 25.785 19.44 26.055 ;
     RECT  2.16 26.325 19.44 26.595 ;
     RECT  2.16 26.865 19.44 27.135 ;
     RECT  2.16 27.405 19.44 27.675 ;
     RECT  2.16 27.945 19.44 28.215 ;
     RECT  2.16 28.485 19.44 28.755 ;
     RECT  2.16 29.025 19.44 29.295 ;
     RECT  2.16 29.565 19.44 29.835 ;
     RECT  2.16 30.105 19.44 30.375 ;
     RECT  2.16 30.645 19.44 30.915 ;
     RECT  2.16 31.185 19.44 31.455 ;
     RECT  2.16 31.725 19.44 31.995 ;
     RECT  2.16 32.265 19.44 32.535 ;
     RECT  2.16 32.805 19.44 33.075 ;
     RECT  2.16 33.345 19.44 33.615 ;
     RECT  2.16 33.885 19.44 34.155 ;
     RECT  2.16 34.425 19.44 34.695 ;
     RECT  2.16 34.965 19.44 35.235 ;
     RECT  2.16 35.505 19.44 35.775 ;
     RECT  2.16 36.045 19.44 36.315 ;
     RECT  2.16 36.585 19.44 36.855 ;
     RECT  2.16 37.125 19.44 37.395 ;
     RECT  2.16 37.665 19.44 37.935 ;
     RECT  2.16 38.205 19.44 38.475 ;
     RECT  2.16 38.745 19.44 39.015 ;
     RECT  2.16 39.285 19.44 39.555 ;
     RECT  2.16 39.825 19.44 40.095 ;
     RECT  2.16 40.365 19.44 40.635 ;
     RECT  2.16 40.905 19.44 41.175 ;
     RECT  2.16 41.445 19.44 41.715 ;
     RECT  2.16 41.985 19.44 42.255 ;
     RECT  2.16 42.525 19.44 42.795 ;
     RECT  2.16 43.065 19.44 43.335 ;
     RECT  2.16 43.605 19.44 43.875 ;
     RECT  2.16 44.145 19.44 44.415 ;
     RECT  2.16 44.685 19.44 44.955 ;
     RECT  2.16 45.225 19.44 45.495 ;
     RECT  2.16 45.765 19.44 46.035 ;
     RECT  2.16 46.305 19.44 46.575 ;
     RECT  2.16 46.845 19.44 47.115 ;
     RECT  2.16 47.385 19.44 47.655 ;
     RECT  2.16 47.925 19.44 48.195 ;
     RECT  2.16 48.465 19.44 48.735 ;
     RECT  2.16 49.005 19.44 49.275 ;
     RECT  2.16 49.545 19.44 49.815 ;
     RECT  2.16 50.085 19.44 50.355 ;
     RECT  2.16 50.625 19.44 50.895 ;
     RECT  2.16 51.165 19.44 51.435 ;
     RECT  2.16 51.705 19.44 51.975 ;
     RECT  2.16 52.245 19.44 52.515 ;
     RECT  2.16 52.785 19.44 53.055 ;
     RECT  2.16 53.325 19.44 53.595 ;
     RECT  2.16 53.865 19.44 54.135 ;
     RECT  2.16 54.405 19.44 54.675 ;
     RECT  2.16 54.945 19.44 55.215 ;
     RECT  2.16 55.485 19.44 55.755 ;
     RECT  2.16 56.025 19.44 56.295 ;
     RECT  2.16 56.565 19.44 56.835 ;
     RECT  2.16 57.105 19.44 57.375 ;
     RECT  2.16 57.645 19.44 57.915 ;
     RECT  2.16 58.185 19.44 58.455 ;
     RECT  2.16 58.725 19.44 58.995 ;
     RECT  2.16 59.265 19.44 59.535 ;
     RECT  2.16 59.805 19.44 60.075 ;
     RECT  2.16 60.345 19.44 60.615 ;
     RECT  2.16 60.885 19.44 61.155 ;
     RECT  2.16 61.425 19.44 61.695 ;
     RECT  2.16 61.965 19.44 62.235 ;
     RECT  2.16 62.505 19.44 62.775 ;
     RECT  2.16 63.045 19.44 63.315 ;
     RECT  2.16 63.585 19.44 63.855 ;
     RECT  2.16 64.125 19.44 64.395 ;
     RECT  2.16 64.665 19.44 64.935 ;
     RECT  2.16 65.205 19.44 65.475 ;
     RECT  2.16 65.745 19.44 66.015 ;
     RECT  2.16 66.285 19.44 66.555 ;
     RECT  2.16 66.825 19.44 67.095 ;
     RECT  2.16 67.365 19.44 67.635 ;
     RECT  2.16 67.905 19.44 68.175 ;
     RECT  2.16 68.445 19.44 68.715 ;
     RECT  2.16 68.985 19.44 69.255 ;
     RECT  2.16 69.525 19.44 69.795 ;
     RECT  2.16 70.065 19.44 70.335 ;
     RECT  2.16 70.605 19.44 70.875 ;
     RECT  2.16 71.145 19.44 71.415 ;
     RECT  2.16 71.685 19.44 71.955 ;
     RECT  2.16 72.225 19.44 72.495 ;
     RECT  2.16 72.765 19.44 73.035 ;
     RECT  2.16 73.305 19.44 73.44 ;
    LAYER RVTP ;
     RECT  2.16 2.295 19.44 2.565 ;
     RECT  2.16 2.835 19.44 3.105 ;
     RECT  2.16 3.375 19.44 3.645 ;
     RECT  2.16 3.915 19.44 4.185 ;
     RECT  2.16 4.455 19.44 4.725 ;
     RECT  2.16 4.995 19.44 5.265 ;
     RECT  2.16 5.535 19.44 5.805 ;
     RECT  2.16 6.075 19.44 6.345 ;
     RECT  2.16 6.615 19.44 6.885 ;
     RECT  2.16 7.155 19.44 7.425 ;
     RECT  2.16 7.695 19.44 7.965 ;
     RECT  2.16 8.235 19.44 8.505 ;
     RECT  2.16 8.775 19.44 9.045 ;
     RECT  2.16 9.315 19.44 9.585 ;
     RECT  2.16 9.855 19.44 10.125 ;
     RECT  2.16 10.395 19.44 10.665 ;
     RECT  2.16 10.935 19.44 11.205 ;
     RECT  2.16 11.475 19.44 11.745 ;
     RECT  2.16 12.015 19.44 12.285 ;
     RECT  2.16 12.555 19.44 12.825 ;
     RECT  2.16 13.095 19.44 13.365 ;
     RECT  2.16 13.635 19.44 13.905 ;
     RECT  2.16 14.175 19.44 14.445 ;
     RECT  2.16 14.715 19.44 14.985 ;
     RECT  2.16 15.255 19.44 15.525 ;
     RECT  2.16 15.795 19.44 16.065 ;
     RECT  2.16 16.335 19.44 16.605 ;
     RECT  2.16 16.875 19.44 17.145 ;
     RECT  2.16 17.415 19.44 17.685 ;
     RECT  2.16 17.955 19.44 18.225 ;
     RECT  2.16 18.495 19.44 18.765 ;
     RECT  2.16 19.035 19.44 19.305 ;
     RECT  2.16 19.575 19.44 19.845 ;
     RECT  2.16 20.115 19.44 20.385 ;
     RECT  2.16 20.655 19.44 20.925 ;
     RECT  2.16 21.195 19.44 21.465 ;
     RECT  2.16 21.735 19.44 22.005 ;
     RECT  2.16 22.275 19.44 22.545 ;
     RECT  2.16 22.815 19.44 23.085 ;
     RECT  2.16 23.355 19.44 23.625 ;
     RECT  2.16 23.895 19.44 24.165 ;
     RECT  2.16 24.435 19.44 24.705 ;
     RECT  2.16 24.975 19.44 25.245 ;
     RECT  2.16 25.515 19.44 25.785 ;
     RECT  2.16 26.055 19.44 26.325 ;
     RECT  2.16 26.595 19.44 26.865 ;
     RECT  2.16 27.135 19.44 27.405 ;
     RECT  2.16 27.675 19.44 27.945 ;
     RECT  2.16 28.215 19.44 28.485 ;
     RECT  2.16 28.755 19.44 29.025 ;
     RECT  2.16 29.295 19.44 29.565 ;
     RECT  2.16 29.835 19.44 30.105 ;
     RECT  2.16 30.375 19.44 30.645 ;
     RECT  2.16 30.915 19.44 31.185 ;
     RECT  2.16 31.455 19.44 31.725 ;
     RECT  2.16 31.995 19.44 32.265 ;
     RECT  2.16 32.535 19.44 32.805 ;
     RECT  2.16 33.075 19.44 33.345 ;
     RECT  2.16 33.615 19.44 33.885 ;
     RECT  2.16 34.155 19.44 34.425 ;
     RECT  2.16 34.695 19.44 34.965 ;
     RECT  2.16 35.235 19.44 35.505 ;
     RECT  2.16 35.775 19.44 36.045 ;
     RECT  2.16 36.315 19.44 36.585 ;
     RECT  2.16 36.855 19.44 37.125 ;
     RECT  2.16 37.395 19.44 37.665 ;
     RECT  2.16 37.935 19.44 38.205 ;
     RECT  2.16 38.475 19.44 38.745 ;
     RECT  2.16 39.015 19.44 39.285 ;
     RECT  2.16 39.555 19.44 39.825 ;
     RECT  2.16 40.095 19.44 40.365 ;
     RECT  2.16 40.635 19.44 40.905 ;
     RECT  2.16 41.175 19.44 41.445 ;
     RECT  2.16 41.715 19.44 41.985 ;
     RECT  2.16 42.255 19.44 42.525 ;
     RECT  2.16 42.795 19.44 43.065 ;
     RECT  2.16 43.335 19.44 43.605 ;
     RECT  2.16 43.875 19.44 44.145 ;
     RECT  2.16 44.415 19.44 44.685 ;
     RECT  2.16 44.955 19.44 45.225 ;
     RECT  2.16 45.495 19.44 45.765 ;
     RECT  2.16 46.035 19.44 46.305 ;
     RECT  2.16 46.575 19.44 46.845 ;
     RECT  2.16 47.115 19.44 47.385 ;
     RECT  2.16 47.655 19.44 47.925 ;
     RECT  2.16 48.195 19.44 48.465 ;
     RECT  2.16 48.735 19.44 49.005 ;
     RECT  2.16 49.275 19.44 49.545 ;
     RECT  2.16 49.815 19.44 50.085 ;
     RECT  2.16 50.355 19.44 50.625 ;
     RECT  2.16 50.895 19.44 51.165 ;
     RECT  2.16 51.435 19.44 51.705 ;
     RECT  2.16 51.975 19.44 52.245 ;
     RECT  2.16 52.515 19.44 52.785 ;
     RECT  2.16 53.055 19.44 53.325 ;
     RECT  2.16 53.595 19.44 53.865 ;
     RECT  2.16 54.135 19.44 54.405 ;
     RECT  2.16 54.675 19.44 54.945 ;
     RECT  2.16 55.215 19.44 55.485 ;
     RECT  2.16 55.755 19.44 56.025 ;
     RECT  2.16 56.295 19.44 56.565 ;
     RECT  2.16 56.835 19.44 57.105 ;
     RECT  2.16 57.375 19.44 57.645 ;
     RECT  2.16 57.915 19.44 58.185 ;
     RECT  2.16 58.455 19.44 58.725 ;
     RECT  2.16 58.995 19.44 59.265 ;
     RECT  2.16 59.535 19.44 59.805 ;
     RECT  2.16 60.075 19.44 60.345 ;
     RECT  2.16 60.615 19.44 60.885 ;
     RECT  2.16 61.155 19.44 61.425 ;
     RECT  2.16 61.695 19.44 61.965 ;
     RECT  2.16 62.235 19.44 62.505 ;
     RECT  2.16 62.775 19.44 63.045 ;
     RECT  2.16 63.315 19.44 63.585 ;
     RECT  2.16 63.855 19.44 64.125 ;
     RECT  2.16 64.395 19.44 64.665 ;
     RECT  2.16 64.935 19.44 65.205 ;
     RECT  2.16 65.475 19.44 65.745 ;
     RECT  2.16 66.015 19.44 66.285 ;
     RECT  2.16 66.555 19.44 66.825 ;
     RECT  2.16 67.095 19.44 67.365 ;
     RECT  2.16 67.635 19.44 67.905 ;
     RECT  2.16 68.175 19.44 68.445 ;
     RECT  2.16 68.715 19.44 68.985 ;
     RECT  2.16 69.255 19.44 69.525 ;
     RECT  2.16 69.795 19.44 70.065 ;
     RECT  2.16 70.335 19.44 70.605 ;
     RECT  2.16 70.875 19.44 71.145 ;
     RECT  2.16 71.415 19.44 71.685 ;
     RECT  2.16 71.955 19.44 72.225 ;
     RECT  2.16 72.495 19.44 72.765 ;
     RECT  2.16 73.035 19.44 73.305 ;
    LAYER M1 ;
     RECT  2.16 2.151 19.44 73.449 ;
    LAYER M2 ;
     RECT  0.031 26.676 0.139 26.694 ;
     RECT  0.031 38.916 0.139 38.934 ;
     RECT  0.031 53.298 0.139 53.316 ;
     RECT  0.031 15.84 0.239 15.858 ;
     RECT  0.139 26.676 0.239 27.36 ;
     RECT  0.031 29.61 0.239 29.628 ;
     RECT  0.031 30.456 0.239 30.474 ;
     RECT  0.031 32.85 0.239 33.57 ;
     RECT  0.031 35.631 0.239 35.649 ;
     RECT  0.139 38.718 0.239 38.934 ;
     RECT  0.031 45.234 0.239 45.252 ;
     RECT  0.031 46.656 0.239 46.674 ;
     RECT  0.031 52.056 0.239 52.074 ;
     RECT  0.031 56.88 0.239 59.184 ;
     RECT  0.031 7.362 0.311 7.92 ;
     RECT  0.031 14.724 0.311 14.742 ;
     RECT  0.239 33.552 0.311 33.57 ;
     RECT  0.139 53.298 0.311 53.514 ;
     RECT  0.239 58.536 0.311 59.184 ;
     RECT  0.311 7.362 0.383 7.38 ;
     RECT  0.311 53.298 0.383 53.316 ;
     RECT  0.239 57.348 0.383 57.366 ;
     RECT  0.139 17.082 0.535 17.1 ;
     RECT  0.535 5.58 2.16 5.598 ;
     RECT  0.535 17.082 2.16 17.442 ;
     RECT  0.239 27.342 2.16 27.36 ;
     RECT  0.311 58.536 2.16 58.554 ;
     RECT  2.16 2.151 19.44 73.449 ;
     RECT  19.44 70.074 19.679 71.874 ;
     RECT  19.679 70.074 19.823 71.604 ;
     RECT  19.823 71.586 19.859 71.604 ;
     RECT  19.823 70.074 19.895 70.794 ;
     RECT  19.44 4.806 19.931 15.318 ;
     RECT  19.44 26.226 19.931 66.51 ;
     RECT  19.895 70.344 19.931 70.794 ;
     RECT  19.931 4.806 19.967 6.606 ;
     RECT  19.931 14.958 19.967 15.318 ;
     RECT  19.931 26.226 19.967 50.922 ;
     RECT  19.44 67.572 19.967 69.048 ;
     RECT  19.931 70.344 20.219 70.362 ;
     RECT  19.44 16.11 20.507 25.47 ;
     RECT  19.967 29.304 20.507 40.968 ;
     RECT  19.967 41.796 20.507 50.922 ;
     RECT  19.931 52.182 20.507 66.51 ;
     RECT  19.967 67.572 20.507 68.778 ;
     RECT  19.967 4.806 20.543 5.796 ;
     RECT  19.931 7.704 20.543 14.166 ;
     RECT  19.967 15.228 20.543 15.282 ;
     RECT  20.507 17.082 20.543 24.696 ;
     RECT  20.507 25.452 20.543 25.47 ;
     RECT  19.967 26.226 20.543 28.44 ;
     RECT  20.507 31.464 20.543 36.954 ;
     RECT  20.507 37.836 20.543 39.114 ;
     RECT  20.507 41.994 20.543 45.144 ;
     RECT  20.507 46.35 20.543 50.922 ;
     RECT  20.507 52.182 20.543 53.316 ;
     RECT  20.507 54.612 20.543 59.094 ;
     RECT  20.507 60.048 20.543 61.416 ;
     RECT  20.543 8.586 20.579 9.306 ;
     RECT  20.543 10.17 20.579 10.188 ;
     RECT  20.543 18.198 20.579 24.534 ;
     RECT  20.543 27.918 20.579 28.44 ;
     RECT  20.543 31.5 20.579 35.532 ;
     RECT  20.543 46.35 20.579 46.368 ;
     RECT  20.543 60.048 20.579 60.066 ;
     RECT  20.543 60.858 20.579 60.876 ;
     RECT  20.543 10.98 20.615 11.394 ;
     RECT  20.543 15.264 20.615 15.282 ;
     RECT  20.507 62.208 21.263 66.51 ;
     RECT  20.543 36.486 21.299 36.954 ;
     RECT  20.507 29.304 21.335 30.672 ;
     RECT  20.507 39.87 21.335 40.968 ;
     RECT  20.543 55.458 21.335 58.284 ;
     RECT  20.543 26.226 21.371 27.162 ;
     RECT  21.335 30.078 21.371 30.672 ;
     RECT  20.579 31.698 21.371 35.532 ;
     RECT  21.299 36.9 21.379 36.954 ;
     RECT  20.543 37.836 21.379 39.078 ;
     RECT  20.543 4.806 21.407 5.364 ;
     RECT  20.579 18.198 21.407 23.274 ;
     RECT  20.579 24.138 21.407 24.534 ;
     RECT  21.371 26.334 21.407 27.162 ;
     RECT  21.371 30.348 21.407 30.672 ;
     RECT  21.371 31.698 21.407 35.496 ;
     RECT  21.335 40.41 21.407 40.968 ;
     RECT  20.543 42.768 21.407 42.822 ;
     RECT  21.335 55.458 21.407 55.944 ;
     RECT  21.263 62.208 21.407 66.474 ;
     RECT  20.507 67.608 21.407 68.778 ;
     RECT  21.407 30.456 21.415 30.672 ;
     RECT  21.407 4.806 21.443 4.824 ;
     RECT  20.543 7.704 21.443 7.722 ;
     RECT  20.579 8.82 21.443 9.306 ;
     RECT  20.615 11.376 21.443 11.394 ;
     RECT  20.543 12.366 21.443 12.384 ;
     RECT  20.543 13.14 21.443 14.004 ;
     RECT  20.543 17.082 21.443 17.1 ;
     RECT  21.407 18.432 21.443 18.756 ;
     RECT  21.407 19.584 21.443 23.274 ;
     RECT  21.407 24.138 21.443 24.156 ;
     RECT  21.407 26.532 21.443 27.09 ;
     RECT  20.579 28.026 21.443 28.44 ;
     RECT  21.335 29.304 21.443 29.322 ;
     RECT  21.415 30.456 21.443 30.708 ;
     RECT  21.407 31.698 21.443 34.992 ;
     RECT  21.379 36.9 21.443 39.078 ;
     RECT  21.407 40.41 21.443 40.932 ;
     RECT  21.407 42.804 21.443 42.822 ;
     RECT  20.543 43.956 21.443 45.144 ;
     RECT  20.543 47.196 21.443 47.646 ;
     RECT  20.543 49.248 21.443 49.644 ;
     RECT  20.543 50.904 21.443 50.922 ;
     RECT  20.543 52.182 21.443 52.848 ;
     RECT  20.543 54.612 21.443 54.63 ;
     RECT  21.407 55.926 21.443 55.944 ;
     RECT  21.335 57.114 21.443 58.284 ;
     RECT  20.543 59.076 21.443 59.094 ;
     RECT  21.407 62.244 21.443 62.262 ;
     RECT  21.407 63.054 21.443 65.934 ;
     RECT  21.407 68.076 21.443 68.778 ;
     RECT  21.443 30.69 21.551 30.708 ;
     RECT  21.443 33.516 21.551 33.534 ;
     RECT  21.443 65.556 21.551 65.574 ;
     RECT  21.443 68.616 21.551 68.634 ;
     RECT  21.443 18.738 21.587 18.756 ;
     RECT  21.443 26.532 21.587 26.55 ;
     RECT  21.443 36.936 21.587 37.422 ;
     RECT  21.379 45.891 21.587 45.909 ;
     RECT  21.443 49.626 21.587 49.644 ;
     RECT  21.487 51.714 21.587 51.732 ;
    LAYER M3 ;
     RECT  2.415 2.143 2.505 2.413 ;
     RECT  5.115 2.143 5.205 2.413 ;
     RECT  7.815 2.143 7.905 2.413 ;
     RECT  10.515 2.143 10.605 2.413 ;
     RECT  13.215 2.143 13.305 2.413 ;
     RECT  15.915 2.143 16.005 2.413 ;
     RECT  18.615 2.143 18.705 2.413 ;
     RECT  18.615 2.413 18.897 4.153 ;
     RECT  18.468 4.153 18.897 4.495 ;
     RECT  18.468 4.495 19.062 4.531 ;
     RECT  18.468 4.531 19.206 4.801 ;
     RECT  18.432 4.801 19.206 4.891 ;
     RECT  15.915 2.413 16.197 5.071 ;
     RECT  15.915 5.071 16.542 5.189 ;
     RECT  2.415 2.413 2.697 5.305 ;
     RECT  5.115 2.413 5.397 5.305 ;
     RECT  4.572 5.305 6.03 5.341 ;
     RECT  10.515 2.413 10.797 5.341 ;
     RECT  18.144 4.891 19.206 5.341 ;
     RECT  21.42 4.801 21.438 5.341 ;
     RECT  4.176 5.341 6.03 5.459 ;
     RECT  10.008 5.341 10.797 5.459 ;
     RECT  21.384 5.341 21.438 5.549 ;
     RECT  17.712 5.341 19.206 5.575 ;
     RECT  4.176 5.459 5.85 5.611 ;
     RECT  17.532 5.575 19.206 5.611 ;
     RECT  7.815 2.413 8.097 5.809 ;
     RECT  13.215 2.413 13.497 5.809 ;
     RECT  17.532 5.611 19.242 5.809 ;
     RECT  7.704 5.809 8.097 5.845 ;
     RECT  14.832 5.431 14.85 5.845 ;
     RECT  2.304 5.305 2.697 5.881 ;
     RECT  6.876 5.845 8.097 5.881 ;
     RECT  16.92 5.809 19.242 5.881 ;
     RECT  20.52 5.071 20.538 5.933 ;
     RECT  2.304 5.881 2.79 5.995 ;
     RECT  3.6 5.611 5.85 5.995 ;
     RECT  6.876 5.881 8.37 6.007 ;
     RECT  16.92 5.881 19.422 6.028 ;
     RECT  6.804 6.007 8.37 6.043 ;
     RECT  14.832 5.845 14.886 6.043 ;
     RECT  10.515 5.459 10.797 6.079 ;
     RECT  6.768 6.043 8.37 6.151 ;
     RECT  14.832 6.043 15.102 6.151 ;
     RECT  15.915 5.189 16.197 6.151 ;
     RECT  21.384 5.549 21.402 6.173 ;
     RECT  6.768 6.151 8.478 6.269 ;
     RECT  14.832 6.151 16.197 6.269 ;
     RECT  0.54 5.575 0.558 6.317 ;
     RECT  7.704 6.269 8.478 6.377 ;
     RECT  16.92 6.028 19.458 6.379 ;
     RECT  2.304 5.995 5.85 6.385 ;
     RECT  2.304 6.385 5.994 6.523 ;
     RECT  12.924 5.809 13.497 6.539 ;
     RECT  2.268 6.523 5.994 6.583 ;
     RECT  6.768 6.269 6.894 6.583 ;
     RECT  15.732 6.269 16.197 6.655 ;
     RECT  16.92 6.379 19.962 6.655 ;
     RECT  7.704 6.377 8.442 6.809 ;
     RECT  15.732 6.655 19.962 6.809 ;
     RECT  2.268 6.583 6.894 6.845 ;
     RECT  15.732 6.809 16.197 6.845 ;
     RECT  17.136 6.809 19.962 6.881 ;
     RECT  10.515 6.079 11.214 6.925 ;
     RECT  14.832 6.269 14.85 6.961 ;
     RECT  10.515 6.925 11.682 7.079 ;
     RECT  14.472 6.961 14.85 7.259 ;
     RECT  0.216 7.291 0.378 7.357 ;
     RECT  0.036 7.357 0.378 7.385 ;
     RECT  17.424 6.881 19.962 7.421 ;
     RECT  3.996 6.845 6.894 7.429 ;
     RECT  13.215 6.539 13.497 7.429 ;
     RECT  14.472 7.259 14.742 7.429 ;
     RECT  7.815 6.809 8.442 7.501 ;
     RECT  3.996 7.429 7.038 7.619 ;
     RECT  13.215 7.429 14.742 7.619 ;
     RECT  2.268 6.845 2.97 7.627 ;
     RECT  3.996 7.619 6.03 7.627 ;
     RECT  17.424 7.421 19.134 7.627 ;
     RECT  13.215 7.619 13.95 7.663 ;
     RECT  13.068 7.663 13.95 7.691 ;
     RECT  13.068 7.691 13.497 7.763 ;
     RECT  17.208 7.627 19.134 7.771 ;
     RECT  6.804 7.619 7.038 7.799 ;
     RECT  14.724 7.619 14.742 7.799 ;
     RECT  21.42 7.699 21.438 7.805 ;
     RECT  12.06 7.735 12.078 7.889 ;
     RECT  0.036 7.385 0.306 7.925 ;
     RECT  2.268 7.627 6.03 7.925 ;
     RECT  19.944 7.421 19.962 7.933 ;
     RECT  0.036 7.925 0.234 7.949 ;
     RECT  15.915 6.845 16.197 7.969 ;
     RECT  16.956 7.771 19.134 7.969 ;
     RECT  10.515 7.079 11.142 8.041 ;
     RECT  7.815 7.501 9.162 8.159 ;
     RECT  10.515 8.041 11.754 8.159 ;
     RECT  2.304 7.925 6.03 8.195 ;
     RECT  15.915 7.969 19.134 8.203 ;
     RECT  11.736 8.159 11.754 8.231 ;
     RECT  14.76 8.131 14.958 8.239 ;
     RECT  15.915 8.203 19.17 8.239 ;
     RECT  14.76 8.239 19.17 8.339 ;
     RECT  19.944 7.933 20.538 8.395 ;
     RECT  14.832 8.339 19.17 8.429 ;
     RECT  19.908 8.395 20.538 8.465 ;
     RECT  14.832 8.429 14.958 8.537 ;
     RECT  20.448 8.465 20.538 8.581 ;
     RECT  3.708 8.195 6.03 8.671 ;
     RECT  6.804 7.799 6.93 8.671 ;
     RECT  3.708 8.671 6.93 8.699 ;
     RECT  9.396 8.437 9.414 8.699 ;
     RECT  20.448 8.581 20.574 8.813 ;
     RECT  6.624 8.699 6.93 8.815 ;
     RECT  12.024 8.743 12.042 8.969 ;
     RECT  2.304 8.195 2.934 9.085 ;
     RECT  3.708 8.699 5.85 9.085 ;
     RECT  6.624 8.815 7.074 9.121 ;
     RECT  7.815 8.159 8.442 9.121 ;
     RECT  2.304 9.085 5.85 9.239 ;
     RECT  6.624 9.121 8.442 9.239 ;
     RECT  21.42 8.683 21.438 9.311 ;
     RECT  9.432 8.743 9.45 9.319 ;
     RECT  15.915 8.429 19.17 9.341 ;
     RECT  12.132 9.283 12.15 9.391 ;
     RECT  13.215 7.763 13.497 9.391 ;
     RECT  9.432 9.319 9.774 9.481 ;
     RECT  10.515 8.159 10.797 9.481 ;
     RECT  20.448 8.813 20.538 9.547 ;
     RECT  9.432 9.481 10.797 9.689 ;
     RECT  14.832 8.537 14.85 9.751 ;
     RECT  9.684 9.689 10.797 9.779 ;
     RECT  12.132 9.391 13.497 9.779 ;
     RECT  15.915 9.341 19.134 9.779 ;
     RECT  19.944 9.547 20.538 9.787 ;
     RECT  12.132 9.779 12.474 9.823 ;
     RECT  14.832 9.751 14.886 9.859 ;
     RECT  9.792 9.779 10.797 9.931 ;
     RECT  11.628 9.823 12.474 9.931 ;
     RECT  14.832 9.859 14.994 9.931 ;
     RECT  14.796 9.931 14.994 10.021 ;
     RECT  14.796 10.021 15.066 10.027 ;
     RECT  9.792 9.931 12.474 10.049 ;
     RECT  12.456 10.049 12.474 10.121 ;
     RECT  13.215 9.779 13.497 10.129 ;
     RECT  7.815 9.239 8.442 10.157 ;
     RECT  14.724 10.027 15.066 10.157 ;
     RECT  19.944 9.787 20.574 10.157 ;
     RECT  2.304 9.239 2.97 10.171 ;
     RECT  2.304 10.171 3.006 10.201 ;
     RECT  3.744 9.239 5.85 10.201 ;
     RECT  6.84 9.239 6.966 10.201 ;
     RECT  10.26 10.049 11.034 10.229 ;
     RECT  2.304 10.201 5.85 10.319 ;
     RECT  6.66 10.201 6.966 10.471 ;
     RECT  7.815 10.157 8.298 10.471 ;
     RECT  13.215 10.129 13.77 10.471 ;
     RECT  20.484 10.157 20.574 10.795 ;
     RECT  14.832 10.157 15.066 10.903 ;
     RECT  15.915 9.779 18.954 10.903 ;
     RECT  4.104 10.319 5.85 10.939 ;
     RECT  6.66 10.471 8.298 10.939 ;
     RECT  14.832 10.903 18.954 10.939 ;
     RECT  13.215 10.471 13.806 10.975 ;
     RECT  20.484 10.795 20.61 11.003 ;
     RECT  20.484 11.003 20.574 11.083 ;
     RECT  10.26 10.229 10.797 11.129 ;
     RECT  13.215 10.975 13.842 11.129 ;
     RECT  2.304 10.319 3.33 11.173 ;
     RECT  4.104 10.939 8.298 11.173 ;
     RECT  19.908 11.083 20.574 11.201 ;
     RECT  20.448 11.201 20.574 11.237 ;
     RECT  2.304 11.173 8.298 11.245 ;
     RECT  9.18 10.867 9.198 11.245 ;
     RECT  2.304 11.245 9.198 11.309 ;
     RECT  0.216 10.459 0.234 11.357 ;
     RECT  13.215 11.129 13.497 11.371 ;
     RECT  14.832 10.939 19.062 11.371 ;
     RECT  2.304 11.309 9.126 11.399 ;
     RECT  21.42 11.323 21.438 11.399 ;
     RECT  6.84 11.399 6.93 11.405 ;
     RECT  14.832 11.371 19.206 11.453 ;
     RECT  10.515 11.129 10.797 11.515 ;
     RECT  7.776 11.399 9.126 11.543 ;
     RECT  14.832 11.453 19.062 11.641 ;
     RECT  10.515 11.515 10.926 11.677 ;
     RECT  7.776 11.543 9.054 11.849 ;
     RECT  14.76 11.641 19.062 11.939 ;
     RECT  20.448 11.237 20.538 11.947 ;
     RECT  14.76 11.939 19.026 12.019 ;
     RECT  19.908 11.947 20.538 12.119 ;
     RECT  6.84 11.405 6.858 12.181 ;
     RECT  6.84 12.181 6.894 12.187 ;
     RECT  13.104 11.371 13.497 12.217 ;
     RECT  10.515 11.677 11.646 12.253 ;
     RECT  0.216 12.187 0.234 12.317 ;
     RECT  2.304 11.399 5.814 12.361 ;
     RECT  6.696 12.187 7.038 12.361 ;
     RECT  12.96 12.217 13.497 12.362 ;
     RECT  10.515 12.253 11.682 12.479 ;
     RECT  7.776 11.849 8.478 12.509 ;
     RECT  10.515 12.479 11.538 12.515 ;
     RECT  2.304 12.361 7.038 12.523 ;
     RECT  7.776 12.509 8.298 12.523 ;
     RECT  21.42 12.331 21.438 12.763 ;
     RECT  20.484 12.119 20.538 12.821 ;
     RECT  21.384 12.763 21.438 12.893 ;
     RECT  2.304 12.523 8.298 12.901 ;
     RECT  12.996 12.362 13.497 12.901 ;
     RECT  14.22 12.019 19.026 12.901 ;
     RECT  2.268 12.901 8.298 12.989 ;
     RECT  12.996 12.901 19.026 13.019 ;
     RECT  12.996 13.019 14.85 13.037 ;
     RECT  15.624 13.019 19.026 13.063 ;
     RECT  12.996 13.037 13.497 13.171 ;
     RECT  20.484 12.821 20.502 13.195 ;
     RECT  9.54 12.829 9.558 13.289 ;
     RECT  12.78 13.171 13.497 13.369 ;
     RECT  2.304 12.989 8.298 13.405 ;
     RECT  2.304 13.405 9.162 13.631 ;
     RECT  9.144 13.631 9.162 13.667 ;
     RECT  20.196 13.195 20.502 13.723 ;
     RECT  12.564 13.369 13.497 13.829 ;
     RECT  14.4 13.037 14.85 13.829 ;
     RECT  14.436 13.829 14.85 13.873 ;
     RECT  2.304 13.631 8.298 13.963 ;
     RECT  19.908 13.723 20.502 13.963 ;
     RECT  10.515 12.515 11.394 14.071 ;
     RECT  2.268 13.963 8.298 14.135 ;
     RECT  10.515 14.071 11.466 14.141 ;
     RECT  21.42 12.893 21.438 14.141 ;
     RECT  15.624 13.063 19.134 14.189 ;
     RECT  14.436 13.873 14.886 14.341 ;
     RECT  15.624 14.189 19.062 14.341 ;
     RECT  14.436 14.341 19.062 14.369 ;
     RECT  9.18 14.215 9.774 14.521 ;
     RECT  10.515 14.141 10.797 14.521 ;
     RECT  0.216 14.587 0.234 14.635 ;
     RECT  13.215 13.829 13.497 14.647 ;
     RECT  0.216 14.635 0.306 14.719 ;
     RECT  0.036 14.719 0.306 14.747 ;
     RECT  9.18 14.521 10.797 14.747 ;
     RECT  0.036 14.747 0.234 14.765 ;
     RECT  2.304 14.135 8.298 14.945 ;
     RECT  19.908 13.963 20.538 14.971 ;
     RECT  13.215 14.647 13.914 15.061 ;
     RECT  2.304 14.945 5.397 15.115 ;
     RECT  6.156 14.945 8.298 15.197 ;
     RECT  6.156 15.197 7.074 15.215 ;
     RECT  19.908 14.971 20.61 15.287 ;
     RECT  14.832 14.369 19.062 15.295 ;
     RECT  9.18 14.747 9.27 15.323 ;
     RECT  19.908 15.287 19.962 15.323 ;
     RECT  14.76 15.295 19.062 15.355 ;
     RECT  6.156 15.215 7.038 15.359 ;
     RECT  9.18 15.323 9.198 15.359 ;
     RECT  13.104 15.061 13.914 15.421 ;
     RECT  14.76 15.355 19.386 15.421 ;
     RECT  13.104 15.421 19.386 15.449 ;
     RECT  13.104 15.449 19.062 15.593 ;
     RECT  10.515 14.747 10.797 15.601 ;
     RECT  7.815 15.197 8.298 15.691 ;
     RECT  0.216 15.595 0.234 15.739 ;
     RECT  21.384 14.347 21.402 15.739 ;
     RECT  21.312 15.739 21.402 15.821 ;
     RECT  0.036 15.739 0.234 15.863 ;
     RECT  0.216 15.863 0.234 15.869 ;
     RECT  21.312 15.821 21.33 15.869 ;
     RECT  2.268 15.115 5.397 15.871 ;
     RECT  6.156 15.359 6.966 15.871 ;
     RECT  11.592 15.025 11.61 15.989 ;
     RECT  13.104 15.593 14.922 16.105 ;
     RECT  12.924 16.105 14.922 16.141 ;
     RECT  2.268 15.871 6.966 16.231 ;
     RECT  12.564 16.141 14.922 16.259 ;
     RECT  10.26 15.601 10.797 16.267 ;
     RECT  15.915 15.593 19.062 16.303 ;
     RECT  7.815 15.691 8.334 16.363 ;
     RECT  20.484 16.105 20.502 16.363 ;
     RECT  7.815 16.363 8.37 16.405 ;
     RECT  9.144 15.727 9.162 16.405 ;
     RECT  7.815 16.405 9.162 16.439 ;
     RECT  20.448 16.363 20.502 16.439 ;
     RECT  7.815 16.439 8.514 16.445 ;
     RECT  10.26 16.267 10.854 16.501 ;
     RECT  12.924 16.259 14.922 16.501 ;
     RECT  15.915 16.303 19.134 16.501 ;
     RECT  7.815 16.445 8.406 16.529 ;
     RECT  9.324 16.501 10.854 16.529 ;
     RECT  12.924 16.501 19.134 16.589 ;
     RECT  7.815 16.529 8.37 16.601 ;
     RECT  2.268 16.231 7.002 16.637 ;
     RECT  2.304 16.637 7.002 16.795 ;
     RECT  7.815 16.601 8.334 16.795 ;
     RECT  15.696 16.589 19.134 16.891 ;
     RECT  19.908 16.747 19.962 16.891 ;
     RECT  15.696 16.891 19.962 16.979 ;
     RECT  9.324 16.529 9.738 17.069 ;
     RECT  0.144 17.077 0.162 17.165 ;
     RECT  12.924 16.589 14.85 17.249 ;
     RECT  21.42 17.077 21.438 17.275 ;
     RECT  12.06 16.951 12.078 17.339 ;
     RECT  14.76 17.249 14.85 17.383 ;
     RECT  9.324 17.069 9.702 17.581 ;
     RECT  15.696 16.979 19.098 17.581 ;
     RECT  2.304 16.795 8.334 17.609 ;
     RECT  9.144 17.581 9.702 17.609 ;
     RECT  7.596 17.609 8.334 17.611 ;
     RECT  9.144 17.609 9.378 17.611 ;
     RECT  7.596 17.611 9.378 17.651 ;
     RECT  12.924 17.249 13.662 17.653 ;
     RECT  0.54 17.419 0.558 17.693 ;
     RECT  19.908 16.979 19.962 17.725 ;
     RECT  19.908 17.725 20.538 17.789 ;
     RECT  12.492 17.653 13.662 17.879 ;
     RECT  15.66 17.581 19.098 17.915 ;
     RECT  10.515 16.529 10.797 18.031 ;
     RECT  11.7 17.725 11.718 18.031 ;
     RECT  15.696 17.915 19.098 18.149 ;
     RECT  10.515 18.031 11.718 18.265 ;
     RECT  14.76 17.383 14.886 18.301 ;
     RECT  2.304 17.609 6.822 18.379 ;
     RECT  7.815 17.651 9.378 18.379 ;
     RECT  2.268 18.379 9.378 18.419 ;
     RECT  10.515 18.265 11.79 18.419 ;
     RECT  14.328 18.301 14.886 18.419 ;
     RECT  15.696 18.149 19.062 18.419 ;
     RECT  4.392 18.419 9.198 18.455 ;
     RECT  15.876 18.419 19.062 18.491 ;
     RECT  21.384 17.275 21.438 18.523 ;
     RECT  21.384 18.523 21.582 18.619 ;
     RECT  21.348 18.619 21.582 18.667 ;
     RECT  4.392 18.455 6.858 18.689 ;
     RECT  7.815 18.455 9.198 18.689 ;
     RECT  13.215 17.879 13.497 18.697 ;
     RECT  10.515 18.419 10.797 18.715 ;
     RECT  21.24 18.667 21.582 18.761 ;
     RECT  9.072 18.689 9.198 18.797 ;
     RECT  21.24 18.761 21.438 18.797 ;
     RECT  20.484 18.619 20.502 18.832 ;
     RECT  20.448 18.832 20.502 18.833 ;
     RECT  20.448 18.833 20.466 18.941 ;
     RECT  10.44 18.715 10.797 18.955 ;
     RECT  6.696 18.689 6.858 18.959 ;
     RECT  2.268 18.419 3.402 18.995 ;
     RECT  10.116 18.955 10.797 18.995 ;
     RECT  12.672 18.697 13.497 19.229 ;
     RECT  15.912 18.491 19.062 19.229 ;
     RECT  15.915 19.229 19.062 19.381 ;
     RECT  4.392 18.689 5.778 19.471 ;
     RECT  6.84 18.959 6.858 19.483 ;
     RECT  7.815 18.689 8.226 19.483 ;
     RECT  11.7 19.201 11.718 19.499 ;
     RECT  21.384 18.797 21.438 19.531 ;
     RECT  6.84 19.483 8.226 19.535 ;
     RECT  4.32 19.471 5.778 19.651 ;
     RECT  9.18 18.797 9.198 19.679 ;
     RECT  2.304 18.995 3.402 19.741 ;
     RECT  4.32 19.651 5.814 19.741 ;
     RECT  15.915 19.381 19.278 19.769 ;
     RECT  14.832 18.419 14.886 19.777 ;
     RECT  15.915 19.769 19.17 19.805 ;
     RECT  11.772 19.651 11.79 19.841 ;
     RECT  20.52 19.771 20.538 19.877 ;
     RECT  0.216 19.819 0.234 19.949 ;
     RECT  14.4 19.777 14.886 20.191 ;
     RECT  14.22 20.191 14.886 20.219 ;
     RECT  20.376 20.059 20.502 20.219 ;
     RECT  2.304 19.741 5.814 20.281 ;
     RECT  6.84 19.535 6.858 20.281 ;
     RECT  7.815 19.535 8.226 20.281 ;
     RECT  20.376 20.219 20.394 20.299 ;
     RECT  14.22 20.219 14.85 20.309 ;
     RECT  21.348 19.531 21.438 20.309 ;
     RECT  13.215 19.229 13.497 20.317 ;
     RECT  6.84 20.281 8.226 20.389 ;
     RECT  19.908 20.299 20.394 20.429 ;
     RECT  9.036 20.191 9.126 20.453 ;
     RECT  9.108 20.453 9.126 20.489 ;
     RECT  6.804 20.389 8.226 20.579 ;
     RECT  13.215 20.317 13.662 20.579 ;
     RECT  9.216 20.587 9.234 20.623 ;
     RECT  2.304 20.281 5.994 20.683 ;
     RECT  2.232 20.683 5.994 20.723 ;
     RECT  9.216 20.623 9.306 20.759 ;
     RECT  2.232 20.723 5.958 20.885 ;
     RECT  21.384 20.309 21.438 20.993 ;
     RECT  2.304 20.885 5.958 21.029 ;
     RECT  13.215 20.579 13.497 21.127 ;
     RECT  14.652 20.309 14.85 21.163 ;
     RECT  19.944 20.429 19.962 21.163 ;
     RECT  19.944 21.163 20.502 21.227 ;
     RECT  12.816 21.127 13.497 21.271 ;
     RECT  6.84 20.579 8.226 21.361 ;
     RECT  12.672 21.271 13.497 21.389 ;
     RECT  6.84 21.361 8.334 21.433 ;
     RECT  15.915 19.805 19.134 21.451 ;
     RECT  12.996 21.389 13.497 21.533 ;
     RECT  13.104 21.533 13.497 21.541 ;
     RECT  14.328 21.163 14.85 21.541 ;
     RECT  19.908 21.307 19.926 21.569 ;
     RECT  6.732 21.433 8.334 21.695 ;
     RECT  6.732 21.695 6.858 21.811 ;
     RECT  13.104 21.541 14.85 21.901 ;
     RECT  15.912 21.451 19.134 21.901 ;
     RECT  21.42 20.993 21.438 22.027 ;
     RECT  0.216 21.451 0.234 22.205 ;
     RECT  21.384 22.027 21.438 22.205 ;
     RECT  10.515 18.995 10.797 22.207 ;
     RECT  2.304 21.029 5.814 22.351 ;
     RECT  6.552 21.811 6.858 22.351 ;
     RECT  10.515 22.207 11.43 22.469 ;
     RECT  13.104 21.901 19.134 22.469 ;
     RECT  7.815 21.695 8.334 22.541 ;
     RECT  19.944 22.459 19.962 22.549 ;
     RECT  9.288 21.901 9.306 22.649 ;
     RECT  2.304 22.351 6.858 22.699 ;
     RECT  13.104 22.469 13.497 22.747 ;
     RECT  2.268 22.699 6.858 22.783 ;
     RECT  2.268 22.783 6.93 22.847 ;
     RECT  2.304 22.847 6.93 22.891 ;
     RECT  14.436 22.469 19.134 23.009 ;
     RECT  12.816 22.747 13.497 23.125 ;
     RECT  14.868 23.009 19.134 23.189 ;
     RECT  15.516 23.189 19.134 23.251 ;
     RECT  12.42 23.125 13.497 23.279 ;
     RECT  7.815 22.541 8.226 23.323 ;
     RECT  19.944 22.549 20.502 23.395 ;
     RECT  2.304 22.891 7.074 23.521 ;
     RECT  7.815 23.323 8.262 23.521 ;
     RECT  15.516 23.251 19.206 23.563 ;
     RECT  19.944 23.395 20.538 23.563 ;
     RECT  2.304 23.521 8.262 23.629 ;
     RECT  13.032 23.279 13.497 23.665 ;
     RECT  0.216 23.707 0.234 23.803 ;
     RECT  2.304 23.629 8.406 23.855 ;
     RECT  0.216 23.803 0.306 23.885 ;
     RECT  4.788 23.855 8.406 23.927 ;
     RECT  0.288 23.885 0.306 23.933 ;
     RECT  15.516 23.563 20.538 23.933 ;
     RECT  19.908 23.933 20.538 23.935 ;
     RECT  4.788 23.927 8.118 23.936 ;
     RECT  21.42 22.205 21.438 23.947 ;
     RECT  19.908 23.935 20.574 23.999 ;
     RECT  13.032 23.665 13.662 24.089 ;
     RECT  15.516 23.933 19.026 24.089 ;
     RECT  21.384 23.947 21.438 24.161 ;
     RECT  9.216 24.097 9.234 24.169 ;
     RECT  13.215 24.089 13.662 24.169 ;
     RECT  20.52 23.999 20.574 24.169 ;
     RECT  9.144 24.169 9.234 24.197 ;
     RECT  15.624 24.089 19.026 24.233 ;
     RECT  15.915 24.233 19.026 24.359 ;
     RECT  20.52 24.169 20.61 24.509 ;
     RECT  14.724 24.511 14.742 24.601 ;
     RECT  10.515 22.469 10.797 24.673 ;
     RECT  20.52 24.509 20.538 24.701 ;
     RECT  7.128 23.936 8.118 24.709 ;
     RECT  2.304 23.855 3.87 24.745 ;
     RECT  2.304 24.745 3.978 24.781 ;
     RECT  4.788 23.936 6.066 24.781 ;
     RECT  2.304 24.781 6.066 24.859 ;
     RECT  2.268 24.859 6.066 24.871 ;
     RECT  7.02 24.709 8.118 24.871 ;
     RECT  13.215 24.169 13.806 24.979 ;
     RECT  14.724 24.601 14.85 24.979 ;
     RECT  9.144 24.197 9.162 25.007 ;
     RECT  7.02 24.871 8.154 25.085 ;
     RECT  2.268 24.871 6.246 25.141 ;
     RECT  13.215 24.979 14.85 25.169 ;
     RECT  15.915 24.359 18.99 25.177 ;
     RECT  7.668 25.085 8.154 25.243 ;
     RECT  20.484 24.943 20.502 25.312 ;
     RECT  20.448 25.312 20.502 25.411 ;
     RECT  19.944 25.411 20.502 25.447 ;
     RECT  15.915 25.177 19.026 25.483 ;
     RECT  11.88 25.411 11.898 25.517 ;
     RECT  19.944 25.447 20.538 25.613 ;
     RECT  13.215 25.169 13.914 25.681 ;
     RECT  12.672 25.681 13.914 25.709 ;
     RECT  14.724 25.169 14.85 25.753 ;
     RECT  2.268 25.141 6.894 25.861 ;
     RECT  7.668 25.243 8.478 25.861 ;
     RECT  21.384 24.161 21.402 25.867 ;
     RECT  12.672 25.709 13.497 25.987 ;
     RECT  21.384 25.867 21.438 26.107 ;
     RECT  2.268 25.861 8.478 26.159 ;
     RECT  15.915 25.483 19.098 26.203 ;
     RECT  21.348 26.107 21.438 26.249 ;
     RECT  14.724 25.753 14.886 26.257 ;
     RECT  2.268 26.159 6.966 26.357 ;
     RECT  14.292 26.257 14.886 26.365 ;
     RECT  15.915 26.203 19.134 26.365 ;
     RECT  20.52 25.613 20.538 26.381 ;
     RECT  21.384 26.249 21.438 26.491 ;
     RECT  14.292 26.365 19.134 26.519 ;
     RECT  21.384 26.491 21.582 26.555 ;
     RECT  0.216 25.963 0.234 26.587 ;
     RECT  10.515 24.673 10.926 26.587 ;
     RECT  14.724 26.519 19.134 26.621 ;
     RECT  14.868 26.621 19.134 26.671 ;
     RECT  20.484 26.587 20.502 26.671 ;
     RECT  0.036 26.587 0.234 26.699 ;
     RECT  7.815 26.159 8.478 26.699 ;
     RECT  10.515 26.587 11.466 26.699 ;
     RECT  14.868 26.671 19.17 26.699 ;
     RECT  0.144 26.699 0.234 26.717 ;
     RECT  12.564 25.987 13.497 26.761 ;
     RECT  19.944 26.671 20.502 26.765 ;
     RECT  15.915 26.699 19.17 26.813 ;
     RECT  2.304 26.357 6.966 26.861 ;
     RECT  12.384 26.761 13.497 26.869 ;
     RECT  15.915 26.813 19.134 27.101 ;
     RECT  12.384 26.869 13.662 27.163 ;
     RECT  15.915 27.101 19.062 27.167 ;
     RECT  21.384 26.555 21.438 27.167 ;
     RECT  20.448 26.765 20.502 27.211 ;
     RECT  4.86 26.861 6.966 27.245 ;
     RECT  6.768 27.245 6.966 27.301 ;
     RECT  7.815 26.699 8.37 27.301 ;
     RECT  2.304 26.861 4.014 27.329 ;
     RECT  6.768 27.301 8.37 27.329 ;
     RECT  12.312 27.163 13.662 27.329 ;
     RECT  6.804 27.329 8.226 27.341 ;
     RECT  14.868 26.699 14.922 27.365 ;
     RECT  0.144 26.717 0.162 27.389 ;
     RECT  2.304 27.329 3.654 27.481 ;
     RECT  10.515 26.699 10.854 27.481 ;
     RECT  2.268 27.481 3.654 27.533 ;
     RECT  10.332 27.481 10.854 27.571 ;
     RECT  4.86 27.245 5.958 27.607 ;
     RECT  13.14 27.329 13.662 27.715 ;
     RECT  15.915 27.167 19.026 27.841 ;
     RECT  10.332 27.571 11.43 27.869 ;
     RECT  13.14 27.715 13.734 27.869 ;
     RECT  20.448 27.211 20.538 27.913 ;
     RECT  10.44 27.869 11.43 27.941 ;
     RECT  20.448 27.913 20.574 27.979 ;
     RECT  13.14 27.869 13.59 28.049 ;
     RECT  4.392 27.607 5.958 28.111 ;
     RECT  6.804 27.341 8.19 28.111 ;
     RECT  10.515 27.941 11.43 28.139 ;
     RECT  15.408 27.841 19.026 28.183 ;
     RECT  14.832 28.183 19.026 28.219 ;
     RECT  19.908 27.979 20.574 28.219 ;
     RECT  0.216 28.123 0.234 28.253 ;
     RECT  14.832 28.219 20.574 28.283 ;
     RECT  2.304 27.533 3.654 28.381 ;
     RECT  4.392 28.111 8.19 28.381 ;
     RECT  2.304 28.381 8.19 28.481 ;
     RECT  14.868 28.283 20.574 28.541 ;
     RECT  2.304 28.481 6.282 28.553 ;
     RECT  12.276 28.525 12.294 28.561 ;
     RECT  19.872 28.541 20.574 28.589 ;
     RECT  19.908 28.589 20.574 28.637 ;
     RECT  12.276 28.561 12.402 28.651 ;
     RECT  13.14 28.049 13.497 28.651 ;
     RECT  2.304 28.553 6.102 28.679 ;
     RECT  14.868 28.541 19.062 28.679 ;
     RECT  19.908 28.637 19.962 28.781 ;
     RECT  10.515 28.139 10.926 28.831 ;
     RECT  14.868 28.679 18.954 28.859 ;
     RECT  10.296 28.831 10.926 28.949 ;
     RECT  7.02 28.481 8.19 29.083 ;
     RECT  19.908 28.781 19.926 29.129 ;
     RECT  21.42 27.167 21.438 29.131 ;
     RECT  7.02 29.083 8.406 29.191 ;
     RECT  12.276 28.651 13.497 29.191 ;
     RECT  9.432 28.291 9.45 29.219 ;
     RECT  11.772 29.191 13.497 29.219 ;
     RECT  2.304 28.679 2.934 29.227 ;
     RECT  3.96 28.679 6.102 29.255 ;
     RECT  11.772 29.219 11.79 29.261 ;
     RECT  21.384 29.131 21.438 29.275 ;
     RECT  2.268 29.227 2.934 29.309 ;
     RECT  14.868 28.859 15.066 29.399 ;
     RECT  2.304 29.309 2.934 29.461 ;
     RECT  3.96 29.255 6.03 29.461 ;
     RECT  2.304 29.461 6.03 29.489 ;
     RECT  7.02 29.191 8.586 29.489 ;
     RECT  14.868 29.399 14.886 29.489 ;
     RECT  7.02 29.489 8.19 29.497 ;
     RECT  0.216 29.131 0.234 29.515 ;
     RECT  10.515 28.949 10.926 29.561 ;
     RECT  13.032 29.219 13.497 29.569 ;
     RECT  0.036 29.515 0.234 29.633 ;
     RECT  5.04 29.489 6.03 29.759 ;
     RECT  15.915 28.859 18.954 29.803 ;
     RECT  13.032 29.569 13.986 29.875 ;
     RECT  6.912 29.497 8.19 29.911 ;
     RECT  6.804 29.911 8.19 30.029 ;
     RECT  20.484 29.875 20.502 30.029 ;
     RECT  2.304 29.489 3.942 30.136 ;
     RECT  13.032 29.875 14.094 30.173 ;
     RECT  5.04 29.759 5.886 30.269 ;
     RECT  15.915 29.803 19.062 30.283 ;
     RECT  2.268 30.136 3.942 30.307 ;
     RECT  5.04 30.269 5.634 30.307 ;
     RECT  10.515 29.561 10.854 30.307 ;
     RECT  6.84 30.029 8.19 30.343 ;
     RECT  10.515 30.307 10.89 30.343 ;
     RECT  0.216 29.633 0.234 30.379 ;
     RECT  21.312 29.275 21.438 30.379 ;
     RECT  14.796 30.343 14.814 30.443 ;
     RECT  15.915 30.283 19.386 30.451 ;
     RECT  0.036 30.379 0.234 30.479 ;
     RECT  6.84 30.343 8.37 30.479 ;
     RECT  10.515 30.343 11.394 30.541 ;
     RECT  21.24 30.379 21.438 30.557 ;
     RECT  14.832 30.541 14.85 30.577 ;
     RECT  15.804 30.451 19.386 30.577 ;
     RECT  2.268 30.307 5.634 30.605 ;
     RECT  14.832 30.577 19.386 30.653 ;
     RECT  21.312 30.557 21.438 30.677 ;
     RECT  21.384 30.677 21.438 30.685 ;
     RECT  6.84 30.479 8.154 30.811 ;
     RECT  14.832 30.653 19.134 30.839 ;
     RECT  13.032 30.173 13.77 30.847 ;
     RECT  0.216 30.479 0.234 30.893 ;
     RECT  10.515 30.541 12.114 30.955 ;
     RECT  20.484 30.859 20.502 30.955 ;
     RECT  12.924 30.847 13.77 30.991 ;
     RECT  2.304 30.605 5.634 31.081 ;
     RECT  10.515 30.955 12.15 31.109 ;
     RECT  12.924 30.991 13.914 31.109 ;
     RECT  10.515 31.109 11.466 31.181 ;
     RECT  13.215 31.109 13.914 31.217 ;
     RECT  12.204 31.195 12.222 31.289 ;
     RECT  6.588 30.811 8.154 31.351 ;
     RECT  20.448 30.955 20.502 31.451 ;
     RECT  20.484 31.451 20.502 31.459 ;
     RECT  20.484 31.459 20.538 31.495 ;
     RECT  6.516 31.351 8.154 31.657 ;
     RECT  9.18 31.621 9.198 31.657 ;
     RECT  21.384 30.685 21.546 31.675 ;
     RECT  2.304 31.081 5.67 31.693 ;
     RECT  6.516 31.657 9.198 31.693 ;
     RECT  2.304 31.693 9.198 31.757 ;
     RECT  13.215 31.217 13.59 31.757 ;
     RECT  14.832 30.839 14.922 31.757 ;
     RECT  14.832 31.757 14.886 31.801 ;
     RECT  20.484 31.495 20.574 31.805 ;
     RECT  21.348 31.675 21.546 31.853 ;
     RECT  15.915 30.839 19.134 31.919 ;
     RECT  20.484 31.805 20.538 32.189 ;
     RECT  10.515 31.181 10.797 32.197 ;
     RECT  10.515 32.197 10.998 32.237 ;
     RECT  13.215 31.757 13.497 32.269 ;
     RECT  12.276 32.299 12.294 32.341 ;
     RECT  20.484 32.189 20.502 32.341 ;
     RECT  2.304 31.757 9.162 32.369 ;
     RECT  19.944 32.341 20.502 32.429 ;
     RECT  12.168 32.341 12.294 32.459 ;
     RECT  6.624 32.369 9.162 32.477 ;
     RECT  14.436 31.801 14.886 32.503 ;
     RECT  13.104 32.269 13.497 32.575 ;
     RECT  14.436 32.503 14.958 32.587 ;
     RECT  6.804 32.477 9.162 32.603 ;
     RECT  12.348 32.575 13.497 32.729 ;
     RECT  21.42 31.853 21.546 32.773 ;
     RECT  0.216 32.683 0.234 32.779 ;
     RECT  6.804 32.603 8.478 32.801 ;
     RECT  21.384 32.773 21.546 32.813 ;
     RECT  14.436 32.587 15.066 32.837 ;
     RECT  2.304 32.369 5.742 32.923 ;
     RECT  14.436 32.837 14.958 32.999 ;
     RECT  12.42 32.729 13.497 33.007 ;
     RECT  12.42 33.007 13.662 33.071 ;
     RECT  14.868 32.999 14.958 33.071 ;
     RECT  20.484 32.429 20.502 33.163 ;
     RECT  6.804 32.801 8.442 33.179 ;
     RECT  2.268 32.923 5.742 33.305 ;
     RECT  0.036 32.779 0.234 33.451 ;
     RECT  15.915 31.919 19.062 33.511 ;
     RECT  21.42 32.813 21.546 33.539 ;
     RECT  19.908 33.163 20.502 33.547 ;
     RECT  0.036 33.451 0.306 33.575 ;
     RECT  0.036 33.575 0.234 33.581 ;
     RECT  2.304 33.305 5.742 33.583 ;
     RECT  0.036 33.581 0.054 33.584 ;
     RECT  2.304 33.583 5.958 33.619 ;
     RECT  6.804 33.179 8.226 33.619 ;
     RECT  13.104 33.071 13.662 33.619 ;
     RECT  19.872 33.547 20.502 33.655 ;
     RECT  19.872 33.655 20.538 33.719 ;
     RECT  10.515 32.237 10.797 33.781 ;
     RECT  2.304 33.619 8.226 33.809 ;
     RECT  13.104 33.619 13.986 33.809 ;
     RECT  2.304 33.809 5.958 33.953 ;
     RECT  2.304 33.953 5.814 34.079 ;
     RECT  6.696 33.809 8.226 34.079 ;
     RECT  11.736 33.961 11.754 34.079 ;
     RECT  13.104 33.809 13.497 34.159 ;
     RECT  11.844 34.123 11.862 34.16 ;
     RECT  14.868 33.853 14.886 34.195 ;
     RECT  15.915 33.511 19.098 34.231 ;
     RECT  12.6 34.159 13.497 34.349 ;
     RECT  14.544 34.195 14.886 34.349 ;
     RECT  19.908 33.719 20.538 34.349 ;
     RECT  10.515 33.781 10.854 34.357 ;
     RECT  15.915 34.231 19.134 34.393 ;
     RECT  7.668 34.079 8.226 34.397 ;
     RECT  10.515 34.357 10.926 34.457 ;
     RECT  21.42 33.539 21.438 34.459 ;
     RECT  15.732 34.393 19.134 34.501 ;
     RECT  14.724 34.349 14.886 34.529 ;
     RECT  13.14 34.349 13.497 34.619 ;
     RECT  15.696 34.501 19.134 34.663 ;
     RECT  15.696 34.663 19.17 34.691 ;
     RECT  10.515 34.457 10.854 34.727 ;
     RECT  15.768 34.691 19.17 34.727 ;
     RECT  13.215 34.619 13.497 34.771 ;
     RECT  19.908 34.349 20.502 34.799 ;
     RECT  6.696 34.079 6.93 34.861 ;
     RECT  7.668 34.397 8.154 34.861 ;
     RECT  13.215 34.771 13.734 34.889 ;
     RECT  2.304 34.079 5.778 34.925 ;
     RECT  19.908 34.799 20.466 34.961 ;
     RECT  21.384 34.459 21.438 34.997 ;
     RECT  8.964 34.969 8.982 35.069 ;
     RECT  14.832 34.529 14.886 35.069 ;
     RECT  21.384 34.997 21.402 35.083 ;
     RECT  21.348 35.083 21.402 35.179 ;
     RECT  4.104 34.925 5.778 35.227 ;
     RECT  14.832 35.069 14.85 35.275 ;
     RECT  14.328 35.275 14.85 35.303 ;
     RECT  21.312 35.179 21.402 35.323 ;
     RECT  10.515 34.727 10.797 35.401 ;
     RECT  15.915 34.727 19.17 35.437 ;
     RECT  19.908 34.961 19.962 35.437 ;
     RECT  10.26 35.401 10.797 35.453 ;
     RECT  21.276 35.323 21.402 35.467 ;
     RECT  4.104 35.227 5.958 35.509 ;
     RECT  6.696 34.861 8.154 35.509 ;
     RECT  2.304 34.925 3.366 35.563 ;
     RECT  4.104 35.509 8.154 35.581 ;
     RECT  0.216 35.515 0.234 35.626 ;
     RECT  2.268 35.563 3.366 35.671 ;
     RECT  4.104 35.581 8.694 35.671 ;
     RECT  2.268 35.671 8.694 35.699 ;
     RECT  15.915 35.437 19.962 35.707 ;
     RECT  15.912 35.707 19.962 35.741 ;
     RECT  21.204 35.467 21.402 35.789 ;
     RECT  0.036 35.626 0.234 35.837 ;
     RECT  15.912 35.741 19.242 35.879 ;
     RECT  13.215 34.889 13.497 36.049 ;
     RECT  2.268 35.699 8.097 36.077 ;
     RECT  14.328 35.303 14.526 36.121 ;
     RECT  10.515 35.453 10.797 36.211 ;
     RECT  20.448 36.091 20.538 36.221 ;
     RECT  12.888 36.049 13.497 36.235 ;
     RECT  14.328 36.121 14.85 36.235 ;
     RECT  15.915 35.879 19.242 36.239 ;
     RECT  12.888 36.235 14.85 36.275 ;
     RECT  14.328 36.275 14.85 36.283 ;
     RECT  10.515 36.211 10.854 36.311 ;
     RECT  0.216 35.837 0.234 36.317 ;
     RECT  21.276 35.789 21.402 36.475 ;
     RECT  15.915 36.239 19.062 36.557 ;
     RECT  2.304 36.077 8.097 36.589 ;
     RECT  21.276 36.475 21.438 36.605 ;
     RECT  9.684 35.743 9.702 36.779 ;
     RECT  2.304 36.589 8.586 36.859 ;
     RECT  21.384 36.605 21.438 36.859 ;
     RECT  14.328 36.283 14.922 36.887 ;
     RECT  2.304 36.859 9.306 36.896 ;
     RECT  14.328 36.887 14.886 36.959 ;
     RECT  12.888 36.275 13.497 37.049 ;
     RECT  10.515 36.311 10.797 37.201 ;
     RECT  9.144 36.896 9.306 37.319 ;
     RECT  21.384 36.859 21.582 37.613 ;
     RECT  2.304 36.896 8.37 37.669 ;
     RECT  9.144 37.319 9.234 37.669 ;
     RECT  13.215 37.049 13.497 37.669 ;
     RECT  14.328 36.959 14.85 37.669 ;
     RECT  20.448 36.221 20.502 37.669 ;
     RECT  13.215 37.669 14.85 37.705 ;
     RECT  15.915 36.557 19.026 37.705 ;
     RECT  2.304 37.669 9.234 37.723 ;
     RECT  2.268 37.723 9.234 37.769 ;
     RECT  2.304 37.769 9.234 37.859 ;
     RECT  10.515 37.201 11.214 37.859 ;
     RECT  13.215 37.705 15.102 37.859 ;
     RECT  7.776 37.859 8.37 37.895 ;
     RECT  15.915 37.705 19.098 37.963 ;
     RECT  19.944 37.669 20.502 37.963 ;
     RECT  2.304 37.859 6.93 38.039 ;
     RECT  9.216 37.859 9.234 38.129 ;
     RECT  12.168 37.597 12.186 38.137 ;
     RECT  15.915 37.963 20.502 38.273 ;
     RECT  14.256 37.859 15.102 38.281 ;
     RECT  15.915 38.273 19.062 38.281 ;
     RECT  12.168 38.137 12.258 38.371 ;
     RECT  7.815 37.895 8.37 38.399 ;
     RECT  14.256 38.281 19.062 38.399 ;
     RECT  12.168 38.371 12.33 38.429 ;
     RECT  19.944 38.273 20.502 38.621 ;
     RECT  14.796 38.399 19.062 38.669 ;
     RECT  0.216 38.635 0.234 38.713 ;
     RECT  12.168 38.429 12.186 38.821 ;
     RECT  0.144 38.713 0.234 38.875 ;
     RECT  2.304 38.039 6.858 38.875 ;
     RECT  7.815 38.399 8.226 38.875 ;
     RECT  0.036 38.875 0.234 38.939 ;
     RECT  11.952 38.821 12.186 38.939 ;
     RECT  21.42 37.613 21.438 39.083 ;
     RECT  20.484 38.621 20.502 39.091 ;
     RECT  15.732 38.669 19.062 39.115 ;
     RECT  2.304 38.875 8.226 39.163 ;
     RECT  0.216 38.939 0.234 39.197 ;
     RECT  12.168 38.939 12.186 39.209 ;
     RECT  15.732 39.115 19.386 39.209 ;
     RECT  10.515 37.859 10.926 39.281 ;
     RECT  13.215 37.859 13.497 39.289 ;
     RECT  20.484 39.091 20.538 39.293 ;
     RECT  2.268 39.163 8.226 39.451 ;
     RECT  20.484 39.293 20.502 39.499 ;
     RECT  2.268 39.451 8.586 39.533 ;
     RECT  15.912 39.209 19.386 39.595 ;
     RECT  20.448 39.499 20.502 39.595 ;
     RECT  14.832 38.669 14.85 39.622 ;
     RECT  7.416 39.533 8.226 39.659 ;
     RECT  7.416 39.659 8.19 39.749 ;
     RECT  14.832 39.622 14.886 39.757 ;
     RECT  12.6 39.289 13.497 39.829 ;
     RECT  15.912 39.595 20.502 39.857 ;
     RECT  21.312 39.865 21.33 39.883 ;
     RECT  14.796 39.757 14.886 39.893 ;
     RECT  12.6 39.829 13.806 39.901 ;
     RECT  21.312 39.883 21.402 40.013 ;
     RECT  7.632 39.749 8.19 40.019 ;
     RECT  12.6 39.901 13.914 40.019 ;
     RECT  7.74 40.019 8.19 40.064 ;
     RECT  21.384 40.013 21.402 40.123 ;
     RECT  15.915 39.857 20.502 40.127 ;
     RECT  11.808 39.901 11.826 40.289 ;
     RECT  12.6 40.019 13.554 40.289 ;
     RECT  10.515 39.281 10.854 40.297 ;
     RECT  14.832 39.893 14.886 40.397 ;
     RECT  2.268 39.533 6.426 40.445 ;
     RECT  10.515 40.297 10.89 40.567 ;
     RECT  2.268 40.445 5.958 40.667 ;
     RECT  12.6 40.289 13.497 40.711 ;
     RECT  7.815 40.064 8.19 40.801 ;
     RECT  9.648 40.441 9.666 40.829 ;
     RECT  2.304 40.667 5.958 40.865 ;
     RECT  2.34 40.865 5.958 40.937 ;
     RECT  21.384 40.123 21.438 40.937 ;
     RECT  7.815 40.801 8.262 40.939 ;
     RECT  7.815 40.939 8.334 40.945 ;
     RECT  12.492 40.711 13.497 40.973 ;
     RECT  7.815 40.945 9.054 41.009 ;
     RECT  7.815 41.009 8.19 41.021 ;
     RECT  15.915 40.127 19.458 41.131 ;
     RECT  20.484 40.127 20.502 41.131 ;
     RECT  14.832 40.397 14.85 41.164 ;
     RECT  6.876 40.711 6.894 41.179 ;
     RECT  10.515 40.567 11.106 41.179 ;
     RECT  14.796 41.164 14.85 41.215 ;
     RECT  6.84 41.179 6.894 41.243 ;
     RECT  7.815 41.021 8.097 41.251 ;
     RECT  10.515 41.179 11.502 41.341 ;
     RECT  15.915 41.131 20.502 41.369 ;
     RECT  15.915 41.369 19.422 41.405 ;
     RECT  15.915 41.405 19.098 41.501 ;
     RECT  6.912 41.251 8.097 41.513 ;
     RECT  10.515 41.341 11.97 41.521 ;
     RECT  0.216 40.843 0.234 41.549 ;
     RECT  21.384 40.937 21.402 41.549 ;
     RECT  6.984 41.513 8.097 41.597 ;
     RECT  9.036 41.009 9.054 41.639 ;
     RECT  2.376 40.937 5.958 41.659 ;
     RECT  2.304 41.659 5.958 41.683 ;
     RECT  14.796 41.215 14.886 41.755 ;
     RECT  7.38 41.597 8.097 41.791 ;
     RECT  10.26 41.521 11.97 41.791 ;
     RECT  13.215 40.973 13.497 41.791 ;
     RECT  14.796 41.755 14.958 41.881 ;
     RECT  2.304 41.683 6.03 41.899 ;
     RECT  20.484 41.369 20.502 41.899 ;
     RECT  7.38 41.791 8.298 41.909 ;
     RECT  9.072 41.791 9.09 41.909 ;
     RECT  10.26 41.791 13.497 41.909 ;
     RECT  10.515 41.909 11.142 41.981 ;
     RECT  14.796 41.881 14.994 41.989 ;
     RECT  14.22 41.989 14.994 42.025 ;
     RECT  10.515 41.981 10.818 42.089 ;
     RECT  14.22 42.025 15.03 42.089 ;
     RECT  20.484 41.899 20.538 42.139 ;
     RECT  7.38 41.909 8.154 42.179 ;
     RECT  11.952 41.909 13.497 42.179 ;
     RECT  19.908 42.139 20.538 42.179 ;
     RECT  2.268 41.899 6.03 42.215 ;
     RECT  2.304 42.215 6.03 42.331 ;
     RECT  13.215 42.179 13.497 42.331 ;
     RECT  14.22 42.089 14.238 42.331 ;
     RECT  2.304 42.331 6.606 42.427 ;
     RECT  15.915 41.501 19.062 42.493 ;
     RECT  15.912 42.493 19.062 42.565 ;
     RECT  15.912 42.565 19.098 42.601 ;
     RECT  15.012 42.089 15.03 42.691 ;
     RECT  15.84 42.601 19.098 42.691 ;
     RECT  0.216 42.571 0.234 42.701 ;
     RECT  13.215 42.331 14.238 42.719 ;
     RECT  21.42 42.523 21.438 42.763 ;
     RECT  21.384 42.763 21.438 42.8 ;
     RECT  21.42 42.8 21.438 42.827 ;
     RECT  9.756 42.691 9.774 42.835 ;
     RECT  10.515 42.089 10.797 42.835 ;
     RECT  15.012 42.691 19.098 42.835 ;
     RECT  14.22 42.719 14.238 42.871 ;
     RECT  14.976 42.835 19.098 42.871 ;
     RECT  7.668 42.179 8.154 42.961 ;
     RECT  9.756 42.835 10.797 42.989 ;
     RECT  2.304 42.427 6.75 43.069 ;
     RECT  7.668 42.961 8.19 43.069 ;
     RECT  2.304 43.069 8.19 43.099 ;
     RECT  2.304 43.099 8.73 43.105 ;
     RECT  13.215 42.719 13.497 43.105 ;
     RECT  12.852 43.105 13.497 43.141 ;
     RECT  14.22 42.871 19.098 43.141 ;
     RECT  12.78 43.141 13.497 43.259 ;
     RECT  14.22 43.141 19.422 43.325 ;
     RECT  10.515 42.989 10.797 43.645 ;
     RECT  20.484 42.179 20.538 43.675 ;
     RECT  2.304 43.105 8.946 43.681 ;
     RECT  13.104 43.259 13.497 43.799 ;
     RECT  14.22 43.325 19.098 43.799 ;
     RECT  2.268 43.681 8.946 43.805 ;
     RECT  2.304 43.805 8.946 43.979 ;
     RECT  19.908 43.675 20.538 44.059 ;
     RECT  10.515 43.645 10.854 44.221 ;
     RECT  19.872 44.059 20.538 44.299 ;
     RECT  10.08 44.221 10.854 44.311 ;
     RECT  13.215 43.799 13.497 44.383 ;
     RECT  19.872 44.299 20.574 44.395 ;
     RECT  10.008 44.311 10.854 44.411 ;
     RECT  10.515 44.411 10.854 44.419 ;
     RECT  19.872 44.395 20.61 44.483 ;
     RECT  13.215 44.383 13.806 44.689 ;
     RECT  2.304 43.979 8.406 44.717 ;
     RECT  12.492 44.689 13.806 44.725 ;
     RECT  14.616 43.799 19.026 44.725 ;
     RECT  12.168 44.725 19.026 44.779 ;
     RECT  10.515 44.419 10.926 44.879 ;
     RECT  12.168 44.779 19.314 44.879 ;
     RECT  12.276 44.879 19.314 45.023 ;
     RECT  20.484 44.483 20.61 45.023 ;
     RECT  12.276 45.023 14.85 45.149 ;
     RECT  15.624 45.023 19.314 45.149 ;
     RECT  0.216 44.779 0.234 45.163 ;
     RECT  0.036 45.163 0.234 45.257 ;
     RECT  2.304 44.717 8.097 45.403 ;
     RECT  2.268 45.403 8.097 45.455 ;
     RECT  12.888 45.149 14.85 45.491 ;
     RECT  15.732 45.149 19.314 45.547 ;
     RECT  8.856 45.463 8.874 45.599 ;
     RECT  21.42 43.915 21.438 45.691 ;
     RECT  21.384 45.691 21.438 45.739 ;
     RECT  21.312 45.739 21.438 45.787 ;
     RECT  21.312 45.787 21.582 45.914 ;
     RECT  14.832 45.491 14.85 45.931 ;
     RECT  15.732 45.547 19.422 45.931 ;
     RECT  12.888 45.491 13.914 45.959 ;
     RECT  21.312 45.914 21.402 45.965 ;
     RECT  12.888 45.959 13.497 45.967 ;
     RECT  2.304 45.455 8.097 45.995 ;
     RECT  14.832 45.931 19.422 46.075 ;
     RECT  20.484 45.023 20.502 46.075 ;
     RECT  10.515 44.879 10.89 46.237 ;
     RECT  7.776 45.995 8.097 46.309 ;
     RECT  10.515 46.237 10.926 46.337 ;
     RECT  14.832 46.075 20.502 46.345 ;
     RECT  7.776 46.309 8.118 46.459 ;
     RECT  14.832 46.345 20.574 46.543 ;
     RECT  0.216 45.257 0.234 46.555 ;
     RECT  8.964 46.381 8.982 46.571 ;
     RECT  14.292 46.543 20.574 46.589 ;
     RECT  10.515 46.337 10.854 46.615 ;
     RECT  0.036 46.555 0.234 46.679 ;
     RECT  2.304 45.995 7.038 46.741 ;
     RECT  7.776 46.459 8.154 46.741 ;
     RECT  14.292 46.589 20.538 46.769 ;
     RECT  10.26 46.615 10.854 46.795 ;
     RECT  14.832 46.769 19.098 46.805 ;
     RECT  9.9 46.795 10.854 46.841 ;
     RECT  19.908 46.769 20.538 46.877 ;
     RECT  12.816 45.967 13.497 46.921 ;
     RECT  2.304 46.741 8.154 47.039 ;
     RECT  21.384 45.965 21.402 47.083 ;
     RECT  7.815 47.039 8.154 47.111 ;
     RECT  14.832 46.805 19.026 47.117 ;
     RECT  12.456 46.921 13.497 47.191 ;
     RECT  2.304 47.039 6.858 47.219 ;
     RECT  12.384 47.191 13.497 47.309 ;
     RECT  14.832 47.117 15.03 47.309 ;
     RECT  15.804 47.117 19.026 47.309 ;
     RECT  8.928 46.741 8.946 47.389 ;
     RECT  21.384 47.083 21.438 47.453 ;
     RECT  2.304 47.219 6.786 47.563 ;
     RECT  12.996 47.309 13.497 47.579 ;
     RECT  15.804 47.309 18.954 47.579 ;
     RECT  10.515 46.841 10.854 47.587 ;
     RECT  8.928 47.389 9.522 47.611 ;
     RECT  21.42 47.453 21.438 47.651 ;
     RECT  8.892 47.611 9.522 47.659 ;
     RECT  13.104 47.579 13.497 47.659 ;
     RECT  14.832 47.309 14.886 47.759 ;
     RECT  0.216 46.679 0.234 47.837 ;
     RECT  8.82 47.659 9.522 47.849 ;
     RECT  2.268 47.563 6.786 47.885 ;
     RECT  2.304 47.885 6.786 48.001 ;
     RECT  10.515 47.587 10.926 48.001 ;
     RECT  7.815 47.111 8.097 48.091 ;
     RECT  19.908 46.877 20.502 48.091 ;
     RECT  15.915 47.579 18.954 48.379 ;
     RECT  15.915 48.379 19.062 48.397 ;
     RECT  15.804 48.397 19.062 48.461 ;
     RECT  13.104 47.659 13.878 48.469 ;
     RECT  14.832 47.759 14.85 48.469 ;
     RECT  2.304 48.001 6.93 48.505 ;
     RECT  7.815 48.091 8.262 48.505 ;
     RECT  9.036 47.849 9.054 48.659 ;
     RECT  10.515 48.001 11.43 48.659 ;
     RECT  2.304 48.505 8.262 48.703 ;
     RECT  13.104 48.469 14.85 48.703 ;
     RECT  10.515 48.659 10.854 48.811 ;
     RECT  13.104 48.703 14.886 48.811 ;
     RECT  12.564 48.811 14.886 48.812 ;
     RECT  12.564 48.812 14.85 48.929 ;
     RECT  9.792 48.811 10.854 48.965 ;
     RECT  14.508 48.929 14.85 49.001 ;
     RECT  19.908 48.091 20.538 49.133 ;
     RECT  9.792 48.965 10.797 49.199 ;
     RECT  15.804 48.461 18.99 49.199 ;
     RECT  21.42 49.195 21.438 49.339 ;
     RECT  12.564 48.929 13.497 49.441 ;
     RECT  2.304 48.703 8.802 49.469 ;
     RECT  21.384 49.339 21.438 49.483 ;
     RECT  21.384 49.483 21.582 49.649 ;
     RECT  12.492 49.441 13.497 49.783 ;
     RECT  14.508 49.001 14.526 49.783 ;
     RECT  9.108 49.621 9.198 49.811 ;
     RECT  15.915 49.199 18.99 49.819 ;
     RECT  15.915 49.819 19.026 49.855 ;
     RECT  19.908 49.133 19.926 49.855 ;
     RECT  15.915 49.855 19.134 49.981 ;
     RECT  15.915 49.981 19.17 50.017 ;
     RECT  12.492 49.783 14.526 50.089 ;
     RECT  9.18 49.811 9.198 50.117 ;
     RECT  11.952 50.089 14.526 50.125 ;
     RECT  19.908 49.855 20.502 50.203 ;
     RECT  11.736 50.125 14.526 50.251 ;
     RECT  15.264 50.017 19.17 50.251 ;
     RECT  2.304 49.469 8.37 50.279 ;
     RECT  11.736 50.251 19.17 50.279 ;
     RECT  14.724 50.279 19.17 50.381 ;
     RECT  11.844 50.279 13.878 50.387 ;
     RECT  19.908 50.203 20.538 50.387 ;
     RECT  4.356 50.279 8.37 50.521 ;
     RECT  11.952 50.387 13.878 50.549 ;
     RECT  10.515 49.199 10.797 50.557 ;
     RECT  4.356 50.521 8.406 50.585 ;
     RECT  2.304 50.279 3.366 50.587 ;
     RECT  14.832 50.381 19.17 50.657 ;
     RECT  21.384 49.649 21.402 50.669 ;
     RECT  15.915 50.657 19.17 50.731 ;
     RECT  19.908 50.387 19.926 50.731 ;
     RECT  14.832 50.657 15.174 50.819 ;
     RECT  10.515 50.557 10.854 50.855 ;
     RECT  6.84 50.585 8.406 50.863 ;
     RECT  9.396 50.629 9.414 50.863 ;
     RECT  21.42 50.875 21.438 50.927 ;
     RECT  6.84 50.863 9.414 50.999 ;
     RECT  4.356 50.585 6.102 51.097 ;
     RECT  10.515 50.855 10.818 51.163 ;
     RECT  2.268 50.587 3.366 51.169 ;
     RECT  4.284 51.097 6.102 51.169 ;
     RECT  14.832 50.819 14.886 51.197 ;
     RECT  14.868 51.197 14.886 51.233 ;
     RECT  9.828 51.163 10.818 51.269 ;
     RECT  2.268 51.169 6.102 51.307 ;
     RECT  6.84 50.999 8.982 51.307 ;
     RECT  11.952 50.549 12.006 51.331 ;
     RECT  11.952 51.331 12.042 51.367 ;
     RECT  2.268 51.307 8.982 51.431 ;
     RECT  2.268 51.431 8.154 51.467 ;
     RECT  13.215 50.549 13.497 51.511 ;
     RECT  8.964 51.431 8.982 51.539 ;
     RECT  11.952 51.367 12.114 51.539 ;
     RECT  15.915 50.731 19.926 51.539 ;
     RECT  21.384 51.595 21.402 51.691 ;
     RECT  15.915 51.539 19.494 51.701 ;
     RECT  12.888 51.511 13.497 51.709 ;
     RECT  21.384 51.691 21.51 51.709 ;
     RECT  15.915 51.701 19.17 51.725 ;
     RECT  21.384 51.709 21.582 51.773 ;
     RECT  15.915 51.725 19.098 51.781 ;
     RECT  10.515 51.269 10.818 51.871 ;
     RECT  0.216 51.883 0.234 51.979 ;
     RECT  14.832 51.943 14.85 52.042 ;
     RECT  10.515 51.871 10.998 52.051 ;
     RECT  0.036 51.979 0.234 52.079 ;
     RECT  0.216 52.079 0.234 52.109 ;
     RECT  20.484 51.883 20.538 52.241 ;
     RECT  10.515 52.051 11.178 52.249 ;
     RECT  11.952 51.539 11.97 52.249 ;
     RECT  0.288 52.123 0.306 52.253 ;
     RECT  20.484 52.241 20.502 52.267 ;
     RECT  19.908 52.267 20.502 52.277 ;
     RECT  10.515 52.249 11.97 52.349 ;
     RECT  15.876 51.781 19.098 52.349 ;
     RECT  2.304 51.467 8.154 52.439 ;
     RECT  10.515 52.349 11.862 52.448 ;
     RECT  2.304 52.439 6.894 52.462 ;
     RECT  12.888 51.709 13.698 52.519 ;
     RECT  9 52.321 9.018 52.555 ;
     RECT  7.815 52.439 8.154 52.591 ;
     RECT  9 52.555 9.63 52.591 ;
     RECT  12.888 52.519 13.806 52.591 ;
     RECT  14.832 52.042 14.886 52.591 ;
     RECT  15.915 52.349 19.098 52.591 ;
     RECT  21.42 51.773 21.438 52.699 ;
     RECT  7.815 52.591 9.63 52.709 ;
     RECT  12.672 52.591 13.806 52.709 ;
     RECT  7.815 52.709 9.234 52.745 ;
     RECT  14.832 52.591 14.922 52.753 ;
     RECT  21.384 52.699 21.438 52.853 ;
     RECT  7.815 52.745 9.126 52.979 ;
     RECT  10.515 52.448 11.43 52.979 ;
     RECT  13.032 52.709 13.518 52.979 ;
     RECT  14.832 52.753 14.958 52.979 ;
     RECT  15.915 52.591 19.134 52.979 ;
     RECT  7.815 52.979 8.154 53.221 ;
     RECT  15.915 52.979 19.098 53.249 ;
     RECT  0.216 53.131 0.234 53.275 ;
     RECT  19.908 52.277 19.962 53.275 ;
     RECT  0.036 53.275 0.234 53.293 ;
     RECT  19.872 53.275 19.962 53.293 ;
     RECT  0.036 53.293 0.378 53.321 ;
     RECT  2.304 52.462 6.786 53.329 ;
     RECT  7.524 53.221 8.154 53.329 ;
     RECT  15.915 53.249 19.026 53.401 ;
     RECT  0.144 53.321 0.378 53.405 ;
     RECT  19.872 53.293 20.538 53.405 ;
     RECT  9.036 52.979 9.126 53.429 ;
     RECT  19.872 53.405 20.502 53.429 ;
     RECT  0.144 53.405 0.306 53.519 ;
     RECT  15.408 53.401 19.026 53.519 ;
     RECT  0.144 53.519 0.234 53.549 ;
     RECT  15.408 53.519 18.897 53.549 ;
     RECT  9.036 53.429 9.054 53.591 ;
     RECT  13.215 52.979 13.518 53.635 ;
     RECT  14.292 53.023 14.31 53.635 ;
     RECT  13.215 53.635 14.31 53.789 ;
     RECT  13.215 53.789 14.022 53.797 ;
     RECT  21.384 52.853 21.402 53.837 ;
     RECT  2.304 53.329 8.154 53.905 ;
     RECT  0.216 53.549 0.234 54.125 ;
     RECT  12.168 54.067 12.186 54.211 ;
     RECT  13.104 53.797 14.022 54.211 ;
     RECT  12.168 54.211 14.022 54.301 ;
     RECT  11.988 54.301 14.022 54.329 ;
     RECT  2.304 53.905 8.262 54.481 ;
     RECT  10.515 52.979 10.89 54.481 ;
     RECT  11.988 54.329 12.186 54.481 ;
     RECT  14.832 53.833 14.85 54.571 ;
     RECT  10.515 54.481 12.186 54.608 ;
     RECT  15.915 53.549 18.897 54.679 ;
     RECT  11.988 54.608 12.186 54.701 ;
     RECT  15.915 54.679 18.954 54.751 ;
     RECT  21.42 54.523 21.438 54.763 ;
     RECT  15.915 54.751 19.026 54.913 ;
     RECT  13.104 54.329 13.662 55.111 ;
     RECT  19.908 53.429 20.502 55.147 ;
     RECT  19.908 55.147 20.538 55.247 ;
     RECT  10.515 54.608 10.926 55.255 ;
     RECT  2.268 54.481 8.262 55.283 ;
     RECT  2.304 55.283 8.262 55.291 ;
     RECT  2.304 55.291 8.478 55.328 ;
     RECT  12.168 54.701 12.186 55.409 ;
     RECT  10.26 55.255 10.926 55.417 ;
     RECT  13.032 55.111 13.662 55.489 ;
     RECT  10.26 55.417 10.962 55.517 ;
     RECT  15.915 54.913 19.062 55.531 ;
     RECT  19.908 55.247 20.502 55.531 ;
     RECT  13.032 55.489 13.878 55.715 ;
     RECT  15.915 55.531 20.502 55.805 ;
     RECT  13.032 55.715 13.806 55.949 ;
     RECT  21.384 54.763 21.438 55.949 ;
     RECT  10.26 55.517 10.926 55.985 ;
     RECT  14.832 54.571 14.886 55.993 ;
     RECT  13.032 55.949 13.734 56.021 ;
     RECT  10.296 55.985 10.926 56.057 ;
     RECT  13.032 56.021 13.497 56.101 ;
     RECT  2.304 55.328 8.298 56.129 ;
     RECT  19.908 55.805 20.502 56.155 ;
     RECT  2.304 56.129 8.226 56.291 ;
     RECT  14.832 55.993 14.922 56.363 ;
     RECT  19.908 56.155 20.538 56.363 ;
     RECT  2.304 56.291 8.154 56.429 ;
     RECT  15.915 55.805 19.062 56.461 ;
     RECT  21.384 55.949 21.402 56.539 ;
     RECT  20.448 56.363 20.538 56.561 ;
     RECT  12.996 56.101 13.497 56.569 ;
     RECT  15.804 56.461 19.062 56.605 ;
     RECT  15.804 56.605 19.134 56.641 ;
     RECT  14.832 56.363 14.85 56.669 ;
     RECT  21.312 56.539 21.402 56.669 ;
     RECT  10.296 56.057 10.854 56.759 ;
     RECT  15.804 56.641 19.242 56.759 ;
     RECT  0.216 56.683 0.234 56.779 ;
     RECT  21.384 56.669 21.402 56.957 ;
     RECT  2.304 56.429 6.858 57.005 ;
     RECT  10.515 56.759 10.854 57.037 ;
     RECT  2.304 57.005 5.814 57.065 ;
     RECT  20.448 56.561 20.502 57.145 ;
     RECT  8.964 57.109 8.982 57.181 ;
     RECT  8.964 57.181 9.054 57.209 ;
     RECT  9.036 57.209 9.054 57.299 ;
     RECT  15.876 56.759 19.134 57.299 ;
     RECT  19.944 57.145 20.502 57.341 ;
     RECT  0.036 56.779 0.234 57.343 ;
     RECT  6.768 57.005 6.858 57.371 ;
     RECT  0.036 57.343 0.378 57.437 ;
     RECT  6.804 57.371 6.858 57.451 ;
     RECT  10.515 57.037 11.394 57.451 ;
     RECT  15.876 57.299 18.99 57.452 ;
     RECT  10.515 57.451 11.61 57.569 ;
     RECT  21.42 57.067 21.438 57.787 ;
     RECT  2.304 57.065 5.634 57.811 ;
     RECT  11.592 57.569 11.61 57.811 ;
     RECT  11.592 57.811 11.682 57.839 ;
     RECT  15.876 57.452 18.954 57.847 ;
     RECT  11.664 57.839 11.682 57.869 ;
     RECT  2.304 57.811 5.67 57.883 ;
     RECT  21.384 57.787 21.438 57.916 ;
     RECT  12.564 56.569 13.497 57.919 ;
     RECT  21.348 57.916 21.438 57.931 ;
     RECT  12.564 57.919 13.734 57.991 ;
     RECT  10.515 57.569 10.797 58.081 ;
     RECT  21.276 57.931 21.438 58.145 ;
     RECT  21.348 58.145 21.438 58.205 ;
     RECT  6.804 57.451 7.002 58.225 ;
     RECT  7.815 56.429 8.154 58.225 ;
     RECT  6.804 58.225 8.154 58.261 ;
     RECT  12.456 57.991 13.734 58.379 ;
     RECT  2.304 57.883 5.886 58.459 ;
     RECT  6.768 58.261 8.154 58.459 ;
     RECT  0.036 57.437 0.234 58.531 ;
     RECT  20.484 57.341 20.502 58.531 ;
     RECT  2.304 58.459 5.994 58.603 ;
     RECT  6.768 58.459 8.586 58.603 ;
     RECT  2.304 58.603 8.586 58.691 ;
     RECT  14.832 57.721 14.85 58.721 ;
     RECT  0.036 58.531 0.558 58.733 ;
     RECT  2.304 58.691 8.097 58.792 ;
     RECT  13.215 58.379 13.734 58.801 ;
     RECT  2.268 58.792 8.097 58.829 ;
     RECT  10.404 58.081 10.797 58.891 ;
     RECT  12.456 58.379 12.474 58.919 ;
     RECT  13.215 58.801 14.202 58.919 ;
     RECT  21.384 58.205 21.438 58.973 ;
     RECT  20.484 58.531 20.538 58.991 ;
     RECT  15.732 57.847 18.954 59.035 ;
     RECT  20.484 58.991 20.502 59.035 ;
     RECT  9.324 58.495 9.342 59.071 ;
     RECT  15.408 59.035 18.954 59.083 ;
     RECT  19.944 59.035 20.502 59.083 ;
     RECT  15.408 59.083 20.502 59.099 ;
     RECT  21.42 58.973 21.438 59.099 ;
     RECT  0.036 58.733 0.306 59.189 ;
     RECT  0.036 59.189 0.234 59.213 ;
     RECT  8.82 59.071 9.342 59.269 ;
     RECT  10.26 58.891 10.797 59.269 ;
     RECT  8.82 59.269 9.414 59.341 ;
     RECT  2.304 58.829 8.097 59.503 ;
     RECT  8.82 59.341 9.486 59.503 ;
     RECT  14.724 59.503 14.958 59.801 ;
     RECT  15.915 59.099 20.502 59.801 ;
     RECT  2.304 59.503 9.486 59.837 ;
     RECT  14.832 59.801 14.958 59.837 ;
     RECT  15.915 59.801 19.458 59.837 ;
     RECT  13.215 58.919 13.914 59.845 ;
     RECT  2.304 59.837 8.37 59.947 ;
     RECT  20.484 59.801 20.502 59.947 ;
     RECT  10.26 59.269 10.818 60.007 ;
     RECT  20.484 59.947 20.538 60.043 ;
     RECT  9.36 59.837 9.486 60.079 ;
     RECT  10.26 60.007 10.854 60.079 ;
     RECT  2.268 59.947 8.37 60.107 ;
     RECT  9.36 60.079 10.854 60.269 ;
     RECT  13.215 59.845 14.022 60.269 ;
     RECT  14.976 60.151 15.066 60.269 ;
     RECT  2.304 60.107 8.37 60.305 ;
     RECT  15.048 60.269 15.066 60.341 ;
     RECT  10.515 60.269 10.854 60.421 ;
     RECT  10.515 60.421 10.998 60.539 ;
     RECT  20.484 60.043 20.574 60.571 ;
     RECT  10.515 60.539 10.926 60.611 ;
     RECT  12.168 60.655 12.186 60.809 ;
     RECT  19.908 60.571 20.574 60.844 ;
     RECT  19.872 60.844 20.574 60.881 ;
     RECT  2.304 60.305 8.334 60.952 ;
     RECT  13.215 60.269 13.497 61.051 ;
     RECT  9.072 60.961 9.09 61.087 ;
     RECT  9.072 61.087 9.342 61.123 ;
     RECT  15.915 59.837 19.134 61.123 ;
     RECT  15.804 61.123 19.134 61.195 ;
     RECT  19.872 60.881 20.538 61.195 ;
     RECT  2.268 60.952 8.334 61.231 ;
     RECT  9.072 61.123 9.378 61.231 ;
     RECT  2.268 61.231 9.486 61.493 ;
     RECT  8.964 61.493 9.486 61.591 ;
     RECT  13.104 61.051 13.497 61.627 ;
     RECT  0.216 61.579 0.234 61.709 ;
     RECT  14.832 61.231 14.85 61.861 ;
     RECT  13.104 61.627 13.59 61.867 ;
     RECT  15.804 61.195 20.538 61.889 ;
     RECT  10.515 60.611 10.797 61.897 ;
     RECT  13.104 61.867 13.662 61.897 ;
     RECT  13.104 61.897 13.77 61.949 ;
     RECT  13.104 61.949 13.662 61.961 ;
     RECT  13.215 61.961 13.662 61.997 ;
     RECT  2.268 61.493 8.19 62.195 ;
     RECT  14.832 61.861 14.958 62.203 ;
     RECT  21.42 61.867 21.438 62.203 ;
     RECT  10.515 61.897 10.854 62.251 ;
     RECT  8.964 61.591 9.702 62.401 ;
     RECT  10.515 62.251 10.962 62.401 ;
     RECT  11.988 62.275 12.006 62.443 ;
     RECT  8.964 62.401 10.962 62.477 ;
     RECT  8.964 62.477 10.89 62.501 ;
     RECT  10.368 62.501 10.89 62.537 ;
     RECT  8.964 62.501 9.126 62.573 ;
     RECT  10.368 62.537 10.854 62.573 ;
     RECT  11.988 62.443 12.402 62.581 ;
     RECT  15.915 61.889 20.538 62.609 ;
     RECT  11.916 62.581 12.402 62.699 ;
     RECT  14.832 62.203 15.03 62.699 ;
     RECT  15.915 62.609 20.502 63.101 ;
     RECT  2.304 62.195 8.19 63.115 ;
     RECT  2.268 63.115 8.19 63.121 ;
     RECT  8.964 62.573 8.982 63.121 ;
     RECT  13.215 61.997 13.497 63.355 ;
     RECT  13.14 63.355 13.497 63.391 ;
     RECT  2.268 63.121 8.982 63.509 ;
     RECT  12.888 63.391 13.497 63.509 ;
     RECT  15.915 63.101 19.17 63.509 ;
     RECT  19.908 63.101 20.502 63.509 ;
     RECT  12.96 63.509 13.497 63.533 ;
     RECT  14.832 62.699 14.85 63.553 ;
     RECT  21.384 62.203 21.438 63.581 ;
     RECT  14.832 63.553 14.922 63.625 ;
     RECT  10.515 62.573 10.854 63.779 ;
     RECT  14.616 63.625 14.922 63.779 ;
     RECT  15.915 63.509 19.134 63.779 ;
     RECT  2.268 63.509 8.226 63.815 ;
     RECT  0.216 63.595 0.234 63.821 ;
     RECT  2.304 63.815 8.226 63.851 ;
     RECT  15.915 63.779 19.098 63.859 ;
     RECT  14.796 63.779 14.922 63.931 ;
     RECT  15.66 63.859 19.098 63.931 ;
     RECT  19.944 63.509 20.502 64.013 ;
     RECT  9.108 63.661 9.666 64.021 ;
     RECT  14.796 63.931 19.098 64.049 ;
     RECT  4.212 63.851 8.226 64.061 ;
     RECT  9.108 64.021 9.738 64.129 ;
     RECT  10.515 63.779 10.797 64.129 ;
     RECT  4.212 64.061 8.19 64.229 ;
     RECT  14.796 64.049 14.886 64.229 ;
     RECT  9.108 64.129 10.797 64.319 ;
     RECT  20.484 64.013 20.502 64.319 ;
     RECT  13.215 63.533 13.497 64.363 ;
     RECT  9.108 64.319 9.126 64.471 ;
     RECT  11.592 64.471 11.61 64.589 ;
     RECT  10.515 64.319 10.797 64.603 ;
     RECT  6.66 64.229 8.19 64.625 ;
     RECT  2.304 63.851 3.402 64.669 ;
     RECT  9.036 64.471 9.126 64.769 ;
     RECT  9.108 64.769 9.126 64.859 ;
     RECT  15.915 64.049 19.098 64.939 ;
     RECT  2.304 64.669 3.474 65.011 ;
     RECT  4.212 64.229 5.85 65.011 ;
     RECT  10.515 64.603 10.818 65.101 ;
     RECT  11.916 64.975 12.186 65.129 ;
     RECT  20.52 64.471 20.538 65.165 ;
     RECT  14.796 64.229 14.814 65.173 ;
     RECT  2.304 65.011 5.85 65.245 ;
     RECT  14.472 65.173 14.814 65.245 ;
     RECT  21.42 63.581 21.438 65.275 ;
     RECT  10.515 65.101 10.854 65.309 ;
     RECT  14.472 65.245 14.886 65.309 ;
     RECT  2.304 65.245 6.03 65.371 ;
     RECT  6.84 64.625 8.19 65.399 ;
     RECT  0.216 65.371 0.234 65.501 ;
     RECT  21.384 65.275 21.438 65.551 ;
     RECT  21.384 65.551 21.546 65.659 ;
     RECT  2.304 65.371 6.102 65.749 ;
     RECT  6.84 65.399 7.038 65.749 ;
     RECT  7.815 65.399 8.19 65.749 ;
     RECT  15.915 64.939 19.134 65.755 ;
     RECT  20.484 65.371 20.502 65.777 ;
     RECT  2.304 65.749 7.038 65.899 ;
     RECT  21.348 65.659 21.546 65.911 ;
     RECT  15.915 65.755 19.17 65.995 ;
     RECT  7.815 65.749 8.514 66.047 ;
     RECT  15.915 65.995 19.386 66.217 ;
     RECT  20.52 66.139 20.538 66.283 ;
     RECT  21.312 65.911 21.546 66.283 ;
     RECT  2.268 65.899 7.038 66.325 ;
     RECT  7.815 66.047 8.262 66.325 ;
     RECT  20.52 66.283 21.546 66.353 ;
     RECT  10.515 65.309 10.797 66.361 ;
     RECT  14.832 65.309 14.886 66.361 ;
     RECT  15.804 66.217 19.386 66.361 ;
     RECT  9.072 66.289 9.162 66.479 ;
     RECT  13.104 64.363 13.497 66.479 ;
     RECT  15.768 66.361 19.386 66.479 ;
     RECT  0.216 66.379 0.234 66.509 ;
     RECT  21.24 66.353 21.546 66.515 ;
     RECT  2.268 66.325 8.262 66.551 ;
     RECT  9.072 66.479 9.09 66.551 ;
     RECT  14.544 66.361 14.886 66.551 ;
     RECT  21.312 66.515 21.546 66.557 ;
     RECT  2.268 66.551 8.19 66.659 ;
     RECT  15.915 66.479 19.386 66.667 ;
     RECT  8.964 66.829 9.054 67.019 ;
     RECT  10.515 66.361 10.926 67.019 ;
     RECT  2.268 66.659 7.038 67.055 ;
     RECT  10.515 67.019 10.818 67.163 ;
     RECT  7.776 66.659 8.19 67.369 ;
     RECT  13.14 66.479 13.497 67.369 ;
     RECT  2.304 67.055 7.038 67.405 ;
     RECT  7.776 67.369 8.766 67.405 ;
     RECT  12.6 67.369 13.497 67.441 ;
     RECT  12.384 67.441 13.497 67.559 ;
     RECT  21.384 66.557 21.546 67.63 ;
     RECT  0.216 67.531 0.234 67.661 ;
     RECT  10.515 67.163 10.797 67.675 ;
     RECT  15.915 66.667 19.422 67.675 ;
     RECT  10.08 67.675 10.797 67.711 ;
     RECT  12.6 67.559 13.497 67.801 ;
     RECT  21.348 67.63 21.546 67.805 ;
     RECT  2.304 67.405 8.766 67.829 ;
     RECT  10.044 67.711 10.797 67.829 ;
     RECT  20.484 67.567 20.502 67.949 ;
     RECT  2.304 67.829 8.19 68.059 ;
     RECT  10.08 67.829 10.797 68.071 ;
     RECT  10.08 68.071 10.926 68.099 ;
     RECT  14.832 66.551 14.886 68.143 ;
     RECT  14.832 68.143 14.958 68.155 ;
     RECT  11.772 68.107 11.862 68.207 ;
     RECT  21.384 67.805 21.546 68.207 ;
     RECT  11.844 68.207 11.862 68.243 ;
     RECT  15.915 67.675 19.674 68.251 ;
     RECT  14.832 68.155 15.066 68.252 ;
     RECT  14.832 68.252 15.03 68.369 ;
     RECT  12.6 67.801 13.554 68.449 ;
     RECT  12.204 68.449 13.554 68.521 ;
     RECT  12.204 68.521 13.626 68.639 ;
     RECT  21.42 68.207 21.546 68.639 ;
     RECT  2.268 68.059 8.19 68.683 ;
     RECT  21.42 68.639 21.438 68.783 ;
     RECT  2.268 68.683 8.406 68.981 ;
     RECT  10.515 68.099 10.926 69.061 ;
     RECT  14.832 68.369 14.85 69.151 ;
     RECT  2.268 68.981 8.19 69.163 ;
     RECT  9.036 69.061 9.054 69.179 ;
     RECT  10.515 69.061 11.214 69.179 ;
     RECT  15.915 68.251 19.962 69.307 ;
     RECT  12.384 68.639 13.626 69.331 ;
     RECT  2.232 69.163 8.19 69.341 ;
     RECT  2.232 69.341 8.097 69.359 ;
     RECT  12.384 69.331 13.914 69.449 ;
     RECT  10.515 69.179 11.142 69.485 ;
     RECT  10.515 69.485 10.797 69.601 ;
     RECT  12.744 69.449 13.914 69.719 ;
     RECT  0.216 69.691 0.234 69.787 ;
     RECT  0.036 69.787 0.234 69.821 ;
     RECT  13.068 69.719 13.914 69.871 ;
     RECT  14.832 69.151 15.03 69.871 ;
     RECT  10.188 69.601 10.797 69.989 ;
     RECT  2.304 69.359 8.097 70.025 ;
     RECT  0.036 69.821 0.054 70.061 ;
     RECT  2.415 70.025 8.097 70.061 ;
     RECT  13.068 69.871 15.03 70.141 ;
     RECT  13.068 70.141 15.102 70.259 ;
     RECT  2.415 70.061 6.426 70.295 ;
     RECT  7.596 70.061 8.097 70.295 ;
     RECT  13.068 70.259 15.066 70.331 ;
     RECT  15.915 69.307 20.214 70.367 ;
     RECT  11.664 70.303 11.682 70.439 ;
     RECT  13.215 70.331 15.066 70.529 ;
     RECT  14.256 70.529 15.03 70.601 ;
     RECT  7.74 70.295 8.097 70.637 ;
     RECT  14.256 70.601 14.994 70.637 ;
     RECT  14.256 70.637 14.886 70.673 ;
     RECT  14.256 70.673 14.274 70.709 ;
     RECT  2.415 70.295 6.246 70.799 ;
     RECT  15.915 70.367 19.926 70.799 ;
     RECT  2.415 70.799 3.726 70.835 ;
     RECT  3.708 70.835 3.726 70.979 ;
     RECT  6.228 70.799 6.246 71.069 ;
     RECT  18.108 70.799 19.854 71.069 ;
     RECT  4.572 70.799 5.397 71.105 ;
     RECT  17.244 70.799 17.262 71.105 ;
     RECT  15.915 70.799 16.506 71.375 ;
     RECT  18.504 71.069 19.854 71.609 ;
     RECT  18.504 71.609 19.674 71.645 ;
     RECT  18.615 71.645 19.674 71.879 ;
     RECT  18.615 71.879 19.35 72.149 ;
     RECT  18.615 72.149 19.026 72.185 ;
     RECT  2.415 70.835 2.697 73.187 ;
     RECT  5.115 71.105 5.397 73.187 ;
     RECT  7.815 70.637 8.097 73.187 ;
     RECT  10.515 69.989 10.797 73.187 ;
     RECT  13.215 70.529 13.497 73.187 ;
     RECT  15.915 71.375 16.197 73.187 ;
     RECT  18.615 72.185 18.897 73.187 ;
     RECT  2.415 73.187 2.505 73.457 ;
     RECT  5.115 73.187 5.205 73.457 ;
     RECT  7.815 73.187 7.905 73.457 ;
     RECT  10.515 73.187 10.605 73.457 ;
     RECT  13.215 73.187 13.305 73.457 ;
     RECT  15.915 73.187 16.005 73.457 ;
     RECT  18.615 73.187 18.705 73.457 ;
    LAYER M4 ;
     RECT  0.025 7.392 0.108 7.944 ;
     RECT  0.025 29.52 0.108 30.408 ;
     RECT  0.025 32.784 0.108 33.576 ;
     RECT  0.025 56.784 0.108 59.208 ;
     RECT  0.025 69.792 0.108 70.056 ;
     RECT  0.108 5.424 2.408 70.056 ;
     RECT  2.408 2.148 2.512 73.452 ;
     RECT  2.512 2.418 2.704 73.182 ;
     RECT  2.704 13.872 2.729 14.664 ;
     RECT  2.704 21.168 2.729 26.904 ;
     RECT  2.704 6 2.765 7.944 ;
     RECT  2.704 15.744 2.765 17.256 ;
     RECT  2.729 21.168 2.765 26.616 ;
     RECT  2.704 34.896 2.765 48.504 ;
     RECT  2.704 50.304 2.765 54.408 ;
     RECT  2.704 56.784 2.765 61.992 ;
     RECT  2.704 63.792 2.765 70.68 ;
     RECT  2.765 34.896 2.801 42.6 ;
     RECT  2.704 9.072 2.837 12.312 ;
     RECT  2.765 56.784 2.837 60.36 ;
     RECT  2.765 67.632 2.837 68.424 ;
     RECT  2.765 7.392 2.873 7.944 ;
     RECT  2.704 19.296 2.873 19.848 ;
     RECT  2.765 53.28 2.873 54.12 ;
     RECT  2.837 58.656 2.873 60.36 ;
     RECT  2.765 65.472 2.873 66.552 ;
     RECT  2.837 9.072 2.909 9.096 ;
     RECT  2.837 10.176 2.909 12.312 ;
     RECT  2.704 27.888 2.909 28.248 ;
     RECT  2.873 58.656 2.909 60.12 ;
     RECT  2.765 50.304 2.945 51.144 ;
     RECT  2.873 7.392 2.981 7.752 ;
     RECT  2.765 44.4 2.981 48.504 ;
     RECT  2.837 56.784 2.981 57.432 ;
     RECT  2.909 10.176 3.017 10.728 ;
     RECT  2.765 16.608 3.017 17.256 ;
     RECT  2.765 23.088 3.017 26.616 ;
     RECT  2.704 29.52 3.017 33.288 ;
     RECT  2.765 52.224 3.017 52.296 ;
     RECT  2.981 57.408 3.017 57.432 ;
     RECT  2.837 67.632 3.017 67.704 ;
     RECT  2.765 6 3.089 6.024 ;
     RECT  2.801 34.896 3.089 36.6 ;
     RECT  2.873 53.28 3.089 53.88 ;
     RECT  2.765 63.792 3.089 64.392 ;
     RECT  2.981 7.728 3.125 7.752 ;
     RECT  3.017 10.704 3.125 10.728 ;
     RECT  3.017 29.52 3.125 32.808 ;
     RECT  2.981 44.4 3.125 45.192 ;
     RECT  3.089 64.128 3.125 64.392 ;
     RECT  3.017 25.104 3.161 26.616 ;
     RECT  3.161 26.592 3.197 26.616 ;
     RECT  2.765 21.168 3.233 22.056 ;
     RECT  3.125 44.4 3.233 44.712 ;
     RECT  2.765 61.344 3.233 61.368 ;
     RECT  2.873 66.528 3.233 66.552 ;
     RECT  3.233 22.032 3.269 22.056 ;
     RECT  2.729 14.64 3.305 14.664 ;
     RECT  3.125 29.52 3.305 31.896 ;
     RECT  2.801 37.584 3.305 42.6 ;
     RECT  2.873 65.472 3.305 65.496 ;
     RECT  3.017 67.632 3.305 67.656 ;
     RECT  3.305 31.152 3.341 31.896 ;
     RECT  2.981 46.56 3.341 48.504 ;
     RECT  3.017 52.224 3.341 52.248 ;
     RECT  2.909 27.888 3.377 27.912 ;
     RECT  3.125 64.128 3.377 64.152 ;
     RECT  2.909 11.712 3.413 12.312 ;
     RECT  3.089 34.896 3.413 36.36 ;
     RECT  3.161 25.104 3.629 25.128 ;
     RECT  3.305 40.992 3.733 42.6 ;
     RECT  3.305 29.52 3.74 29.88 ;
     RECT  3.413 34.896 3.769 35.352 ;
     RECT  2.765 69.792 3.769 70.68 ;
     RECT  3.733 40.992 3.797 43.128 ;
     RECT  3.769 55.92 3.841 55.944 ;
     RECT  3.017 17.232 3.877 17.256 ;
     RECT  3.797 40.992 3.925 43.368 ;
     RECT  3.233 44.4 3.925 44.616 ;
     RECT  3.089 53.856 4.061 53.88 ;
     RECT  3.017 23.088 4.201 23.976 ;
     RECT  3.769 34.224 4.201 35.352 ;
     RECT  3.925 40.992 4.201 44.616 ;
     RECT  4.093 10.608 4.309 10.632 ;
     RECT  3.74 29.472 4.345 29.88 ;
     RECT  2.909 58.656 4.345 60.024 ;
     RECT  4.201 40.992 4.381 45.48 ;
     RECT  3.341 46.752 4.381 48.504 ;
     RECT  3.877 17.232 4.405 17.928 ;
     RECT  4.309 19.584 4.405 19.608 ;
     RECT  4.021 20.976 4.405 21 ;
     RECT  2.945 50.304 4.405 50.328 ;
     RECT  4.093 52.416 4.405 52.44 ;
     RECT  3.341 31.872 4.412 31.896 ;
     RECT  4.345 63.504 4.417 63.528 ;
     RECT  4.273 64.704 4.417 64.728 ;
     RECT  4.405 20.976 4.453 21.384 ;
     RECT  4.201 22.752 4.453 23.976 ;
     RECT  4.345 28.416 4.453 28.44 ;
     RECT  4.345 29.472 4.453 30.648 ;
     RECT  3.841 55.152 4.453 55.944 ;
     RECT  4.345 58.464 4.453 60.024 ;
     RECT  4.417 63.504 4.453 64.728 ;
     RECT  4.021 66.624 4.453 66.648 ;
     RECT  4.309 67.632 4.453 67.656 ;
     RECT  4.405 17.232 4.489 19.608 ;
     RECT  4.381 40.992 4.489 48.936 ;
     RECT  4.405 50.304 4.489 51 ;
     RECT  4.489 17.136 4.501 19.608 ;
     RECT  4.489 40.992 4.501 48.984 ;
     RECT  4.489 50.304 4.501 51.336 ;
     RECT  4.453 55.152 4.501 56.52 ;
     RECT  4.453 63.504 4.501 65.304 ;
     RECT  4.453 66.624 4.501 67.656 ;
     RECT  4.489 7.968 4.561 7.992 ;
     RECT  4.453 58.128 4.561 60.024 ;
     RECT  4.412 31.872 4.633 32.184 ;
     RECT  3.985 12.336 4.777 12.36 ;
     RECT  4.561 7.872 4.813 7.992 ;
     RECT  4.501 54.864 4.813 57.048 ;
     RECT  4.501 17.136 4.849 19.944 ;
     RECT  4.453 20.976 4.849 23.976 ;
     RECT  4.201 34.032 4.849 35.352 ;
     RECT  4.309 15.984 4.885 16.008 ;
     RECT  4.849 17.136 4.885 23.976 ;
     RECT  4.849 33.648 4.933 35.352 ;
     RECT  3.413 36.336 4.933 36.36 ;
     RECT  4.501 40.992 4.933 51.336 ;
     RECT  4.561 58.128 4.933 60.312 ;
     RECT  4.489 61.392 4.933 61.416 ;
     RECT  4.741 6.24 4.993 6.264 ;
     RECT  4.885 15.984 5.029 23.976 ;
     RECT  4.597 25.296 5.029 25.32 ;
     RECT  4.933 33.648 5.101 36.36 ;
     RECT  3.305 37.584 5.101 39.912 ;
     RECT  4.933 40.896 5.101 51.336 ;
     RECT  4.405 52.368 5.101 52.44 ;
     RECT  3.769 69.024 5.101 70.68 ;
     RECT  4.993 5.856 5.108 6.264 ;
     RECT  4.813 7.872 5.108 8.52 ;
     RECT  4.309 10.608 5.108 10.728 ;
     RECT  4.777 12.336 5.108 12.552 ;
     RECT  4.813 14.928 5.108 14.952 ;
     RECT  5.029 15.984 5.108 25.32 ;
     RECT  4.453 28.416 5.108 30.648 ;
     RECT  4.633 31.632 5.108 32.184 ;
     RECT  5.101 33.648 5.108 39.912 ;
     RECT  5.101 40.896 5.108 52.44 ;
     RECT  4.46 53.568 5.108 53.592 ;
     RECT  4.813 54.624 5.108 57.048 ;
     RECT  4.933 58.128 5.108 61.416 ;
     RECT  4.501 63.216 5.108 67.656 ;
     RECT  5.101 68.928 5.108 70.68 ;
     RECT  5.108 2.148 5.212 73.452 ;
     RECT  5.212 2.418 5.404 73.182 ;
     RECT  5.404 24.384 5.465 25.416 ;
     RECT  5.404 61.392 5.465 67.656 ;
     RECT  5.404 9.648 5.537 14.952 ;
     RECT  5.404 58.464 5.555 60.408 ;
     RECT  5.404 26.496 5.645 27.336 ;
     RECT  5.537 9.648 5.651 10.296 ;
     RECT  5.404 16.368 5.651 20.088 ;
     RECT  5.404 21.552 5.717 23.4 ;
     RECT  5.404 7.344 5.753 8.52 ;
     RECT  5.717 21.936 5.753 23.4 ;
     RECT  5.537 11.376 5.789 14.952 ;
     RECT  5.651 19.392 5.789 20.088 ;
     RECT  5.404 68.928 5.789 68.952 ;
     RECT  5.789 11.904 5.795 14.952 ;
     RECT  5.651 16.368 5.795 17.928 ;
     RECT  5.404 28.416 5.795 31.56 ;
     RECT  5.404 34.512 5.795 41.928 ;
     RECT  5.404 5.856 5.861 6.264 ;
     RECT  5.753 8.496 5.933 8.52 ;
     RECT  5.795 11.904 5.933 13.656 ;
     RECT  5.404 43.008 5.933 53.112 ;
     RECT  5.465 61.392 5.987 67.56 ;
     RECT  5.987 61.584 6.005 67.56 ;
     RECT  6.005 61.584 6.323 67.176 ;
     RECT  5.933 43.008 6.329 51.384 ;
     RECT  5.795 28.416 6.371 31.128 ;
     RECT  5.933 52.416 6.373 53.112 ;
     RECT  6.323 63.216 6.401 63.24 ;
     RECT  6.323 64.32 6.467 67.176 ;
     RECT  5.753 23.136 6.505 23.4 ;
     RECT  5.795 35.232 6.563 41.928 ;
     RECT  6.563 37.632 6.649 41.928 ;
     RECT  6.329 43.008 6.649 47.64 ;
     RECT  6.505 23.136 6.653 23.928 ;
     RECT  5.555 58.464 6.653 60.312 ;
     RECT  6.649 37.632 6.659 47.64 ;
     RECT  5.753 7.344 6.685 7.368 ;
     RECT  6.613 32.448 6.707 32.472 ;
     RECT  5.404 70.128 6.721 70.152 ;
     RECT  6.661 33.744 6.748 33.768 ;
     RECT  6.653 58.464 6.755 59.256 ;
     RECT  5.795 17.136 6.757 17.928 ;
     RECT  6.563 35.232 6.757 36.6 ;
     RECT  6.685 18.912 6.792 18.936 ;
     RECT  5.933 11.904 6.793 12.216 ;
     RECT  5.404 54.096 6.797 57.048 ;
     RECT  6.797 54.096 6.803 56.472 ;
     RECT  5.795 14.928 6.829 14.952 ;
     RECT  6.757 16.512 6.829 17.928 ;
     RECT  5.465 25.296 6.829 25.416 ;
     RECT  5.645 26.64 6.829 27.336 ;
     RECT  6.371 29.04 6.829 31.128 ;
     RECT  6.685 6.816 6.853 7.368 ;
     RECT  6.829 14.88 6.853 17.928 ;
     RECT  6.792 18.912 6.853 19.512 ;
     RECT  6.853 6.24 6.86 7.368 ;
     RECT  6.86 6.24 6.865 8.136 ;
     RECT  5.651 10.272 6.865 10.296 ;
     RECT  6.793 11.28 6.865 12.216 ;
     RECT  6.829 29.04 6.865 31.416 ;
     RECT  5.933 13.632 6.908 13.656 ;
     RECT  6.853 14.88 6.908 19.512 ;
     RECT  6.829 25.296 7.009 27.336 ;
     RECT  7.009 25.296 7.045 28.008 ;
     RECT  6.949 60.528 7.081 60.552 ;
     RECT  6.721 69.84 7.261 70.152 ;
     RECT  7.261 69.312 7.381 70.152 ;
     RECT  6.757 34.752 7.657 36.6 ;
     RECT  6.755 59.184 7.693 59.256 ;
     RECT  7.081 60.528 7.693 60.84 ;
     RECT  6.865 6.144 7.808 8.136 ;
     RECT  6.865 10.272 7.808 12.216 ;
     RECT  6.908 13.632 7.808 19.512 ;
     RECT  5.753 21.936 7.808 21.96 ;
     RECT  6.653 23.136 7.808 23.16 ;
     RECT  7.045 25.056 7.808 28.008 ;
     RECT  6.865 29.04 7.808 31.752 ;
     RECT  7.657 34.368 7.808 36.6 ;
     RECT  6.659 37.632 7.808 43.32 ;
     RECT  6.659 44.448 7.808 47.64 ;
     RECT  6.329 48.672 7.808 51.384 ;
     RECT  6.373 52.416 7.808 52.44 ;
     RECT  6.803 54.672 7.808 56.472 ;
     RECT  6.908 58.08 7.808 58.104 ;
     RECT  7.693 59.184 7.808 60.84 ;
     RECT  6.467 64.32 7.808 66.696 ;
     RECT  7.381 69.312 7.808 70.248 ;
     RECT  7.808 2.148 7.912 73.452 ;
     RECT  7.912 2.418 8.104 73.182 ;
     RECT  8.104 39.504 8.165 44.712 ;
     RECT  8.104 50.016 8.165 50.664 ;
     RECT  8.104 16.368 8.201 17.688 ;
     RECT  8.104 31.104 8.201 31.8 ;
     RECT  8.104 64.032 8.201 64.344 ;
     RECT  8.104 69.312 8.201 69.336 ;
     RECT  8.104 34.08 8.237 34.392 ;
     RECT  8.104 66.192 8.237 66.312 ;
     RECT  8.165 43.056 8.243 44.712 ;
     RECT  8.104 46.464 8.243 48.696 ;
     RECT  8.104 25.248 8.281 27.336 ;
     RECT  8.243 46.8 8.284 48.696 ;
     RECT  8.104 23.568 8.291 23.592 ;
     RECT  8.104 11.952 8.309 13.128 ;
     RECT  8.165 39.504 8.345 42.024 ;
     RECT  8.201 16.368 8.38 17.64 ;
     RECT  8.104 58.656 8.387 61.032 ;
     RECT  8.387 61.008 8.389 61.032 ;
     RECT  8.104 29.088 8.417 29.112 ;
     RECT  8.387 58.656 8.428 59.832 ;
     RECT  8.309 11.952 8.489 12.504 ;
     RECT  8.104 55.296 8.489 55.32 ;
     RECT  8.38 17.616 8.525 17.64 ;
     RECT  8.345 39.504 8.597 40.056 ;
     RECT  8.243 43.056 8.633 43.32 ;
     RECT  8.284 46.8 8.921 47.64 ;
     RECT  8.201 31.104 9.169 31.128 ;
     RECT  8.38 16.368 9.385 16.44 ;
     RECT  8.201 64.032 9.709 64.056 ;
     RECT  8.104 35.712 10.249 36.888 ;
     RECT  8.104 62.448 10.357 62.472 ;
     RECT  10.105 18.96 10.429 18.984 ;
     RECT  8.489 11.952 10.508 11.976 ;
     RECT  8.104 14.928 10.508 14.952 ;
     RECT  9.385 16.368 10.508 16.92 ;
     RECT  10.429 18.72 10.508 18.984 ;
     RECT  8.104 21.936 10.508 21.96 ;
     RECT  8.281 25.248 10.508 26.664 ;
     RECT  10.429 27.888 10.508 27.912 ;
     RECT  9.169 31.104 10.508 31.752 ;
     RECT  8.237 34.08 10.508 34.104 ;
     RECT  10.249 35.424 10.508 36.888 ;
     RECT  8.104 37.92 10.508 38.52 ;
     RECT  8.597 40.032 10.508 40.056 ;
     RECT  8.345 41.904 10.508 42.024 ;
     RECT  8.633 43.056 10.508 43.128 ;
     RECT  8.243 44.688 10.508 44.712 ;
     RECT  8.921 46.8 10.508 46.824 ;
     RECT  8.284 48.672 10.508 48.696 ;
     RECT  8.165 50.016 10.508 50.04 ;
     RECT  9.817 51.168 10.508 51.192 ;
     RECT  8.428 59.472 10.508 59.832 ;
     RECT  10.357 62.448 10.508 62.568 ;
     RECT  9.709 64.032 10.508 64.104 ;
     RECT  8.237 66.192 10.508 66.216 ;
     RECT  10.508 2.148 10.612 73.452 ;
     RECT  10.612 2.418 10.804 73.182 ;
     RECT  10.804 34.08 11.833 34.104 ;
     RECT  10.804 50.016 11.833 50.04 ;
     RECT  10.804 51.168 11.833 51.192 ;
     RECT  10.804 54.576 11.977 54.6 ;
     RECT  11.833 50.016 11.981 51.192 ;
     RECT  11.977 54.576 12.017 54.696 ;
     RECT  10.804 31.104 12.265 32.232 ;
     RECT  10.804 25.248 12.301 26.664 ;
     RECT  10.804 27.888 12.301 27.912 ;
     RECT  10.804 62.256 12.949 62.568 ;
     RECT  10.804 64.032 12.949 64.632 ;
     RECT  10.804 16.32 13.045 16.92 ;
     RECT  10.804 10.128 13.208 10.152 ;
     RECT  10.804 11.952 13.208 11.976 ;
     RECT  10.804 14.112 13.208 14.952 ;
     RECT  13.045 16.32 13.208 17.112 ;
     RECT  10.804 18.72 13.208 18.984 ;
     RECT  10.804 21.936 13.208 21.96 ;
     RECT  13.129 23.28 13.208 23.304 ;
     RECT  12.301 25.248 13.208 27.912 ;
     RECT  10.804 29.232 13.208 29.256 ;
     RECT  12.265 31.104 13.208 32.328 ;
     RECT  11.833 34.08 13.208 34.152 ;
     RECT  10.804 35.424 13.208 36.888 ;
     RECT  10.804 37.92 13.208 38.52 ;
     RECT  10.804 40.032 13.208 40.872 ;
     RECT  10.804 41.904 13.208 42.024 ;
     RECT  10.804 43.056 13.208 43.128 ;
     RECT  10.804 44.688 13.208 44.712 ;
     RECT  10.804 48.096 13.208 48.696 ;
     RECT  11.981 50.016 13.208 51.096 ;
     RECT  11.833 52.416 13.208 52.44 ;
     RECT  12.017 54.672 13.208 54.696 ;
     RECT  13.057 56.304 13.208 56.328 ;
     RECT  10.804 57.312 13.208 57.864 ;
     RECT  10.804 59.472 13.208 59.832 ;
     RECT  12.949 62.256 13.208 64.632 ;
     RECT  10.804 66.192 13.208 66.216 ;
     RECT  13.208 2.148 13.312 73.452 ;
     RECT  13.312 2.418 13.504 73.182 ;
     RECT  13.504 16.32 13.601 17.112 ;
     RECT  13.504 59.472 13.619 59.832 ;
     RECT  13.504 10.128 14.713 10.152 ;
     RECT  13.504 11.952 14.821 11.976 ;
     RECT  13.504 13.008 14.821 13.032 ;
     RECT  13.601 16.32 14.821 16.968 ;
     RECT  13.504 21.936 14.821 21.96 ;
     RECT  13.504 35.424 14.821 36.84 ;
     RECT  13.504 40.032 14.821 40.872 ;
     RECT  13.504 41.904 14.821 42.072 ;
     RECT  13.504 50.016 14.821 51.096 ;
     RECT  13.619 59.472 14.821 59.736 ;
     RECT  13.504 66.192 14.821 66.216 ;
     RECT  13.504 18.72 14.857 18.984 ;
     RECT  13.504 31.104 14.857 32.328 ;
     RECT  13.504 52.416 14.857 52.44 ;
     RECT  13.504 54.576 14.857 54.6 ;
     RECT  14.713 10.032 14.861 10.152 ;
     RECT  14.821 11.952 14.861 13.032 ;
     RECT  13.504 25.152 14.861 27.912 ;
     RECT  13.504 43.056 14.861 43.272 ;
     RECT  13.504 44.592 14.861 45.48 ;
     RECT  13.504 47.136 14.861 48.696 ;
     RECT  14.821 66.192 14.861 66.312 ;
     RECT  14.857 52.272 14.897 52.44 ;
     RECT  14.857 54.576 14.897 54.696 ;
     RECT  13.504 61.872 14.933 64.632 ;
     RECT  14.861 47.136 15.397 47.16 ;
     RECT  14.821 59.472 15.397 59.832 ;
     RECT  14.857 18.72 15.865 19.08 ;
     RECT  14.861 10.128 15.908 10.152 ;
     RECT  14.861 11.952 15.908 12.888 ;
     RECT  13.504 14.112 15.908 14.952 ;
     RECT  14.821 16.32 15.908 17.112 ;
     RECT  15.865 18.192 15.908 19.08 ;
     RECT  14.821 21.408 15.908 21.96 ;
     RECT  13.504 23.28 15.908 23.304 ;
     RECT  14.861 25.248 15.908 27.912 ;
     RECT  13.504 29.232 15.908 29.256 ;
     RECT  14.857 31.104 15.908 32.616 ;
     RECT  13.504 34.08 15.908 34.152 ;
     RECT  14.821 35.424 15.908 36.888 ;
     RECT  13.504 37.92 15.908 38.52 ;
     RECT  14.821 40.032 15.908 42.072 ;
     RECT  14.861 43.056 15.908 43.128 ;
     RECT  14.861 44.688 15.908 45.48 ;
     RECT  15.397 47.088 15.908 47.16 ;
     RECT  14.861 48.192 15.908 48.696 ;
     RECT  14.821 50.016 15.908 51.192 ;
     RECT  14.897 52.272 15.908 52.296 ;
     RECT  15.397 53.52 15.908 53.544 ;
     RECT  14.897 54.672 15.908 54.696 ;
     RECT  13.504 56.304 15.908 56.328 ;
     RECT  13.504 57.312 15.908 57.864 ;
     RECT  15.397 59.04 15.908 59.832 ;
     RECT  14.933 61.92 15.908 64.632 ;
     RECT  14.861 66.288 15.908 66.312 ;
     RECT  14.857 68.16 15.908 68.184 ;
     RECT  15.908 2.148 16.012 73.452 ;
     RECT  16.012 2.418 16.204 73.182 ;
     RECT  16.204 44.64 17.197 64.632 ;
     RECT  16.204 65.616 17.197 69.48 ;
     RECT  16.204 10.032 17.233 10.152 ;
     RECT  16.204 11.136 17.233 43.656 ;
     RECT  17.197 44.64 17.233 69.48 ;
     RECT  17.233 11.136 17.417 69.48 ;
     RECT  17.233 9.936 17.449 10.152 ;
     RECT  17.449 9.648 17.521 10.152 ;
     RECT  17.417 11.136 17.521 69.432 ;
     RECT  17.521 9.648 17.593 69.432 ;
     RECT  17.593 8.688 17.629 69.432 ;
     RECT  17.629 7.872 18.025 69.432 ;
     RECT  18.025 7.68 18.313 69.432 ;
     RECT  18.349 6 18.457 6.024 ;
     RECT  18.313 7.152 18.493 69.432 ;
     RECT  18.457 6 18.608 6.072 ;
     RECT  18.493 7.104 18.608 69.432 ;
     RECT  18.608 2.148 18.712 73.452 ;
     RECT  18.712 2.418 18.904 73.182 ;
     RECT  18.904 20.064 18.929 20.616 ;
     RECT  18.904 11.424 18.965 19.08 ;
     RECT  18.904 49.488 19.073 69.96 ;
     RECT  18.904 5.664 19.897 10.2 ;
     RECT  18.965 11.424 19.897 19.032 ;
     RECT  18.929 20.064 19.897 20.424 ;
     RECT  18.904 21.696 19.897 22.104 ;
     RECT  18.904 23.808 19.897 31.848 ;
     RECT  18.904 32.928 19.897 48.408 ;
     RECT  19.073 49.488 19.897 64.776 ;
     RECT  19.897 20.064 19.933 22.104 ;
     RECT  19.897 23.568 19.933 31.848 ;
     RECT  19.897 32.928 19.933 64.776 ;
     RECT  19.933 20.064 20.473 64.776 ;
     RECT  19.073 65.76 20.473 69.96 ;
     RECT  19.897 5.664 20.509 19.032 ;
     RECT  20.473 20.064 20.509 69.96 ;
     RECT  20.509 5.424 21.516 69.96 ;
     RECT  21.516 36.864 21.593 37.608 ;
    LAYER M5 ;
     RECT  2.4 2.137 2.52 2.151 ;
     RECT  5.1 2.137 5.22 2.151 ;
     RECT  7.8 2.137 7.92 2.151 ;
     RECT  10.5 2.137 10.62 2.151 ;
     RECT  13.2 2.137 13.32 2.151 ;
     RECT  15.9 2.137 16.02 2.151 ;
     RECT  18.6 2.137 18.72 2.151 ;
     RECT  7.8 2.151 8.112 6.133 ;
     RECT  5.1 2.151 5.412 6.229 ;
     RECT  6.912 6.133 8.112 6.229 ;
     RECT  6.864 6.229 8.112 6.851 ;
     RECT  4.752 6.229 5.412 7.907 ;
     RECT  5.1 7.907 5.412 7.909 ;
     RECT  6.912 6.851 8.112 8.147 ;
     RECT  5.1 7.909 5.64 10.307 ;
     RECT  7.8 8.147 8.112 11.365 ;
     RECT  5.1 10.307 5.412 11.893 ;
     RECT  6.912 11.365 8.112 12.227 ;
     RECT  7.8 12.227 8.112 12.469 ;
     RECT  7.8 12.469 8.232 13.139 ;
     RECT  7.8 13.139 8.112 13.621 ;
     RECT  5.1 11.893 5.784 16.499 ;
     RECT  6.96 13.621 8.112 16.501 ;
     RECT  13.2 2.151 13.512 16.837 ;
     RECT  6.864 16.501 8.112 17.077 ;
     RECT  13.056 16.837 13.512 17.123 ;
     RECT  6.864 17.077 8.328 17.651 ;
     RECT  5.1 16.499 5.64 18.757 ;
     RECT  6.864 17.651 8.112 19.523 ;
     RECT  4.416 18.757 5.64 21.395 ;
     RECT  4.512 21.395 5.64 21.635 ;
     RECT  5.1 21.635 5.412 23.317 ;
     RECT  7.104 19.523 8.112 23.557 ;
     RECT  4.464 23.317 5.412 23.987 ;
     RECT  2.4 2.151 2.712 24.277 ;
     RECT  7.104 23.557 8.28 25.045 ;
     RECT  2.4 24.277 2.856 25.139 ;
     RECT  5.1 23.987 5.412 25.381 ;
     RECT  7.056 25.045 8.28 25.381 ;
     RECT  5.1 25.381 8.28 26.147 ;
     RECT  5.1 26.147 8.112 26.243 ;
     RECT  18.6 2.151 18.912 26.245 ;
     RECT  18.6 26.245 19.128 26.389 ;
     RECT  18.48 26.389 19.128 26.435 ;
     RECT  18.48 26.435 18.912 26.579 ;
     RECT  7.8 26.243 8.112 27.301 ;
     RECT  5.1 26.243 6.36 29.029 ;
     RECT  7.8 27.301 8.232 29.029 ;
     RECT  5.1 29.029 8.232 29.123 ;
     RECT  5.1 29.123 8.112 29.365 ;
     RECT  4.464 29.365 8.112 29.461 ;
     RECT  3.792 29.461 8.112 29.795 ;
     RECT  3.792 29.795 6.792 29.891 ;
     RECT  4.464 29.891 6.792 30.757 ;
     RECT  7.8 29.795 8.112 30.757 ;
     RECT  4.464 30.757 8.112 30.899 ;
     RECT  4.464 30.899 6.552 32.437 ;
     RECT  4.464 32.437 6.696 33.779 ;
     RECT  0.336 1.285 0.36 34.165 ;
     RECT  4.464 33.779 6.552 34.213 ;
     RECT  18.6 26.579 18.912 34.645 ;
     RECT  4.08 34.213 6.552 34.741 ;
     RECT  7.8 30.899 8.112 34.741 ;
     RECT  17.808 34.645 18.912 34.787 ;
     RECT  0.24 34.165 0.36 34.931 ;
     RECT  4.08 34.741 8.112 35.363 ;
     RECT  4.944 35.363 8.112 35.747 ;
     RECT  5.1 35.747 8.112 35.987 ;
     RECT  7.632 35.987 8.112 36.515 ;
     RECT  5.1 35.987 6.552 36.851 ;
     RECT  2.4 25.139 2.712 38.149 ;
     RECT  5.1 36.851 6.072 38.533 ;
     RECT  0.336 34.931 0.36 38.819 ;
     RECT  2.4 38.149 3.336 38.915 ;
     RECT  5.1 38.533 6.36 40.405 ;
     RECT  7.8 36.515 8.112 40.405 ;
     RECT  5.1 40.405 8.112 40.885 ;
     RECT  4.944 40.885 8.112 40.981 ;
     RECT  3.744 40.981 3.96 41.651 ;
     RECT  3.744 41.651 3.768 41.699 ;
     RECT  3.84 42.661 3.864 42.709 ;
     RECT  4.944 40.981 8.232 42.709 ;
     RECT  3.84 42.709 8.232 43.235 ;
     RECT  3.84 43.235 6.648 43.379 ;
     RECT  3.936 43.379 6.648 43.475 ;
     RECT  4.512 43.475 6.648 44.437 ;
     RECT  7.8 43.235 8.232 44.437 ;
     RECT  4.512 44.437 8.232 45.059 ;
     RECT  2.4 38.915 2.712 47.749 ;
     RECT  5.1 45.059 8.232 48.131 ;
     RECT  2.4 47.749 3.432 48.515 ;
     RECT  15.9 2.151 16.212 48.901 ;
     RECT  15.9 48.901 17.16 49.043 ;
     RECT  5.1 48.131 8.112 49.619 ;
     RECT  5.1 49.619 6.312 49.861 ;
     RECT  4.512 49.861 6.312 50.965 ;
     RECT  4.416 50.965 6.312 51.395 ;
     RECT  18.6 34.787 18.912 51.637 ;
     RECT  17.904 51.637 18.912 51.779 ;
     RECT  4.416 51.395 6.264 52.403 ;
     RECT  4.512 52.403 6.264 52.405 ;
     RECT  4.512 52.405 6.36 53.123 ;
     RECT  0.24 53.365 0.264 53.555 ;
     RECT  4.512 53.123 6.264 54.085 ;
     RECT  4.512 54.085 6.792 55.525 ;
     RECT  7.8 49.619 8.112 55.525 ;
     RECT  4.512 55.525 8.112 55.813 ;
     RECT  4.464 55.813 8.112 56.531 ;
     RECT  4.512 56.531 8.112 57.059 ;
     RECT  0.24 57.397 0.264 57.539 ;
     RECT  18.6 51.779 18.912 57.733 ;
     RECT  18.48 57.733 18.912 57.923 ;
     RECT  4.992 57.059 8.112 58.643 ;
     RECT  4.992 58.643 5.976 58.645 ;
     RECT  6.96 58.643 8.112 58.645 ;
     RECT  3.936 58.645 3.96 59.315 ;
     RECT  13.2 17.123 13.512 59.701 ;
     RECT  4.944 58.645 5.976 59.797 ;
     RECT  6.96 58.645 8.376 59.797 ;
     RECT  13.2 59.701 13.608 59.843 ;
     RECT  4.944 59.797 8.376 60.515 ;
     RECT  5.1 60.515 8.376 60.563 ;
     RECT  7.8 60.563 8.376 61.043 ;
     RECT  5.1 60.563 6.312 63.205 ;
     RECT  4.512 63.205 6.312 64.549 ;
     RECT  4.512 64.549 6.456 65.461 ;
     RECT  7.8 61.043 8.112 65.461 ;
     RECT  4.512 65.461 8.112 66.707 ;
     RECT  4.512 66.707 6.456 67.187 ;
     RECT  4.512 67.187 6.312 69.059 ;
     RECT  7.8 66.707 8.112 69.829 ;
     RECT  5.1 69.059 6.312 70.163 ;
     RECT  7.392 69.829 8.112 70.259 ;
     RECT  2.4 48.515 2.712 73.449 ;
     RECT  5.1 70.163 5.412 73.449 ;
     RECT  7.8 70.259 8.112 73.449 ;
     RECT  10.5 2.151 10.812 73.449 ;
     RECT  13.2 59.843 13.512 73.449 ;
     RECT  15.9 49.043 16.212 73.449 ;
     RECT  18.6 57.923 18.912 73.449 ;
     RECT  2.4 73.449 2.52 73.463 ;
     RECT  5.1 73.449 5.22 73.463 ;
     RECT  7.8 73.449 7.92 73.463 ;
     RECT  10.5 73.449 10.62 73.463 ;
     RECT  13.2 73.449 13.32 73.463 ;
     RECT  15.9 73.449 16.02 73.463 ;
     RECT  18.6 73.449 18.72 73.463 ;
     RECT  5.412 6.133 6.912 6.229 ;
     RECT  5.412 6.229 6.864 6.851 ;
     RECT  5.412 6.851 6.912 7.909 ;
     RECT  5.64 7.909 6.912 8.147 ;
     RECT  5.412 10.307 5.64 11.365 ;
     RECT  5.412 11.365 6.912 11.893 ;
     RECT  5.784 11.893 6.912 12.227 ;
     RECT  5.784 12.227 7.8 13.621 ;
     RECT  5.784 13.621 6.96 16.499 ;
     RECT  5.64 16.499 6.96 16.501 ;
     RECT  5.64 16.501 6.864 19.523 ;
     RECT  5.64 19.523 7.104 21.635 ;
     RECT  8.112 26.147 8.232 27.301 ;
     RECT  6.36 26.243 7.8 29.029 ;
     RECT  2.712 29.461 3.792 29.891 ;
     RECT  6.792 29.795 7.8 30.757 ;
     RECT  6.552 30.899 7.8 32.437 ;
     RECT  6.696 32.437 7.8 33.779 ;
     RECT  6.552 33.779 7.8 34.741 ;
     RECT  2.712 34.213 4.08 35.363 ;
     RECT  6.552 35.987 7.632 36.515 ;
     RECT  6.552 36.515 7.8 36.851 ;
     RECT  6.36 38.533 7.8 40.405 ;
     RECT  2.712 40.981 3.744 41.699 ;
     RECT  3.96 40.981 4.944 41.651 ;
     RECT  3.768 41.651 4.944 41.699 ;
     RECT  2.712 41.699 4.944 42.661 ;
     RECT  2.712 42.661 3.84 43.379 ;
     RECT  3.864 42.661 4.944 42.709 ;
     RECT  6.648 43.235 7.8 44.437 ;
     RECT  2.712 43.379 3.936 43.475 ;
     RECT  17.16 48.901 18.6 49.043 ;
     RECT  6.312 49.619 7.8 51.395 ;
     RECT  6.264 51.395 7.8 52.405 ;
     RECT  6.36 52.405 7.8 53.123 ;
     RECT  6.264 53.123 7.8 54.085 ;
     RECT  6.792 54.085 7.8 55.525 ;
     RECT  5.976 58.643 6.96 59.797 ;
     RECT  2.712 58.645 3.936 59.315 ;
     RECT  3.96 58.645 4.944 59.315 ;
     RECT  6.312 60.563 7.8 64.549 ;
     RECT  6.456 64.549 7.8 65.461 ;
     RECT  6.456 66.707 7.8 67.187 ;
     RECT  6.312 67.187 7.8 69.829 ;
     RECT  6.312 69.829 7.392 70.163 ;
  END
END qfd_slab_reg512
END LIBRARY
